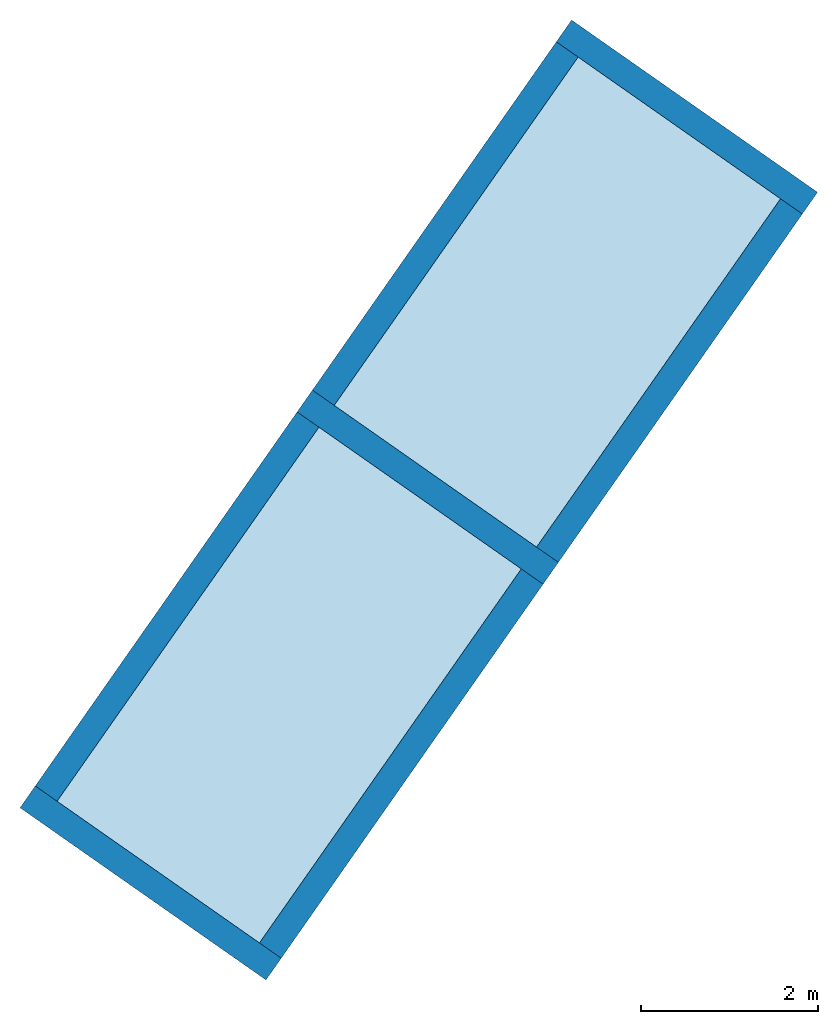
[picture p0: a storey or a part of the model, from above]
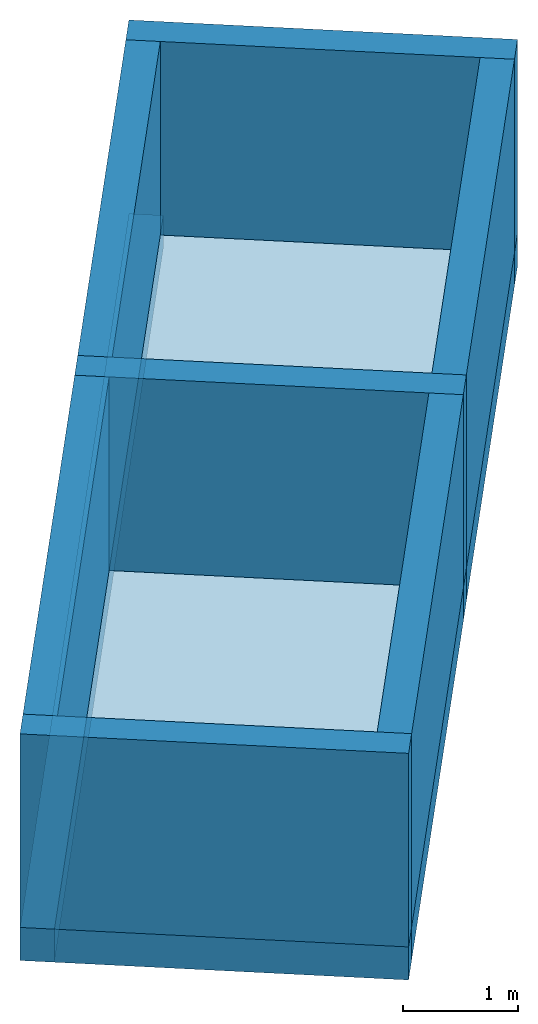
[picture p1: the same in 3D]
Properties of the parts of a building model (IFC2X3), part 1 of 5

# File
Description: ViewDefinition [CoordinationView_V2.0], RevitIdentifiers [VersionGUID: f28ca6dd-f931-496b-9c99-c5065d6128d1, NumberOfSaves: 65], CoordinateReference [CoordinateBase: Coordenadas compartidas, ProjectSite: Emplazamiento por defecto]
File name: IA-001
Time: 2025-02-13T22:48:25+01:00
Written by: ODA SDAI 24.3
Made in: Autodesk Revit 24.1.11.26 (ESP) - IFC 24.1.11.26

# IfcProject, IA-001
LongName: Unifamiliar Sant Josep de Sa Talaia; Phase: Estado de proyecto

# IfcSite, Default
RefLatitude: 40, 24, 0, 5493; RefLongitude: -3, -40, -59, -880065; RefElevation: 0 m

# IfcBuilding
Pset_BuildingCommon - NumberOfStoreys: 5

# IfcBuildingStorey: Nivel:Extremo inicial 8 mm (6)
Name | LongName | Elevation (m)
Depósito | Depósito | 93.64
Depósito_ | Depósito_ | 93.64
PB_ | PB_ | 95.94
PB | PB | 95.94
F1_ | F1_ | 99.52
F1 | F1 | 99.52

# IfcBeam (44)
Material: Hormigón armado
Pset_BeamCommon - Slope: 0 deg; IsExternal: no; LoadBearing: yes
Name | In
237957 | PB
237960 | PB
237963 | PB
237966 | PB
237969 | PB
237972 | PB
237975 | PB
237978 | PB
237981 | PB
237984 | PB
237987 | PB
237990 | PB
237993 | PB
237996 | PB
238196 | F1
238199 | F1
238202 | F1
238205 | F1
238208 | F1
238277 | F1
238280 | F1
238283 | F1
238286 | F1
238289 | F1
238292 | F1
238295 | F1
238298 | F1
238301 | F1
238434 | PB
238437 | PB
238440 | PB
238443 | PB
238547 | PB
238550 | PB
238564 | PB
238567 | PB
238582 | PB
238585 | PB
238588 | PB
238599 | PB
238602 | PB
238605 | PB
238641 | PB
238644 | PB

# IfcBeam: 1xT-18|T-0 (14)
In: Depósito_
Description: Pretensada. T18(20+5). Hormigón armado; Material: Hormigón armado
Pset_BeamCommon - IsExternal: no; LoadBearing: yes; Slope: 88.8324 deg
Pset_QuantityTakeOff - sets with these values: 2
Name | Pset_BeamCommon, Reference = Pset_QuantityTakeOff, Reference
Vigueta 1 (Paño 1) (1xT-18/T-0) | Vigueta 1 (Paño 1) (1xT-18/T-0)
Vigueta 2 (Paño 1) (1xT-18/T-0) | Vigueta 2 (Paño 1) (1xT-18/T-0)
Vigueta 3 (Paño 1) (1xT-18/T-0) | Vigueta 3 (Paño 1) (1xT-18/T-0)
Vigueta 4 (Paño 1) (1xT-18/T-0) | Vigueta 4 (Paño 1) (1xT-18/T-0)
Vigueta 5 (Paño 1) (1xT-18/T-0) | Vigueta 5 (Paño 1) (1xT-18/T-0)
Vigueta 6 (Paño 1) (1xT-18/T-0) | Vigueta 6 (Paño 1) (1xT-18/T-0)
Vigueta 7 (Paño 1) (1xT-18/T-0) | Vigueta 7 (Paño 1) (1xT-18/T-0)
Vigueta 1 (Paño 2) (1xT-18/T-0) | Vigueta 1 (Paño 2) (1xT-18/T-0)
Vigueta 2 (Paño 2) (1xT-18/T-0) | Vigueta 2 (Paño 2) (1xT-18/T-0)
Vigueta 3 (Paño 2) (1xT-18/T-0) | Vigueta 3 (Paño 2) (1xT-18/T-0)
Vigueta 4 (Paño 2) (1xT-18/T-0) | Vigueta 4 (Paño 2) (1xT-18/T-0)
Vigueta 5 (Paño 2) (1xT-18/T-0) | Vigueta 5 (Paño 2) (1xT-18/T-0)
Vigueta 6 (Paño 2) (1xT-18/T-0) | Vigueta 6 (Paño 2) (1xT-18/T-0)
Vigueta 7 (Paño 2) (1xT-18/T-0) | Vigueta 7 (Paño 2) (1xT-18/T-0)

# IfcBeam: 25x30 (4)
In: F1
Description: Rectangular. Hormigón armado; Material: Hormigón armado
Pset_BeamCommon - IsExternal: no; LoadBearing: yes
Pset_QuantityTakeOff - sets with these values: 2
Name | Pset_BeamCommon, Reference = Pset_QuantityTakeOff, Reference
Viga 27 (25x30) | Viga 27 (25x30)
Viga 28 (25x30) | Viga 28 (25x30)
Viga 32 (25x30) | Viga 32 (25x30)
Viga 33 (25x30) | Viga 33 (25x30)

# IfcBeam: 30x25 (9)
In: PB
Description: Rectangular. Hormigón armado; Material: Hormigón armado
Pset_BeamCommon - IsExternal: no; LoadBearing: yes
Pset_QuantityTakeOff - sets with these values: 2
Name | Pset_BeamCommon, Reference = Pset_QuantityTakeOff, Reference
Viga 1 (30x25) | Viga 1 (30x25)
Viga 2 (30x25) | Viga 2 (30x25)
Viga 3 (30x25) | Viga 3 (30x25)
Viga 4 (30x25) | Viga 4 (30x25)
Viga 5 (30x25) | Viga 5 (30x25)
Viga 6 (30x25) | Viga 6 (30x25)
Viga 7 (30x25) | Viga 7 (30x25)
Viga 8 (30x25) | Viga 8 (30x25)
Viga 9 (30x25) | Viga 9 (30x25)

# IfcBeam: 30x30 (17)
In: F1
Description: Rectangular. Hormigón armado; Material: Hormigón armado
Pset_BeamCommon - IsExternal: no; LoadBearing: yes
Pset_QuantityTakeOff - sets with these values: 2
Name | Pset_BeamCommon, Reference = Pset_QuantityTakeOff, Reference
Viga 1 (30x30) | Viga 1 (30x30)
Viga 2 (30x30) | Viga 2 (30x30)
Viga 3 (30x30) | Viga 3 (30x30)
Viga 11 (30x30) | Viga 11 (30x30)
Viga 12 (30x30) | Viga 12 (30x30)
Viga 13 (30x30) | Viga 13 (30x30)
Viga 14 (30x30) | Viga 14 (30x30)
Viga 15 (30x30) | Viga 15 (30x30)
Viga 16 (30x30) | Viga 16 (30x30)
Viga 17 (30x30) | Viga 17 (30x30)
Viga 18 (30x30) | Viga 18 (30x30)
Viga 19 (30x30) | Viga 19 (30x30)
Viga 20 (30x30) | Viga 20 (30x30)
Viga 29 (30x30) | Viga 29 (30x30)
Viga 31 (30x30) | Viga 31 (30x30)
Viga 34 (30x30) | Viga 34 (30x30)
Viga 35 (30x30) | Viga 35 (30x30)

# IfcBeam: 30x38, Viga 5 (30x38)
In: F1
Description: Rectangular. Hormigón armado; Material: Hormigón armado
Pset_BeamCommon - IsExternal: no; LoadBearing: yes; Reference: Viga 5 (30x38)
Pset_QuantityTakeOff - Reference: Viga 5 (30x38); sets with these values: 2

# IfcBeam: 30x72 (2)
In: F1
Description: Rectangular. Hormigón armado; Material: Hormigón armado
Pset_BeamCommon - IsExternal: no; LoadBearing: yes
Pset_QuantityTakeOff - sets with these values: 2
Name | Pset_BeamCommon, Reference = Pset_QuantityTakeOff, Reference
Viga 21 (30x72) | Viga 21 (30x72)
Viga 22 (30x72) | Viga 22 (30x72)

# IfcBeam: 30x76 (3)
In: F1
Description: Rectangular. Hormigón armado; Material: Hormigón armado
Pset_BeamCommon - IsExternal: no; LoadBearing: yes
Pset_QuantityTakeOff - sets with these values: 2
Name | Pset_BeamCommon, Reference = Pset_QuantityTakeOff, Reference
Viga 8 (30x76) | Viga 8 (30x76)
Viga 9 (30x76) | Viga 9 (30x76)
Viga 10 (30x76) | Viga 10 (30x76)

# IfcBeam: 30x80 (3)
In: F1
Description: Rectangular. Hormigón armado; Material: Hormigón armado
Pset_BeamCommon - IsExternal: no; LoadBearing: yes
Pset_QuantityTakeOff - sets with these values: 2
Name | Pset_BeamCommon, Reference = Pset_QuantityTakeOff, Reference
Viga 4 (30x80) | Viga 4 (30x80)
Viga 6 (30x80) | Viga 6 (30x80)
Viga 7 (30x80) | Viga 7 (30x80)

# IfcBeam: FOOTING_BEAM (5)
In: Depósito
Description: Rectangular. Hormigón armado; Material: Hormigón armado
Pset_BeamCommon - IsExternal: no; LoadBearing: yes
Pset_QuantityTakeOff - sets with these values: 2
Name | Pset_BeamCommon, Reference = Pset_QuantityTakeOff, Reference
Viga 1 (30x35) | Viga 1 (30x35)
Viga 2 (30x35) | Viga 2 (30x35)
Viga 3 (30x35) | Viga 3 (30x35)
Viga 4 (30x35) | Viga 4 (30x35)
Viga 5 (30x35) | Viga 5 (30x35)

# IfcBeam: Hormigón-Viga rectangular:300 x 400mm (5)
In: PB_
Type - Pset_BeamCommon - IsExternal: no; LoadBearing: yes
Pset_BeamCommon - Reference: 300 x 400mm; Span: 2.777 m; Slope: 0 deg
Pset_QuantityTakeOff - Reference: 300 x 400mm; sets with these values: 2
Name (Hormigón-Viga rectangular:300 x 400mm:...)
236829
236830
236831
236832
236833

# IfcBeam: Hormigón-Viga rectangular:400 x 400mm (5)
In: PB_
Type - Pset_BeamCommon - IsExternal: no; LoadBearing: yes
Pset_BeamCommon - Slope: 0 deg; Reference: 400 x 400mm
Pset_QuantityTakeOff - Reference: 400 x 400mm; sets with these values: 2
Name (Hormigón-Viga rectangular:400 x 400mm:...) | Span (m)
236834 | 3.61
236835 | 4.9
236836 | 4.915
236837 | 4.534
236838 | 4.602

# IfcBeam: Vigueta 1 (Paño 10) (Mf = 2.77)
In: PB
Type - Description: Armada. Covicsa Armada(25+5). Hormigón armado; PredefinedType: JOIST
Pset_BeamCommon - IsExternal: no; LoadBearing: yes; Reference: Vigueta 1 (Paño 10) (Mf = 2.77); Slope: 7.71638 deg
Pset_QuantityTakeOff - Reference: Vigueta 1 (Paño 10) (Mf = 2.77); sets with these values: 2

# IfcBeam: Vigueta 1 (Paño 11) (Mf = 0.88)
In: PB
Type - Description: Armada. Covicsa Armada(25+5). Hormigón armado; PredefinedType: JOIST
Pset_BeamCommon - IsExternal: no; LoadBearing: yes; Reference: Vigueta 1 (Paño 11) (Mf = 0.88); Slope: 7.71638 deg
Pset_QuantityTakeOff - Reference: Vigueta 1 (Paño 11) (Mf = 0.88); sets with these values: 2

# IfcBeam: Vigueta 1 (Paño 13) (Mf = 11.99)
In: PB
Type - Description: Armada. Covicsa Armada(25+5). Hormigón armado; PredefinedType: JOIST
Pset_BeamCommon - IsExternal: no; LoadBearing: yes; Reference: Vigueta 1 (Paño 13) (Mf = 11.99); Slope: 7.71638 deg
Pset_QuantityTakeOff - Reference: Vigueta 1 (Paño 13) (Mf = 11.99); sets with these values: 2

# IfcBeam: Vigueta 1 (Paño 15) (Mf = 33.15)
In: PB
Type - Description: Armada. Covicsa Armada(25+5). Hormigón armado; PredefinedType: JOIST
Pset_BeamCommon - IsExternal: no; LoadBearing: yes; Reference: Vigueta 1 (Paño 15) (Mf = 33.15); Slope: 7.71638 deg
Pset_QuantityTakeOff - Reference: Vigueta 1 (Paño 15) (Mf = 33.15); sets with these values: 2

# IfcBeam: Vigueta 1 (Paño 2) (Mf = 10.75)
In: PB
Type - Description: Armada. Covicsa Armada(25+5). Hormigón armado; PredefinedType: JOIST
Pset_BeamCommon - IsExternal: no; LoadBearing: yes; Reference: Vigueta 1 (Paño 2) (Mf = 10.75); Slope: 7.71638 deg
Pset_QuantityTakeOff - Reference: Vigueta 1 (Paño 2) (Mf = 10.75); sets with these values: 2

# IfcBeam: Vigueta 1 (Paño 3) (Mf = 14.41)
In: F1
Type - Description: Armada. Covicsa Armada(25+5). Hormigón armado; PredefinedType: JOIST
Pset_BeamCommon - IsExternal: no; LoadBearing: yes; Reference: Vigueta 1 (Paño 3) (Mf = 14.41); Slope: 7.71638 deg
Pset_QuantityTakeOff - Reference: Vigueta 1 (Paño 3) (Mf = 14.41); sets with these values: 2

# IfcBeam: Vigueta 1 (Paño 4) (Mf = 14.15)
In: F1
Type - Description: Armada. Covicsa Armada(25+5). Hormigón armado; PredefinedType: JOIST
Pset_BeamCommon - IsExternal: no; LoadBearing: yes; Reference: Vigueta 1 (Paño 4) (Mf = 14.15); Slope: 7.71638 deg
Pset_QuantityTakeOff - Reference: Vigueta 1 (Paño 4) (Mf = 14.15); sets with these values: 2

# IfcBeam: Vigueta 1 (Paño 6) (Mf = 33.36)
In: PB
Type - Description: Armada. Covicsa Armada(25+5). Hormigón armado; PredefinedType: JOIST
Pset_BeamCommon - IsExternal: no; LoadBearing: yes; Reference: Vigueta 1 (Paño 6) (Mf = 33.36); Slope: 7.71638 deg
Pset_QuantityTakeOff - Reference: Vigueta 1 (Paño 6) (Mf = 33.36); sets with these values: 2

# IfcBeam: Vigueta 1 (Paño 8) (Mf = 1.45)
In: PB
Type - Description: Armada. Covicsa Armada(25+5). Hormigón armado; PredefinedType: JOIST
Pset_BeamCommon - IsExternal: no; LoadBearing: yes; Reference: Vigueta 1 (Paño 8) (Mf = 1.45); Slope: 7.71638 deg
Pset_QuantityTakeOff - Reference: Vigueta 1 (Paño 8) (Mf = 1.45); sets with these values: 2

# IfcBeam: Vigueta 10 (Paño 2) (Mf = 10.63)
In: PB
Type - Description: Armada. Covicsa Armada(25+5). Hormigón armado; PredefinedType: JOIST
Pset_BeamCommon - IsExternal: no; LoadBearing: yes; Reference: Vigueta 10 (Paño 2) (Mf = 10.63); Slope: 7.71638 deg
Pset_QuantityTakeOff - Reference: Vigueta 10 (Paño 2) (Mf = 10.63); sets with these values: 2

# IfcBeam: Vigueta 11 (Paño 2) (Mf = 10.8)
In: PB
Type - Description: Armada. Covicsa Armada(25+5). Hormigón armado; PredefinedType: JOIST
Pset_BeamCommon - IsExternal: no; LoadBearing: yes; Reference: Vigueta 11 (Paño 2) (Mf = 10.8); Slope: 7.71638 deg
Pset_QuantityTakeOff - Reference: Vigueta 11 (Paño 2) (Mf = 10.8); sets with these values: 2

# IfcBeam: Vigueta 12 (Paño 2) (Mf = 10.92)
In: PB
Type - Description: Armada. Covicsa Armada(25+5). Hormigón armado; PredefinedType: JOIST
Pset_BeamCommon - IsExternal: no; LoadBearing: yes; Reference: Vigueta 12 (Paño 2) (Mf = 10.92); Slope: 7.71638 deg
Pset_QuantityTakeOff - Reference: Vigueta 12 (Paño 2) (Mf = 10.92); sets with these values: 2

# IfcBeam: Vigueta 13 (Paño 2) (Mf = 11.09)
In: PB
Type - Description: Armada. Covicsa Armada(25+5). Hormigón armado; PredefinedType: JOIST
Pset_BeamCommon - IsExternal: no; LoadBearing: yes; Reference: Vigueta 13 (Paño 2) (Mf = 11.09); Slope: 7.71638 deg
Pset_QuantityTakeOff - Reference: Vigueta 13 (Paño 2) (Mf = 11.09); sets with these values: 2

# IfcBeam: Vigueta 14 (Paño 2) (Mf = 11.17)
In: PB
Type - Description: Armada. Covicsa Armada(25+5). Hormigón armado; PredefinedType: JOIST
Pset_BeamCommon - IsExternal: no; LoadBearing: yes; Reference: Vigueta 14 (Paño 2) (Mf = 11.17); Slope: 7.71638 deg
Pset_QuantityTakeOff - Reference: Vigueta 14 (Paño 2) (Mf = 11.17); sets with these values: 2

# IfcBeam: Vigueta 2 (Paño 10) (Mf = 3.51)
In: PB
Type - Description: Armada. Covicsa Armada(25+5). Hormigón armado; PredefinedType: JOIST
Pset_BeamCommon - IsExternal: no; LoadBearing: yes; Reference: Vigueta 2 (Paño 10) (Mf = 3.51); Slope: 7.71638 deg
Pset_QuantityTakeOff - Reference: Vigueta 2 (Paño 10) (Mf = 3.51); sets with these values: 2

# IfcBeam: Vigueta 2 (Paño 11) (Mf = 0.17)
In: PB
Type - Description: Armada. Covicsa Armada(25+5). Hormigón armado; PredefinedType: JOIST
Pset_BeamCommon - IsExternal: no; LoadBearing: yes; Reference: Vigueta 2 (Paño 11) (Mf = 0.17); Slope: 7.71638 deg
Pset_QuantityTakeOff - Reference: Vigueta 2 (Paño 11) (Mf = 0.17); sets with these values: 2

# IfcBeam: Vigueta 2 (Paño 13) (Mf = 10.31)
In: PB
Type - Description: Armada. Covicsa Armada(25+5). Hormigón armado; PredefinedType: JOIST
Pset_BeamCommon - IsExternal: no; LoadBearing: yes; Reference: Vigueta 2 (Paño 13) (Mf = 10.31); Slope: 7.71638 deg
Pset_QuantityTakeOff - Reference: Vigueta 2 (Paño 13) (Mf = 10.31); sets with these values: 2

# IfcBeam: Vigueta 2 (Paño 15) (Mf = 35.75)
In: PB
Type - Description: Armada. Covicsa Armada(25+5). Hormigón armado; PredefinedType: JOIST
Pset_BeamCommon - IsExternal: no; LoadBearing: yes; Reference: Vigueta 2 (Paño 15) (Mf = 35.75); Slope: 7.71638 deg
Pset_QuantityTakeOff - Reference: Vigueta 2 (Paño 15) (Mf = 35.75); sets with these values: 2

# IfcBeam: Vigueta 2 (Paño 2) (Mf = 10.94)
In: PB
Type - Description: Armada. Covicsa Armada(25+5). Hormigón armado; PredefinedType: JOIST
Pset_BeamCommon - IsExternal: no; LoadBearing: yes; Reference: Vigueta 2 (Paño 2) (Mf = 10.94); Slope: 7.71638 deg
Pset_QuantityTakeOff - Reference: Vigueta 2 (Paño 2) (Mf = 10.94); sets with these values: 2

# IfcBeam: Vigueta 2 (Paño 3) (Mf = 14.34)
In: F1
Type - Description: Armada. Covicsa Armada(25+5). Hormigón armado; PredefinedType: JOIST
Pset_BeamCommon - IsExternal: no; LoadBearing: yes; Reference: Vigueta 2 (Paño 3) (Mf = 14.34); Slope: 7.71638 deg
Pset_QuantityTakeOff - Reference: Vigueta 2 (Paño 3) (Mf = 14.34); sets with these values: 2

# IfcBeam: Vigueta 2 (Paño 4) (Mf = 14.17)
In: F1
Type - Description: Armada. Covicsa Armada(25+5). Hormigón armado; PredefinedType: JOIST
Pset_BeamCommon - IsExternal: no; LoadBearing: yes; Reference: Vigueta 2 (Paño 4) (Mf = 14.17); Slope: 7.71638 deg
Pset_QuantityTakeOff - Reference: Vigueta 2 (Paño 4) (Mf = 14.17); sets with these values: 2

# IfcBeam: Vigueta 2 (Paño 6) (Mf = 33.44)
In: PB
Type - Description: Armada. Covicsa Armada(25+5). Hormigón armado; PredefinedType: JOIST
Pset_BeamCommon - IsExternal: no; LoadBearing: yes; Reference: Vigueta 2 (Paño 6) (Mf = 33.44); Slope: 7.71638 deg
Pset_QuantityTakeOff - Reference: Vigueta 2 (Paño 6) (Mf = 33.44); sets with these values: 2

# IfcBeam: Vigueta 2 (Paño 8) (Mf = 1.52)
In: PB
Type - Description: Armada. Covicsa Armada(25+5). Hormigón armado; PredefinedType: JOIST
Pset_BeamCommon - IsExternal: no; LoadBearing: yes; Reference: Vigueta 2 (Paño 8) (Mf = 1.52); Slope: 7.71638 deg
Pset_QuantityTakeOff - Reference: Vigueta 2 (Paño 8) (Mf = 1.52); sets with these values: 2

# IfcBeam: Vigueta 3 (Paño 11) (Mf = 0.89)
In: PB
Type - Description: Armada. Covicsa Armada(25+5). Hormigón armado; PredefinedType: JOIST
Pset_BeamCommon - IsExternal: no; LoadBearing: yes; Reference: Vigueta 3 (Paño 11) (Mf = 0.89); Slope: 7.71638 deg
Pset_QuantityTakeOff - Reference: Vigueta 3 (Paño 11) (Mf = 0.89); sets with these values: 2

# IfcBeam: Vigueta 3 (Paño 13) (Mf = 11.97)
In: PB
Type - Description: Armada. Covicsa Armada(25+5). Hormigón armado; PredefinedType: JOIST
Pset_BeamCommon - IsExternal: no; LoadBearing: yes; Reference: Vigueta 3 (Paño 13) (Mf = 11.97); Slope: 7.71638 deg
Pset_QuantityTakeOff - Reference: Vigueta 3 (Paño 13) (Mf = 11.97); sets with these values: 2

# IfcBeam: Vigueta 3 (Paño 2) (Mf = 10.32)
In: PB
Type - Description: Armada. Covicsa Armada(25+5). Hormigón armado; PredefinedType: JOIST
Pset_BeamCommon - IsExternal: no; LoadBearing: yes; Reference: Vigueta 3 (Paño 2) (Mf = 10.32); Slope: 7.71638 deg
Pset_QuantityTakeOff - Reference: Vigueta 3 (Paño 2) (Mf = 10.32); sets with these values: 2

# IfcBeam: Vigueta 3 (Paño 3) (Mf = 14.33)
In: F1
Type - Description: Armada. Covicsa Armada(25+5). Hormigón armado; PredefinedType: JOIST
Pset_BeamCommon - IsExternal: no; LoadBearing: yes; Reference: Vigueta 3 (Paño 3) (Mf = 14.33); Slope: 7.71638 deg
Pset_QuantityTakeOff - Reference: Vigueta 3 (Paño 3) (Mf = 14.33); sets with these values: 2

# IfcBeam: Vigueta 3 (Paño 4) (Mf = 14.35)
In: F1
Type - Description: Armada. Covicsa Armada(25+5). Hormigón armado; PredefinedType: JOIST
Pset_BeamCommon - IsExternal: no; LoadBearing: yes; Reference: Vigueta 3 (Paño 4) (Mf = 14.35); Slope: 7.71638 deg
Pset_QuantityTakeOff - Reference: Vigueta 3 (Paño 4) (Mf = 14.35); sets with these values: 2

# IfcBeam: Vigueta 3 (Paño 6) (Mf = 33.48)
In: PB
Type - Description: Armada. Covicsa Armada(25+5). Hormigón armado; PredefinedType: JOIST
Pset_BeamCommon - IsExternal: no; LoadBearing: yes; Reference: Vigueta 3 (Paño 6) (Mf = 33.48); Slope: 7.71638 deg
Pset_QuantityTakeOff - Reference: Vigueta 3 (Paño 6) (Mf = 33.48); sets with these values: 2

# IfcBeam: Vigueta 4 (Paño 2) (Mf = 10.95)
In: PB
Type - Description: Armada. Covicsa Armada(25+5). Hormigón armado; PredefinedType: JOIST
Pset_BeamCommon - IsExternal: no; LoadBearing: yes; Reference: Vigueta 4 (Paño 2) (Mf = 10.95); Slope: 7.71638 deg
Pset_QuantityTakeOff - Reference: Vigueta 4 (Paño 2) (Mf = 10.95); sets with these values: 2

# IfcBeam: Vigueta 4 (Paño 3) (Mf = 14.22)
In: F1
Type - Description: Armada. Covicsa Armada(25+5). Hormigón armado; PredefinedType: JOIST
Pset_BeamCommon - IsExternal: no; LoadBearing: yes; Reference: Vigueta 4 (Paño 3) (Mf = 14.22); Slope: 7.71638 deg
Pset_QuantityTakeOff - Reference: Vigueta 4 (Paño 3) (Mf = 14.22); sets with these values: 2

# IfcBeam: Vigueta 4 (Paño 4) (Mf = 14.11)
In: F1
Type - Description: Armada. Covicsa Armada(25+5). Hormigón armado; PredefinedType: JOIST
Pset_BeamCommon - IsExternal: no; LoadBearing: yes; Reference: Vigueta 4 (Paño 4) (Mf = 14.11); Slope: 7.71638 deg
Pset_QuantityTakeOff - Reference: Vigueta 4 (Paño 4) (Mf = 14.11); sets with these values: 2

# IfcBeam: Vigueta 4 (Paño 6) (Mf = 33.44)
In: PB
Type - Description: Armada. Covicsa Armada(25+5). Hormigón armado; PredefinedType: JOIST
Pset_BeamCommon - IsExternal: no; LoadBearing: yes; Reference: Vigueta 4 (Paño 6) (Mf = 33.44); Slope: 7.71638 deg
Pset_QuantityTakeOff - Reference: Vigueta 4 (Paño 6) (Mf = 33.44); sets with these values: 2

# IfcBeam: Vigueta 5 (Paño 2) (Mf = 10.69)
In: PB
Type - Description: Armada. Covicsa Armada(25+5). Hormigón armado; PredefinedType: JOIST
Pset_BeamCommon - IsExternal: no; LoadBearing: yes; Reference: Vigueta 5 (Paño 2) (Mf = 10.69); Slope: 7.71638 deg
Pset_QuantityTakeOff - Reference: Vigueta 5 (Paño 2) (Mf = 10.69); sets with these values: 2

# IfcBeam: Vigueta 5 (Paño 3) (Mf = 14.15)
In: F1
Type - Description: Armada. Covicsa Armada(25+5). Hormigón armado; PredefinedType: JOIST
Pset_BeamCommon - IsExternal: no; LoadBearing: yes; Reference: Vigueta 5 (Paño 3) (Mf = 14.15); Slope: 7.71638 deg
Pset_QuantityTakeOff - Reference: Vigueta 5 (Paño 3) (Mf = 14.15); sets with these values: 2

# IfcBeam: Vigueta 5 (Paño 4) (Mf = 14.09)
In: F1
Type - Description: Armada. Covicsa Armada(25+5). Hormigón armado; PredefinedType: JOIST
Pset_BeamCommon - IsExternal: no; LoadBearing: yes; Reference: Vigueta 5 (Paño 4) (Mf = 14.09); Slope: 7.71638 deg
Pset_QuantityTakeOff - Reference: Vigueta 5 (Paño 4) (Mf = 14.09); sets with these values: 2

# IfcBeam: Vigueta 6 (Paño 2) (Mf = 11.1)
In: PB
Type - Description: Armada. Covicsa Armada(25+5). Hormigón armado; PredefinedType: JOIST
Pset_BeamCommon - IsExternal: no; LoadBearing: yes; Reference: Vigueta 6 (Paño 2) (Mf = 11.1); Slope: 7.71638 deg
Pset_QuantityTakeOff - Reference: Vigueta 6 (Paño 2) (Mf = 11.1); sets with these values: 2

# IfcBeam: Vigueta 6 (Paño 4) (Mf = 11.71)
In: F1
Type - Description: Armada. Covicsa Armada(25+5). Hormigón armado; PredefinedType: JOIST
Pset_BeamCommon - IsExternal: no; LoadBearing: yes; Reference: Vigueta 6 (Paño 4) (Mf = 11.71); Slope: 7.71638 deg
Pset_QuantityTakeOff - Reference: Vigueta 6 (Paño 4) (Mf = 11.71); sets with these values: 2

# IfcBeam: Vigueta 7 (Paño 2) (Mf = 11.18)
In: PB
Type - Description: Armada. Covicsa Armada(25+5). Hormigón armado; PredefinedType: JOIST
Pset_BeamCommon - IsExternal: no; LoadBearing: yes; Reference: Vigueta 7 (Paño 2) (Mf = 11.18); Slope: 7.71638 deg
Pset_QuantityTakeOff - Reference: Vigueta 7 (Paño 2) (Mf = 11.18); sets with these values: 2

# IfcBeam: Vigueta 7 (Paño 4) (Mf = 14.16)
In: F1
Type - Description: Armada. Covicsa Armada(25+5). Hormigón armado; PredefinedType: JOIST
Pset_BeamCommon - IsExternal: no; LoadBearing: yes; Reference: Vigueta 7 (Paño 4) (Mf = 14.16); Slope: 7.71638 deg
Pset_QuantityTakeOff - Reference: Vigueta 7 (Paño 4) (Mf = 14.16); sets with these values: 2

# IfcBeam: Vigueta 8 (Paño 2) (Mf = 11.16)
In: PB
Type - Description: Armada. Covicsa Armada(25+5). Hormigón armado; PredefinedType: JOIST
Pset_BeamCommon - IsExternal: no; LoadBearing: yes; Reference: Vigueta 8 (Paño 2) (Mf = 11.16); Slope: 7.71638 deg
Pset_QuantityTakeOff - Reference: Vigueta 8 (Paño 2) (Mf = 11.16); sets with these values: 2

# IfcBeam: Vigueta 8 (Paño 4) (Mf = 14.18)
In: F1
Type - Description: Armada. Covicsa Armada(25+5). Hormigón armado; PredefinedType: JOIST
Pset_BeamCommon - IsExternal: no; LoadBearing: yes; Reference: Vigueta 8 (Paño 4) (Mf = 14.18); Slope: 7.71638 deg
Pset_QuantityTakeOff - Reference: Vigueta 8 (Paño 4) (Mf = 14.18); sets with these values: 2

# IfcBeam: Vigueta 9 (Paño 2) (Mf = 11)
In: PB
Type - Description: Armada. Covicsa Armada(25+5). Hormigón armado; PredefinedType: JOIST
Pset_BeamCommon - IsExternal: no; LoadBearing: yes; Reference: Vigueta 9 (Paño 2) (Mf = 11); Slope: 7.71638 deg
Pset_QuantityTakeOff - Reference: Vigueta 9 (Paño 2) (Mf = 11); sets with these values: 2

# IfcBeam: Vigueta 9 (Paño 4) (Mf = 14.29)
In: F1
Type - Description: Armada. Covicsa Armada(25+5). Hormigón armado; PredefinedType: JOIST
Pset_BeamCommon - IsExternal: no; LoadBearing: yes; Reference: Vigueta 9 (Paño 4) (Mf = 14.29); Slope: 7.71638 deg
Pset_QuantityTakeOff - Reference: Vigueta 9 (Paño 4) (Mf = 14.29); sets with these values: 2

# IfcBuildingElementProxy: Bovedilla 0-1 (Paño 10)
In: PB
Type - Description: Bovedilla de hormigón; PredefinedType: USERDEFINED
Pset_BuildingElementProxyCommon - Reference: Bovedilla 0-1 (Paño 10); sets with these values: 2
Pset_ProvisionForVoid - Shape: Undefined; Width: 0.58 m; Height: 0.25 m; Depth: 0.25 m

# IfcBuildingElementProxy: Bovedilla 0-1 (Paño 6)
In: PB
Type - Description: Bovedilla de hormigón; PredefinedType: USERDEFINED
Pset_BuildingElementProxyCommon - Reference: Bovedilla 0-1 (Paño 6); sets with these values: 2
Pset_ProvisionForVoid - Shape: Undefined; Width: 0.58 m; Height: 0.25 m; Depth: 0.25 m

# IfcBuildingElementProxy: Bovedilla 0-1 (Paño 8)
In: PB
Type - Description: Bovedilla de hormigón; PredefinedType: USERDEFINED
Pset_BuildingElementProxyCommon - Reference: Bovedilla 0-1 (Paño 8); sets with these values: 2
Pset_ProvisionForVoid - Shape: Undefined; Width: 0.58 m; Height: 0.25 m; Depth: 0.25 m

# IfcBuildingElementProxy: Bovedilla 0-10 (Paño 6)
In: PB
Type - Description: Bovedilla de hormigón; PredefinedType: USERDEFINED
Pset_BuildingElementProxyCommon - Reference: Bovedilla 0-10 (Paño 6); sets with these values: 2
Pset_ProvisionForVoid - Shape: Undefined; Width: 0.58 m; Height: 0.25 m; Depth: 0.25 m

# IfcBuildingElementProxy: Bovedilla 0-11 (Paño 6)
In: PB
Type - Description: Bovedilla de hormigón; PredefinedType: USERDEFINED
Pset_BuildingElementProxyCommon - Reference: Bovedilla 0-11 (Paño 6); sets with these values: 2
Pset_ProvisionForVoid - Shape: Undefined; Width: 0.58 m; Height: 0.25 m; Depth: 0.25 m

# IfcBuildingElementProxy: Bovedilla 0-12 (Paño 6)
In: PB
Type - Description: Bovedilla de hormigón; PredefinedType: USERDEFINED
Pset_BuildingElementProxyCommon - Reference: Bovedilla 0-12 (Paño 6); sets with these values: 2
Pset_ProvisionForVoid - Shape: Undefined; Width: 0.58 m; Height: 0.25 m; Depth: 0.25 m

# IfcBuildingElementProxy: Bovedilla 0-13 (Paño 6)
In: PB
Type - Description: Bovedilla de hormigón; PredefinedType: USERDEFINED
Pset_BuildingElementProxyCommon - Reference: Bovedilla 0-13 (Paño 6); sets with these values: 2
Pset_ProvisionForVoid - Shape: Undefined; Width: 0.58 m; Height: 0.25 m; Depth: 0.25 m

# IfcBuildingElementProxy: Bovedilla 0-14 (Paño 6)
In: PB
Type - Description: Bovedilla de hormigón; PredefinedType: USERDEFINED
Pset_BuildingElementProxyCommon - Reference: Bovedilla 0-14 (Paño 6); sets with these values: 2
Pset_ProvisionForVoid - Shape: Undefined; Width: 0.58 m; Height: 0.25 m; Depth: 0.25 m

# IfcBuildingElementProxy: Bovedilla 0-15 (Paño 6)
In: PB
Type - Description: Bovedilla de hormigón; PredefinedType: USERDEFINED
Pset_BuildingElementProxyCommon - Reference: Bovedilla 0-15 (Paño 6); sets with these values: 2
Pset_ProvisionForVoid - Shape: Undefined; Width: 0.58 m; Height: 0.25 m; Depth: 0.25 m

# IfcBuildingElementProxy: Bovedilla 0-16 (Paño 6)
In: PB
Type - Description: Bovedilla de hormigón; PredefinedType: USERDEFINED
Pset_BuildingElementProxyCommon - Reference: Bovedilla 0-16 (Paño 6); sets with these values: 2
Pset_ProvisionForVoid - Shape: Undefined; Width: 0.58 m; Height: 0.25 m; Depth: 0.25 m

# IfcBuildingElementProxy: Bovedilla 0-17 (Paño 6)
In: PB
Type - Description: Bovedilla de hormigón; PredefinedType: USERDEFINED
Pset_BuildingElementProxyCommon - Reference: Bovedilla 0-17 (Paño 6); sets with these values: 2
Pset_ProvisionForVoid - Shape: Undefined; Width: 0.58 m; Height: 0.25 m; Depth: 0.25 m

# IfcBuildingElementProxy: Bovedilla 0-18 (Paño 6)
In: PB
Type - Description: Bovedilla de hormigón; PredefinedType: USERDEFINED
Pset_BuildingElementProxyCommon - Reference: Bovedilla 0-18 (Paño 6); sets with these values: 2
Pset_ProvisionForVoid - Shape: Undefined; Width: 0.58 m; Height: 0.25 m; Depth: 0.25 m

# IfcBuildingElementProxy: Bovedilla 0-19 (Paño 6)
In: PB
Type - Description: Bovedilla de hormigón; PredefinedType: USERDEFINED
Pset_BuildingElementProxyCommon - Reference: Bovedilla 0-19 (Paño 6); sets with these values: 2
Pset_ProvisionForVoid - Shape: Undefined; Width: 0.58 m; Height: 0.25 m; Depth: 0.25 m

# IfcBuildingElementProxy: Bovedilla 0-2 (Paño 10)
In: PB
Type - Description: Bovedilla de hormigón; PredefinedType: USERDEFINED
Pset_BuildingElementProxyCommon - Reference: Bovedilla 0-2 (Paño 10); sets with these values: 2
Pset_ProvisionForVoid - Shape: Undefined; Width: 0.58 m; Height: 0.25 m; Depth: 0.25 m

# IfcBuildingElementProxy: Bovedilla 0-2 (Paño 6)
In: PB
Type - Description: Bovedilla de hormigón; PredefinedType: USERDEFINED
Pset_BuildingElementProxyCommon - Reference: Bovedilla 0-2 (Paño 6); sets with these values: 2
Pset_ProvisionForVoid - Shape: Undefined; Width: 0.58 m; Height: 0.25 m; Depth: 0.25 m

# IfcBuildingElementProxy: Bovedilla 0-2 (Paño 8)
In: PB
Type - Description: Bovedilla de hormigón; PredefinedType: USERDEFINED
Pset_BuildingElementProxyCommon - Reference: Bovedilla 0-2 (Paño 8); sets with these values: 2
Pset_ProvisionForVoid - Shape: Undefined; Width: 0.58 m; Height: 0.25 m; Depth: 0.25 m

# IfcBuildingElementProxy: Bovedilla 0-20 (Paño 6)
In: PB
Type - Description: Bovedilla de hormigón; PredefinedType: USERDEFINED
Pset_BuildingElementProxyCommon - Reference: Bovedilla 0-20 (Paño 6); sets with these values: 2
Pset_ProvisionForVoid - Shape: Undefined; Width: 0.58 m; Height: 0.25 m; Depth: 0.25 m

# IfcBuildingElementProxy: Bovedilla 0-21 (Paño 6)
In: PB
Type - Description: Bovedilla de hormigón; PredefinedType: USERDEFINED
Pset_BuildingElementProxyCommon - Reference: Bovedilla 0-21 (Paño 6); sets with these values: 2
Pset_ProvisionForVoid - Shape: Undefined; Width: 0.58 m; Height: 0.25 m; Depth: 0.25 m

# IfcBuildingElementProxy: Bovedilla 0-22 (Paño 6)
In: PB
Type - Description: Bovedilla de hormigón; PredefinedType: USERDEFINED
Pset_BuildingElementProxyCommon - Reference: Bovedilla 0-22 (Paño 6); sets with these values: 2
Pset_ProvisionForVoid - Shape: Undefined; Width: 0.58 m; Height: 0.25 m; Depth: 0.25 m

# IfcBuildingElementProxy: Bovedilla 0-23 (Paño 6)
In: PB
Type - Description: Bovedilla de hormigón; PredefinedType: USERDEFINED
Pset_BuildingElementProxyCommon - Reference: Bovedilla 0-23 (Paño 6); sets with these values: 2
Pset_ProvisionForVoid - Shape: Undefined; Width: 0.58 m; Height: 0.25 m; Depth: 0.25 m

# IfcBuildingElementProxy: Bovedilla 0-24 (Paño 6)
In: PB
Type - Description: Bovedilla de hormigón; PredefinedType: USERDEFINED
Pset_BuildingElementProxyCommon - Reference: Bovedilla 0-24 (Paño 6); sets with these values: 2
Pset_ProvisionForVoid - Shape: Undefined; Width: 0.58 m; Height: 0.25 m; Depth: 0.25 m

# IfcBuildingElementProxy: Bovedilla 0-3 (Paño 10)
In: PB
Type - Description: Bovedilla de hormigón; PredefinedType: USERDEFINED
Pset_BuildingElementProxyCommon - Reference: Bovedilla 0-3 (Paño 10); sets with these values: 2
Pset_ProvisionForVoid - Shape: Undefined; Width: 0.58 m; Height: 0.25 m; Depth: 0.25 m

# IfcBuildingElementProxy: Bovedilla 0-3 (Paño 6)
In: PB
Type - Description: Bovedilla de hormigón; PredefinedType: USERDEFINED
Pset_BuildingElementProxyCommon - Reference: Bovedilla 0-3 (Paño 6); sets with these values: 2
Pset_ProvisionForVoid - Shape: Undefined; Width: 0.58 m; Height: 0.25 m; Depth: 0.25 m

# IfcBuildingElementProxy: Bovedilla 0-3 (Paño 8)
In: PB
Type - Description: Bovedilla de hormigón; PredefinedType: USERDEFINED
Pset_BuildingElementProxyCommon - Reference: Bovedilla 0-3 (Paño 8); sets with these values: 2
Pset_ProvisionForVoid - Shape: Undefined; Width: 0.58 m; Height: 0.25 m; Depth: 0.25 m

# IfcBuildingElementProxy: Bovedilla 0-4 (Paño 10)
In: PB
Type - Description: Bovedilla de hormigón; PredefinedType: USERDEFINED
Pset_BuildingElementProxyCommon - Reference: Bovedilla 0-4 (Paño 10); sets with these values: 2
Pset_ProvisionForVoid - Shape: Undefined; Width: 0.58 m; Height: 0.25 m; Depth: 0.25 m

# IfcBuildingElementProxy: Bovedilla 0-4 (Paño 6)
In: PB
Type - Description: Bovedilla de hormigón; PredefinedType: USERDEFINED
Pset_BuildingElementProxyCommon - Reference: Bovedilla 0-4 (Paño 6); sets with these values: 2
Pset_ProvisionForVoid - Shape: Undefined; Width: 0.58 m; Height: 0.25 m; Depth: 0.25 m

# IfcBuildingElementProxy: Bovedilla 0-4 (Paño 8)
In: PB
Type - Description: Bovedilla de hormigón; PredefinedType: USERDEFINED
Pset_BuildingElementProxyCommon - Reference: Bovedilla 0-4 (Paño 8); sets with these values: 2
Pset_ProvisionForVoid - Shape: Undefined; Width: 0.58 m; Height: 0.25 m; Depth: 0.25 m

# IfcBuildingElementProxy: Bovedilla 0-5 (Paño 10)
In: PB
Type - Description: Bovedilla de hormigón; PredefinedType: USERDEFINED
Pset_BuildingElementProxyCommon - Reference: Bovedilla 0-5 (Paño 10); sets with these values: 2
Pset_ProvisionForVoid - Shape: Undefined; Width: 0.58 m; Height: 0.25 m; Depth: 0.25 m

# IfcBuildingElementProxy: Bovedilla 0-5 (Paño 6)
In: PB
Type - Description: Bovedilla de hormigón; PredefinedType: USERDEFINED
Pset_BuildingElementProxyCommon - Reference: Bovedilla 0-5 (Paño 6); sets with these values: 2
Pset_ProvisionForVoid - Shape: Undefined; Width: 0.58 m; Height: 0.25 m; Depth: 0.25 m

# IfcBuildingElementProxy: Bovedilla 0-6 (Paño 6)
In: PB
Type - Description: Bovedilla de hormigón; PredefinedType: USERDEFINED
Pset_BuildingElementProxyCommon - Reference: Bovedilla 0-6 (Paño 6); sets with these values: 2
Pset_ProvisionForVoid - Shape: Undefined; Width: 0.58 m; Height: 0.25 m; Depth: 0.25 m

# IfcBuildingElementProxy: Bovedilla 0-7 (Paño 6)
In: PB
Type - Description: Bovedilla de hormigón; PredefinedType: USERDEFINED
Pset_BuildingElementProxyCommon - Reference: Bovedilla 0-7 (Paño 6); sets with these values: 2
Pset_ProvisionForVoid - Shape: Undefined; Width: 0.58 m; Height: 0.25 m; Depth: 0.25 m

# IfcBuildingElementProxy: Bovedilla 0-8 (Paño 6)
In: PB
Type - Description: Bovedilla de hormigón; PredefinedType: USERDEFINED
Pset_BuildingElementProxyCommon - Reference: Bovedilla 0-8 (Paño 6); sets with these values: 2
Pset_ProvisionForVoid - Shape: Undefined; Width: 0.58 m; Height: 0.25 m; Depth: 0.25 m

# IfcBuildingElementProxy: Bovedilla 0-9 (Paño 6)
In: PB
Type - Description: Bovedilla de hormigón; PredefinedType: USERDEFINED
Pset_BuildingElementProxyCommon - Reference: Bovedilla 0-9 (Paño 6); sets with these values: 2
Pset_ProvisionForVoid - Shape: Undefined; Width: 0.58 m; Height: 0.25 m; Depth: 0.25 m

# IfcBuildingElementProxy: Bovedilla 1-1 (Paño 1)
In: Depósito_
Type - Description: Bovedilla de hormigón; PredefinedType: USERDEFINED
Pset_BuildingElementProxyCommon - Reference: Bovedilla 1-1 (Paño 1); sets with these values: 2
Pset_ProvisionForVoid - Shape: Undefined

# IfcBuildingElementProxy: Bovedilla 1-1 (Paño 10)
In: PB
Type - Description: Bovedilla de hormigón; PredefinedType: USERDEFINED
Pset_BuildingElementProxyCommon - Reference: Bovedilla 1-1 (Paño 10); sets with these values: 2
Pset_ProvisionForVoid - Shape: Undefined; Width: 0.58 m; Height: 0.25 m; Depth: 0.25 m

# IfcBuildingElementProxy: Bovedilla 1-1 (Paño 11)
In: PB
Type - Description: Bovedilla de hormigón; PredefinedType: USERDEFINED
Pset_BuildingElementProxyCommon - Reference: Bovedilla 1-1 (Paño 11); sets with these values: 2
Pset_ProvisionForVoid - Shape: Undefined; Width: 0.58 m; Height: 0.25 m; Depth: 0.25 m

# IfcBuildingElementProxy: Bovedilla 1-1 (Paño 13)
In: PB
Type - Description: Bovedilla de hormigón; PredefinedType: USERDEFINED
Pset_BuildingElementProxyCommon - Reference: Bovedilla 1-1 (Paño 13); sets with these values: 2
Pset_ProvisionForVoid - Shape: Undefined; Width: 0.58 m; Height: 0.25 m; Depth: 0.25 m

# IfcBuildingElementProxy: Bovedilla 1-1 (Paño 15)
In: PB
Type - Description: Bovedilla de hormigón; PredefinedType: USERDEFINED
Pset_BuildingElementProxyCommon - Reference: Bovedilla 1-1 (Paño 15); sets with these values: 2
Pset_ProvisionForVoid - Shape: Undefined; Width: 0.58 m; Height: 0.25 m; Depth: 0.25 m

# IfcBuildingElementProxy: Bovedilla 1-1 (Paño 2) (2)
Type - Description: Bovedilla de hormigón; PredefinedType: USERDEFINED
Pset_BuildingElementProxyCommon - Reference: Bovedilla 1-1 (Paño 2); sets with these values: 2
Pset_ProvisionForVoid - Shape: Undefined
Name | In
Bovedilla 1-1 (Paño 2) | Depósito_
Bovedilla 1-1 (Paño 2) | PB | Pset_ProvisionForVoid - Width: 0.58 m; Height: 0.25 m; Depth: 0.25 m

# IfcBuildingElementProxy: Bovedilla 1-1 (Paño 3)
In: F1
Type - Description: Bovedilla de hormigón; PredefinedType: USERDEFINED
Pset_BuildingElementProxyCommon - Reference: Bovedilla 1-1 (Paño 3); sets with these values: 2
Pset_ProvisionForVoid - Shape: Undefined; Width: 0.58 m; Height: 0.25 m; Depth: 0.25 m

# IfcBuildingElementProxy: Bovedilla 1-1 (Paño 4)
In: F1
Type - Description: Bovedilla de hormigón; PredefinedType: USERDEFINED
Pset_BuildingElementProxyCommon - Reference: Bovedilla 1-1 (Paño 4); sets with these values: 2
Pset_ProvisionForVoid - Shape: Undefined; Width: 0.58 m; Height: 0.25 m; Depth: 0.25 m

# IfcBuildingElementProxy: Bovedilla 1-1 (Paño 6)
In: PB
Type - Description: Bovedilla de hormigón; PredefinedType: USERDEFINED
Pset_BuildingElementProxyCommon - Reference: Bovedilla 1-1 (Paño 6); sets with these values: 2
Pset_ProvisionForVoid - Shape: Undefined; Width: 0.58 m; Height: 0.25 m; Depth: 0.25 m

# IfcBuildingElementProxy: Bovedilla 1-1 (Paño 8)
In: PB
Type - Description: Bovedilla de hormigón; PredefinedType: USERDEFINED
Pset_BuildingElementProxyCommon - Reference: Bovedilla 1-1 (Paño 8); sets with these values: 2
Pset_ProvisionForVoid - Shape: Undefined; Width: 0.58 m; Height: 0.25 m; Depth: 0.25 m

# IfcBuildingElementProxy: Bovedilla 1-10 (Paño 1)
In: Depósito_
Type - Description: Bovedilla de hormigón; PredefinedType: USERDEFINED
Pset_BuildingElementProxyCommon - Reference: Bovedilla 1-10 (Paño 1); sets with these values: 2
Pset_ProvisionForVoid - Shape: Undefined

# IfcBuildingElementProxy: Bovedilla 1-10 (Paño 13)
In: PB
Type - Description: Bovedilla de hormigón; PredefinedType: USERDEFINED
Pset_BuildingElementProxyCommon - Reference: Bovedilla 1-10 (Paño 13); sets with these values: 2
Pset_ProvisionForVoid - Shape: Undefined; Width: 0.58 m; Height: 0.25 m; Depth: 0.25 m

# IfcBuildingElementProxy: Bovedilla 1-10 (Paño 15)
In: PB
Type - Description: Bovedilla de hormigón; PredefinedType: USERDEFINED
Pset_BuildingElementProxyCommon - Reference: Bovedilla 1-10 (Paño 15); sets with these values: 2
Pset_ProvisionForVoid - Shape: Undefined; Width: 0.58 m; Height: 0.25 m; Depth: 0.25 m

# IfcBuildingElementProxy: Bovedilla 1-10 (Paño 2) (2)
Type - Description: Bovedilla de hormigón; PredefinedType: USERDEFINED
Pset_BuildingElementProxyCommon - Reference: Bovedilla 1-10 (Paño 2); sets with these values: 2
Pset_ProvisionForVoid - Shape: Undefined
Name | In
Bovedilla 1-10 (Paño 2) | Depósito_
Bovedilla 1-10 (Paño 2) | PB | Pset_ProvisionForVoid - Width: 0.58 m; Height: 0.25 m; Depth: 0.25 m

# IfcBuildingElementProxy: Bovedilla 1-10 (Paño 3)
In: F1
Type - Description: Bovedilla de hormigón; PredefinedType: USERDEFINED
Pset_BuildingElementProxyCommon - Reference: Bovedilla 1-10 (Paño 3); sets with these values: 2
Pset_ProvisionForVoid - Shape: Undefined; Width: 0.58 m; Height: 0.25 m; Depth: 0.25 m

# IfcBuildingElementProxy: Bovedilla 1-10 (Paño 4)
In: F1
Type - Description: Bovedilla de hormigón; PredefinedType: USERDEFINED
Pset_BuildingElementProxyCommon - Reference: Bovedilla 1-10 (Paño 4); sets with these values: 2
Pset_ProvisionForVoid - Shape: Undefined; Width: 0.58 m; Height: 0.25 m; Depth: 0.25 m

# IfcBuildingElementProxy: Bovedilla 1-10 (Paño 6)
In: PB
Type - Description: Bovedilla de hormigón; PredefinedType: USERDEFINED
Pset_BuildingElementProxyCommon - Reference: Bovedilla 1-10 (Paño 6); sets with these values: 2
Pset_ProvisionForVoid - Shape: Undefined; Width: 0.58 m; Height: 0.25 m; Depth: 0.25 m

# IfcBuildingElementProxy: Bovedilla 1-11 (Paño 1)
In: Depósito_
Type - Description: Bovedilla de hormigón; PredefinedType: USERDEFINED
Pset_BuildingElementProxyCommon - Reference: Bovedilla 1-11 (Paño 1); sets with these values: 2
Pset_ProvisionForVoid - Shape: Undefined

# IfcBuildingElementProxy: Bovedilla 1-11 (Paño 13)
In: PB
Type - Description: Bovedilla de hormigón; PredefinedType: USERDEFINED
Pset_BuildingElementProxyCommon - Reference: Bovedilla 1-11 (Paño 13); sets with these values: 2
Pset_ProvisionForVoid - Shape: Undefined; Width: 0.58 m; Height: 0.25 m; Depth: 0.25 m

# IfcBuildingElementProxy: Bovedilla 1-11 (Paño 15)
In: PB
Type - Description: Bovedilla de hormigón; PredefinedType: USERDEFINED
Pset_BuildingElementProxyCommon - Reference: Bovedilla 1-11 (Paño 15); sets with these values: 2
Pset_ProvisionForVoid - Shape: Undefined; Width: 0.58 m; Height: 0.25 m; Depth: 0.25 m

# IfcBuildingElementProxy: Bovedilla 1-11 (Paño 2) (2)
Type - Description: Bovedilla de hormigón; PredefinedType: USERDEFINED
Pset_BuildingElementProxyCommon - Reference: Bovedilla 1-11 (Paño 2); sets with these values: 2
Pset_ProvisionForVoid - Shape: Undefined
Name | In
Bovedilla 1-11 (Paño 2) | Depósito_
Bovedilla 1-11 (Paño 2) | PB | Pset_ProvisionForVoid - Width: 0.58 m; Height: 0.25 m; Depth: 0.25 m

# IfcBuildingElementProxy: Bovedilla 1-11 (Paño 3)
In: F1
Type - Description: Bovedilla de hormigón; PredefinedType: USERDEFINED
Pset_BuildingElementProxyCommon - Reference: Bovedilla 1-11 (Paño 3); sets with these values: 2
Pset_ProvisionForVoid - Shape: Undefined; Width: 0.58 m; Height: 0.25 m; Depth: 0.25 m

# IfcBuildingElementProxy: Bovedilla 1-11 (Paño 4)
In: F1
Type - Description: Bovedilla de hormigón; PredefinedType: USERDEFINED
Pset_BuildingElementProxyCommon - Reference: Bovedilla 1-11 (Paño 4); sets with these values: 2
Pset_ProvisionForVoid - Shape: Undefined; Width: 0.58 m; Height: 0.25 m; Depth: 0.25 m

# IfcBuildingElementProxy: Bovedilla 1-11 (Paño 6)
In: PB
Type - Description: Bovedilla de hormigón; PredefinedType: USERDEFINED
Pset_BuildingElementProxyCommon - Reference: Bovedilla 1-11 (Paño 6); sets with these values: 2
Pset_ProvisionForVoid - Shape: Undefined; Width: 0.58 m; Height: 0.25 m; Depth: 0.25 m

# IfcBuildingElementProxy: Bovedilla 1-12 (Paño 1)
In: Depósito_
Type - Description: Bovedilla de hormigón; PredefinedType: USERDEFINED
Pset_BuildingElementProxyCommon - Reference: Bovedilla 1-12 (Paño 1); sets with these values: 2
Pset_ProvisionForVoid - Shape: Undefined

# IfcBuildingElementProxy: Bovedilla 1-12 (Paño 13)
In: PB
Type - Description: Bovedilla de hormigón; PredefinedType: USERDEFINED
Pset_BuildingElementProxyCommon - Reference: Bovedilla 1-12 (Paño 13); sets with these values: 2
Pset_ProvisionForVoid - Shape: Undefined; Width: 0.58 m; Height: 0.25 m; Depth: 0.25 m

# IfcBuildingElementProxy: Bovedilla 1-12 (Paño 15)
In: PB
Type - Description: Bovedilla de hormigón; PredefinedType: USERDEFINED
Pset_BuildingElementProxyCommon - Reference: Bovedilla 1-12 (Paño 15); sets with these values: 2
Pset_ProvisionForVoid - Shape: Undefined; Width: 0.58 m; Height: 0.25 m; Depth: 0.25 m

# IfcBuildingElementProxy: Bovedilla 1-12 (Paño 2) (2)
Type - Description: Bovedilla de hormigón; PredefinedType: USERDEFINED
Pset_BuildingElementProxyCommon - Reference: Bovedilla 1-12 (Paño 2); sets with these values: 2
Pset_ProvisionForVoid - Shape: Undefined
Name | In
Bovedilla 1-12 (Paño 2) | Depósito_
Bovedilla 1-12 (Paño 2) | PB | Pset_ProvisionForVoid - Width: 0.58 m; Height: 0.25 m; Depth: 0.25 m

# IfcBuildingElementProxy: Bovedilla 1-12 (Paño 3)
In: F1
Type - Description: Bovedilla de hormigón; PredefinedType: USERDEFINED
Pset_BuildingElementProxyCommon - Reference: Bovedilla 1-12 (Paño 3); sets with these values: 2
Pset_ProvisionForVoid - Shape: Undefined; Width: 0.58 m; Height: 0.25 m; Depth: 0.25 m

# IfcBuildingElementProxy: Bovedilla 1-12 (Paño 4)
In: F1
Type - Description: Bovedilla de hormigón; PredefinedType: USERDEFINED
Pset_BuildingElementProxyCommon - Reference: Bovedilla 1-12 (Paño 4); sets with these values: 2
Pset_ProvisionForVoid - Shape: Undefined; Width: 0.58 m; Height: 0.25 m; Depth: 0.25 m

# IfcBuildingElementProxy: Bovedilla 1-12 (Paño 6)
In: PB
Type - Description: Bovedilla de hormigón; PredefinedType: USERDEFINED
Pset_BuildingElementProxyCommon - Reference: Bovedilla 1-12 (Paño 6); sets with these values: 2
Pset_ProvisionForVoid - Shape: Undefined; Width: 0.58 m; Height: 0.25 m; Depth: 0.25 m

# IfcBuildingElementProxy: Bovedilla 1-13 (Paño 1)
In: Depósito_
Type - Description: Bovedilla de hormigón; PredefinedType: USERDEFINED
Pset_BuildingElementProxyCommon - Reference: Bovedilla 1-13 (Paño 1); sets with these values: 2
Pset_ProvisionForVoid - Shape: Undefined

# IfcBuildingElementProxy: Bovedilla 1-13 (Paño 13)
In: PB
Type - Description: Bovedilla de hormigón; PredefinedType: USERDEFINED
Pset_BuildingElementProxyCommon - Reference: Bovedilla 1-13 (Paño 13); sets with these values: 2
Pset_ProvisionForVoid - Shape: Undefined; Width: 0.58 m; Height: 0.25 m; Depth: 0.25 m

# IfcBuildingElementProxy: Bovedilla 1-13 (Paño 15)
In: PB
Type - Description: Bovedilla de hormigón; PredefinedType: USERDEFINED
Pset_BuildingElementProxyCommon - Reference: Bovedilla 1-13 (Paño 15); sets with these values: 2
Pset_ProvisionForVoid - Shape: Undefined; Width: 0.58 m; Height: 0.25 m; Depth: 0.25 m

# IfcBuildingElementProxy: Bovedilla 1-13 (Paño 2) (2)
Type - Description: Bovedilla de hormigón; PredefinedType: USERDEFINED
Pset_BuildingElementProxyCommon - Reference: Bovedilla 1-13 (Paño 2); sets with these values: 2
Pset_ProvisionForVoid - Shape: Undefined
Name | In
Bovedilla 1-13 (Paño 2) | Depósito_
Bovedilla 1-13 (Paño 2) | PB | Pset_ProvisionForVoid - Width: 0.58 m; Height: 0.25 m; Depth: 0.25 m

# IfcBuildingElementProxy: Bovedilla 1-13 (Paño 3)
In: F1
Type - Description: Bovedilla de hormigón; PredefinedType: USERDEFINED
Pset_BuildingElementProxyCommon - Reference: Bovedilla 1-13 (Paño 3); sets with these values: 2
Pset_ProvisionForVoid - Shape: Undefined; Width: 0.58 m; Height: 0.25 m; Depth: 0.25 m

# IfcBuildingElementProxy: Bovedilla 1-13 (Paño 4)
In: F1
Type - Description: Bovedilla de hormigón; PredefinedType: USERDEFINED
Pset_BuildingElementProxyCommon - Reference: Bovedilla 1-13 (Paño 4); sets with these values: 2
Pset_ProvisionForVoid - Shape: Undefined; Width: 0.58 m; Height: 0.25 m; Depth: 0.25 m

# IfcBuildingElementProxy: Bovedilla 1-13 (Paño 6)
In: PB
Type - Description: Bovedilla de hormigón; PredefinedType: USERDEFINED
Pset_BuildingElementProxyCommon - Reference: Bovedilla 1-13 (Paño 6); sets with these values: 2
Pset_ProvisionForVoid - Shape: Undefined; Width: 0.58 m; Height: 0.25 m; Depth: 0.25 m

# IfcBuildingElementProxy: Bovedilla 1-14 (Paño 13)
In: PB
Type - Description: Bovedilla de hormigón; PredefinedType: USERDEFINED
Pset_BuildingElementProxyCommon - Reference: Bovedilla 1-14 (Paño 13); sets with these values: 2
Pset_ProvisionForVoid - Shape: Undefined; Width: 0.58 m; Height: 0.25 m; Depth: 0.25 m

# IfcBuildingElementProxy: Bovedilla 1-14 (Paño 15)
In: PB
Type - Description: Bovedilla de hormigón; PredefinedType: USERDEFINED
Pset_BuildingElementProxyCommon - Reference: Bovedilla 1-14 (Paño 15); sets with these values: 2
Pset_ProvisionForVoid - Shape: Undefined; Width: 0.58 m; Height: 0.25 m; Depth: 0.25 m

# IfcBuildingElementProxy: Bovedilla 1-14 (Paño 2)
In: PB
Type - Description: Bovedilla de hormigón; PredefinedType: USERDEFINED
Pset_BuildingElementProxyCommon - Reference: Bovedilla 1-14 (Paño 2); sets with these values: 2
Pset_ProvisionForVoid - Shape: Undefined; Width: 0.58 m; Height: 0.25 m; Depth: 0.25 m

# IfcBuildingElementProxy: Bovedilla 1-14 (Paño 3)
In: F1
Type - Description: Bovedilla de hormigón; PredefinedType: USERDEFINED
Pset_BuildingElementProxyCommon - Reference: Bovedilla 1-14 (Paño 3); sets with these values: 2
Pset_ProvisionForVoid - Shape: Undefined; Width: 0.58 m; Height: 0.25 m; Depth: 0.25 m

# IfcBuildingElementProxy: Bovedilla 1-14 (Paño 4)
In: F1
Type - Description: Bovedilla de hormigón; PredefinedType: USERDEFINED
Pset_BuildingElementProxyCommon - Reference: Bovedilla 1-14 (Paño 4); sets with these values: 2
Pset_ProvisionForVoid - Shape: Undefined; Width: 0.58 m; Height: 0.25 m; Depth: 0.25 m

# IfcBuildingElementProxy: Bovedilla 1-14 (Paño 6)
In: PB
Type - Description: Bovedilla de hormigón; PredefinedType: USERDEFINED
Pset_BuildingElementProxyCommon - Reference: Bovedilla 1-14 (Paño 6); sets with these values: 2
Pset_ProvisionForVoid - Shape: Undefined; Width: 0.58 m; Height: 0.25 m; Depth: 0.25 m

# IfcBuildingElementProxy: Bovedilla 1-15 (Paño 13)
In: PB
Type - Description: Bovedilla de hormigón; PredefinedType: USERDEFINED
Pset_BuildingElementProxyCommon - Reference: Bovedilla 1-15 (Paño 13); sets with these values: 2
Pset_ProvisionForVoid - Shape: Undefined; Width: 0.58 m; Height: 0.25 m; Depth: 0.25 m

# IfcBuildingElementProxy: Bovedilla 1-15 (Paño 15)
In: PB
Type - Description: Bovedilla de hormigón; PredefinedType: USERDEFINED
Pset_BuildingElementProxyCommon - Reference: Bovedilla 1-15 (Paño 15); sets with these values: 2
Pset_ProvisionForVoid - Shape: Undefined; Width: 0.58 m; Height: 0.25 m; Depth: 0.25 m

# IfcBuildingElementProxy: Bovedilla 1-15 (Paño 3)
In: F1
Type - Description: Bovedilla de hormigón; PredefinedType: USERDEFINED
Pset_BuildingElementProxyCommon - Reference: Bovedilla 1-15 (Paño 3); sets with these values: 2
Pset_ProvisionForVoid - Shape: Undefined; Width: 0.58 m; Height: 0.25 m; Depth: 0.25 m

# IfcBuildingElementProxy: Bovedilla 1-15 (Paño 4)
In: F1
Type - Description: Bovedilla de hormigón; PredefinedType: USERDEFINED
Pset_BuildingElementProxyCommon - Reference: Bovedilla 1-15 (Paño 4); sets with these values: 2
Pset_ProvisionForVoid - Shape: Undefined; Width: 0.58 m; Height: 0.25 m; Depth: 0.25 m

# IfcBuildingElementProxy: Bovedilla 1-15 (Paño 6)
In: PB
Type - Description: Bovedilla de hormigón; PredefinedType: USERDEFINED
Pset_BuildingElementProxyCommon - Reference: Bovedilla 1-15 (Paño 6); sets with these values: 2
Pset_ProvisionForVoid - Shape: Undefined; Width: 0.58 m; Height: 0.25 m; Depth: 0.25 m

# IfcBuildingElementProxy: Bovedilla 1-16 (Paño 15)
In: PB
Type - Description: Bovedilla de hormigón; PredefinedType: USERDEFINED
Pset_BuildingElementProxyCommon - Reference: Bovedilla 1-16 (Paño 15); sets with these values: 2
Pset_ProvisionForVoid - Shape: Undefined; Width: 0.58 m; Height: 0.25 m; Depth: 0.25 m

# IfcBuildingElementProxy: Bovedilla 1-16 (Paño 3)
In: F1
Type - Description: Bovedilla de hormigón; PredefinedType: USERDEFINED
Pset_BuildingElementProxyCommon - Reference: Bovedilla 1-16 (Paño 3); sets with these values: 2
Pset_ProvisionForVoid - Shape: Undefined; Width: 0.58 m; Height: 0.25 m; Depth: 0.25 m

# IfcBuildingElementProxy: Bovedilla 1-16 (Paño 4)
In: F1
Type - Description: Bovedilla de hormigón; PredefinedType: USERDEFINED
Pset_BuildingElementProxyCommon - Reference: Bovedilla 1-16 (Paño 4); sets with these values: 2
Pset_ProvisionForVoid - Shape: Undefined; Width: 0.58 m; Height: 0.25 m; Depth: 0.25 m

# IfcBuildingElementProxy: Bovedilla 1-16 (Paño 6)
In: PB
Type - Description: Bovedilla de hormigón; PredefinedType: USERDEFINED
Pset_BuildingElementProxyCommon - Reference: Bovedilla 1-16 (Paño 6); sets with these values: 2
Pset_ProvisionForVoid - Shape: Undefined; Width: 0.58 m; Height: 0.25 m; Depth: 0.25 m

# IfcBuildingElementProxy: Bovedilla 1-17 (Paño 15)
In: PB
Type - Description: Bovedilla de hormigón; PredefinedType: USERDEFINED
Pset_BuildingElementProxyCommon - Reference: Bovedilla 1-17 (Paño 15); sets with these values: 2
Pset_ProvisionForVoid - Shape: Undefined; Width: 0.58 m; Height: 0.25 m; Depth: 0.25 m

# IfcBuildingElementProxy: Bovedilla 1-17 (Paño 6)
In: PB
Type - Description: Bovedilla de hormigón; PredefinedType: USERDEFINED
Pset_BuildingElementProxyCommon - Reference: Bovedilla 1-17 (Paño 6); sets with these values: 2
Pset_ProvisionForVoid - Shape: Undefined; Width: 0.58 m; Height: 0.25 m; Depth: 0.25 m

# IfcBuildingElementProxy: Bovedilla 1-18 (Paño 15)
In: PB
Type - Description: Bovedilla de hormigón; PredefinedType: USERDEFINED
Pset_BuildingElementProxyCommon - Reference: Bovedilla 1-18 (Paño 15); sets with these values: 2
Pset_ProvisionForVoid - Shape: Undefined; Width: 0.58 m; Height: 0.25 m; Depth: 0.25 m

# IfcBuildingElementProxy: Bovedilla 1-18 (Paño 6)
In: PB
Type - Description: Bovedilla de hormigón; PredefinedType: USERDEFINED
Pset_BuildingElementProxyCommon - Reference: Bovedilla 1-18 (Paño 6); sets with these values: 2
Pset_ProvisionForVoid - Shape: Undefined; Width: 0.58 m; Height: 0.25 m; Depth: 0.25 m

# IfcBuildingElementProxy: Bovedilla 1-19 (Paño 15)
In: PB
Type - Description: Bovedilla de hormigón; PredefinedType: USERDEFINED
Pset_BuildingElementProxyCommon - Reference: Bovedilla 1-19 (Paño 15); sets with these values: 2
Pset_ProvisionForVoid - Shape: Undefined; Width: 0.58 m; Height: 0.25 m; Depth: 0.25 m

# IfcBuildingElementProxy: Bovedilla 1-19 (Paño 6)
In: PB
Type - Description: Bovedilla de hormigón; PredefinedType: USERDEFINED
Pset_BuildingElementProxyCommon - Reference: Bovedilla 1-19 (Paño 6); sets with these values: 2
Pset_ProvisionForVoid - Shape: Undefined; Width: 0.58 m; Height: 0.25 m; Depth: 0.25 m

# IfcBuildingElementProxy: Bovedilla 1-2 (Paño 1)
In: Depósito_
Type - Description: Bovedilla de hormigón; PredefinedType: USERDEFINED
Pset_BuildingElementProxyCommon - Reference: Bovedilla 1-2 (Paño 1); sets with these values: 2
Pset_ProvisionForVoid - Shape: Undefined

# IfcBuildingElementProxy: Bovedilla 1-2 (Paño 10)
In: PB
Type - Description: Bovedilla de hormigón; PredefinedType: USERDEFINED
Pset_BuildingElementProxyCommon - Reference: Bovedilla 1-2 (Paño 10); sets with these values: 2
Pset_ProvisionForVoid - Shape: Undefined; Width: 0.58 m; Height: 0.25 m; Depth: 0.25 m

# IfcBuildingElementProxy: Bovedilla 1-2 (Paño 11)
In: PB
Type - Description: Bovedilla de hormigón; PredefinedType: USERDEFINED
Pset_BuildingElementProxyCommon - Reference: Bovedilla 1-2 (Paño 11); sets with these values: 2
Pset_ProvisionForVoid - Shape: Undefined; Width: 0.58 m; Height: 0.25 m; Depth: 0.25 m

# IfcBuildingElementProxy: Bovedilla 1-2 (Paño 13)
In: PB
Type - Description: Bovedilla de hormigón; PredefinedType: USERDEFINED
Pset_BuildingElementProxyCommon - Reference: Bovedilla 1-2 (Paño 13); sets with these values: 2
Pset_ProvisionForVoid - Shape: Undefined; Width: 0.58 m; Height: 0.25 m; Depth: 0.25 m

# IfcBuildingElementProxy: Bovedilla 1-2 (Paño 15)
In: PB
Type - Description: Bovedilla de hormigón; PredefinedType: USERDEFINED
Pset_BuildingElementProxyCommon - Reference: Bovedilla 1-2 (Paño 15); sets with these values: 2
Pset_ProvisionForVoid - Shape: Undefined; Width: 0.58 m; Height: 0.25 m; Depth: 0.25 m

# IfcBuildingElementProxy: Bovedilla 1-2 (Paño 2) (2)
Type - Description: Bovedilla de hormigón; PredefinedType: USERDEFINED
Pset_BuildingElementProxyCommon - Reference: Bovedilla 1-2 (Paño 2); sets with these values: 2
Pset_ProvisionForVoid - Shape: Undefined
Name | In
Bovedilla 1-2 (Paño 2) | Depósito_
Bovedilla 1-2 (Paño 2) | PB | Pset_ProvisionForVoid - Width: 0.58 m; Height: 0.25 m; Depth: 0.25 m

# IfcBuildingElementProxy: Bovedilla 1-2 (Paño 3)
In: F1
Type - Description: Bovedilla de hormigón; PredefinedType: USERDEFINED
Pset_BuildingElementProxyCommon - Reference: Bovedilla 1-2 (Paño 3); sets with these values: 2
Pset_ProvisionForVoid - Shape: Undefined; Width: 0.58 m; Height: 0.25 m; Depth: 0.25 m

# IfcBuildingElementProxy: Bovedilla 1-2 (Paño 4)
In: F1
Type - Description: Bovedilla de hormigón; PredefinedType: USERDEFINED
Pset_BuildingElementProxyCommon - Reference: Bovedilla 1-2 (Paño 4); sets with these values: 2
Pset_ProvisionForVoid - Shape: Undefined; Width: 0.58 m; Height: 0.25 m; Depth: 0.25 m

# IfcBuildingElementProxy: Bovedilla 1-2 (Paño 6)
In: PB
Type - Description: Bovedilla de hormigón; PredefinedType: USERDEFINED
Pset_BuildingElementProxyCommon - Reference: Bovedilla 1-2 (Paño 6); sets with these values: 2
Pset_ProvisionForVoid - Shape: Undefined; Width: 0.58 m; Height: 0.25 m; Depth: 0.25 m

# IfcBuildingElementProxy: Bovedilla 1-2 (Paño 8)
In: PB
Type - Description: Bovedilla de hormigón; PredefinedType: USERDEFINED
Pset_BuildingElementProxyCommon - Reference: Bovedilla 1-2 (Paño 8); sets with these values: 2
Pset_ProvisionForVoid - Shape: Undefined; Width: 0.58 m; Height: 0.25 m; Depth: 0.25 m

# IfcBuildingElementProxy: Bovedilla 1-20 (Paño 15)
In: PB
Type - Description: Bovedilla de hormigón; PredefinedType: USERDEFINED
Pset_BuildingElementProxyCommon - Reference: Bovedilla 1-20 (Paño 15); sets with these values: 2
Pset_ProvisionForVoid - Shape: Undefined; Width: 0.58 m; Height: 0.25 m; Depth: 0.25 m

# IfcBuildingElementProxy: Bovedilla 1-20 (Paño 6)
In: PB
Type - Description: Bovedilla de hormigón; PredefinedType: USERDEFINED
Pset_BuildingElementProxyCommon - Reference: Bovedilla 1-20 (Paño 6); sets with these values: 2
Pset_ProvisionForVoid - Shape: Undefined; Width: 0.58 m; Height: 0.25 m; Depth: 0.25 m

# IfcBuildingElementProxy: Bovedilla 1-21 (Paño 15)
In: PB
Type - Description: Bovedilla de hormigón; PredefinedType: USERDEFINED
Pset_BuildingElementProxyCommon - Reference: Bovedilla 1-21 (Paño 15); sets with these values: 2
Pset_ProvisionForVoid - Shape: Undefined; Width: 0.58 m; Height: 0.25 m; Depth: 0.25 m

# IfcBuildingElementProxy: Bovedilla 1-21 (Paño 6)
In: PB
Type - Description: Bovedilla de hormigón; PredefinedType: USERDEFINED
Pset_BuildingElementProxyCommon - Reference: Bovedilla 1-21 (Paño 6); sets with these values: 2
Pset_ProvisionForVoid - Shape: Undefined; Width: 0.58 m; Height: 0.25 m; Depth: 0.25 m

# IfcBuildingElementProxy: Bovedilla 1-22 (Paño 15)
In: PB
Type - Description: Bovedilla de hormigón; PredefinedType: USERDEFINED
Pset_BuildingElementProxyCommon - Reference: Bovedilla 1-22 (Paño 15); sets with these values: 2
Pset_ProvisionForVoid - Shape: Undefined; Width: 0.58 m; Height: 0.25 m; Depth: 0.25 m

# IfcBuildingElementProxy: Bovedilla 1-22 (Paño 6)
In: PB
Type - Description: Bovedilla de hormigón; PredefinedType: USERDEFINED
Pset_BuildingElementProxyCommon - Reference: Bovedilla 1-22 (Paño 6); sets with these values: 2
Pset_ProvisionForVoid - Shape: Undefined; Width: 0.58 m; Height: 0.25 m; Depth: 0.25 m

# IfcBuildingElementProxy: Bovedilla 1-23 (Paño 15)
In: PB
Type - Description: Bovedilla de hormigón; PredefinedType: USERDEFINED
Pset_BuildingElementProxyCommon - Reference: Bovedilla 1-23 (Paño 15); sets with these values: 2
Pset_ProvisionForVoid - Shape: Undefined; Width: 0.58 m; Height: 0.25 m; Depth: 0.25 m

# IfcBuildingElementProxy: Bovedilla 1-23 (Paño 6)
In: PB
Type - Description: Bovedilla de hormigón; PredefinedType: USERDEFINED
Pset_BuildingElementProxyCommon - Reference: Bovedilla 1-23 (Paño 6); sets with these values: 2
Pset_ProvisionForVoid - Shape: Undefined; Width: 0.58 m; Height: 0.25 m; Depth: 0.25 m

# IfcBuildingElementProxy: Bovedilla 1-24 (Paño 15)
In: PB
Type - Description: Bovedilla de hormigón; PredefinedType: USERDEFINED
Pset_BuildingElementProxyCommon - Reference: Bovedilla 1-24 (Paño 15); sets with these values: 2
Pset_ProvisionForVoid - Shape: Undefined; Width: 0.58 m; Height: 0.25 m; Depth: 0.25 m

# IfcBuildingElementProxy: Bovedilla 1-24 (Paño 6)
In: PB
Type - Description: Bovedilla de hormigón; PredefinedType: USERDEFINED
Pset_BuildingElementProxyCommon - Reference: Bovedilla 1-24 (Paño 6); sets with these values: 2
Pset_ProvisionForVoid - Shape: Undefined; Width: 0.58 m; Height: 0.25 m; Depth: 0.25 m

# IfcBuildingElementProxy: Bovedilla 1-25 (Paño 15)
In: PB
Type - Description: Bovedilla de hormigón; PredefinedType: USERDEFINED
Pset_BuildingElementProxyCommon - Reference: Bovedilla 1-25 (Paño 15); sets with these values: 2
Pset_ProvisionForVoid - Shape: Undefined; Width: 0.58 m; Height: 0.25 m; Depth: 0.25 m

# IfcBuildingElementProxy: Bovedilla 1-25 (Paño 6)
In: PB
Type - Description: Bovedilla de hormigón; PredefinedType: USERDEFINED
Pset_BuildingElementProxyCommon - Reference: Bovedilla 1-25 (Paño 6); sets with these values: 2
Pset_ProvisionForVoid - Shape: Undefined; Width: 0.58 m; Height: 0.25 m; Depth: 0.25 m

# IfcBuildingElementProxy: Bovedilla 1-3 (Paño 1)
In: Depósito_
Type - Description: Bovedilla de hormigón; PredefinedType: USERDEFINED
Pset_BuildingElementProxyCommon - Reference: Bovedilla 1-3 (Paño 1); sets with these values: 2
Pset_ProvisionForVoid - Shape: Undefined

# IfcBuildingElementProxy: Bovedilla 1-3 (Paño 10)
In: PB
Type - Description: Bovedilla de hormigón; PredefinedType: USERDEFINED
Pset_BuildingElementProxyCommon - Reference: Bovedilla 1-3 (Paño 10); sets with these values: 2
Pset_ProvisionForVoid - Shape: Undefined; Width: 0.58 m; Height: 0.25 m; Depth: 0.25 m

# IfcBuildingElementProxy: Bovedilla 1-3 (Paño 11)
In: PB
Type - Description: Bovedilla de hormigón; PredefinedType: USERDEFINED
Pset_BuildingElementProxyCommon - Reference: Bovedilla 1-3 (Paño 11); sets with these values: 2
Pset_ProvisionForVoid - Shape: Undefined; Width: 0.58 m; Height: 0.25 m; Depth: 0.25 m

# IfcBuildingElementProxy: Bovedilla 1-3 (Paño 13)
In: PB
Type - Description: Bovedilla de hormigón; PredefinedType: USERDEFINED
Pset_BuildingElementProxyCommon - Reference: Bovedilla 1-3 (Paño 13); sets with these values: 2
Pset_ProvisionForVoid - Shape: Undefined; Width: 0.58 m; Height: 0.25 m; Depth: 0.25 m

# IfcBuildingElementProxy: Bovedilla 1-3 (Paño 15)
In: PB
Type - Description: Bovedilla de hormigón; PredefinedType: USERDEFINED
Pset_BuildingElementProxyCommon - Reference: Bovedilla 1-3 (Paño 15); sets with these values: 2
Pset_ProvisionForVoid - Shape: Undefined; Width: 0.58 m; Height: 0.25 m; Depth: 0.25 m

# IfcBuildingElementProxy: Bovedilla 1-3 (Paño 2) (2)
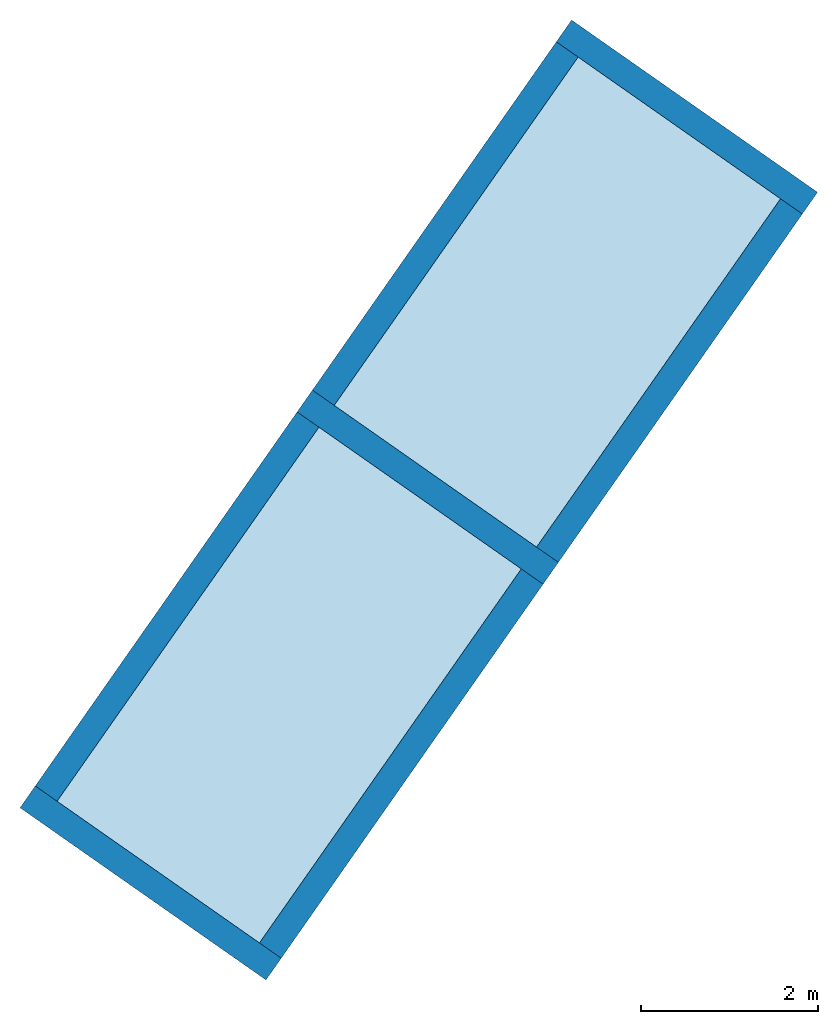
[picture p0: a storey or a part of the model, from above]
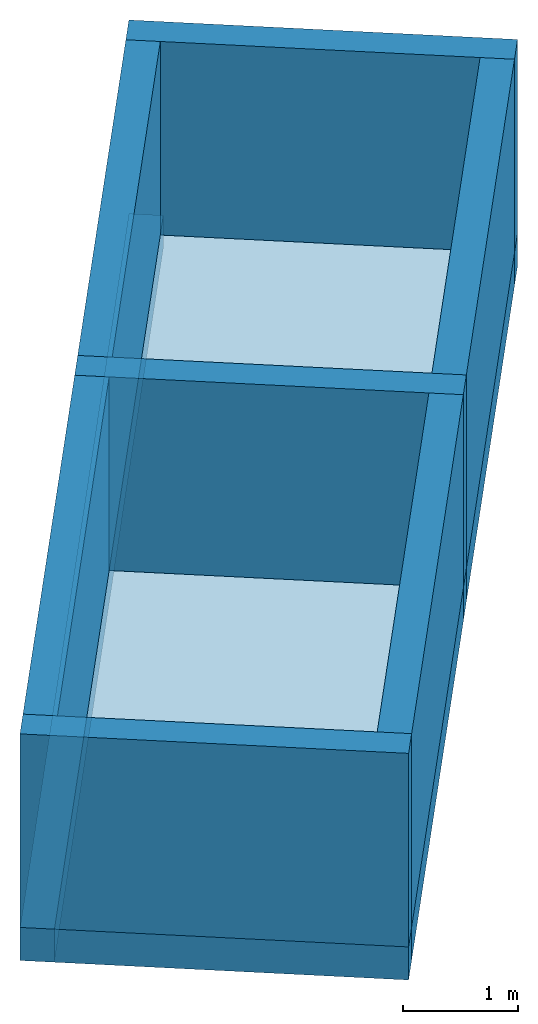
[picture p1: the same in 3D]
Properties of the parts of a building model (IFC2X3), part 2 of 5

# IfcBuildingElementProxy: Bovedilla 1-3 (Paño 2) (2)
Type - Description: Bovedilla de hormigón; PredefinedType: USERDEFINED
Pset_BuildingElementProxyCommon - Reference: Bovedilla 1-3 (Paño 2); sets with these values: 2
Pset_ProvisionForVoid - Shape: Undefined
Name | In
Bovedilla 1-3 (Paño 2) | Depósito_
Bovedilla 1-3 (Paño 2) | PB | Pset_ProvisionForVoid - Width: 0.58 m; Height: 0.25 m; Depth: 0.25 m

# IfcBuildingElementProxy: Bovedilla 1-3 (Paño 3)
In: F1
Type - Description: Bovedilla de hormigón; PredefinedType: USERDEFINED
Pset_BuildingElementProxyCommon - Reference: Bovedilla 1-3 (Paño 3); sets with these values: 2
Pset_ProvisionForVoid - Shape: Undefined; Width: 0.58 m; Height: 0.25 m; Depth: 0.25 m

# IfcBuildingElementProxy: Bovedilla 1-3 (Paño 4)
In: F1
Type - Description: Bovedilla de hormigón; PredefinedType: USERDEFINED
Pset_BuildingElementProxyCommon - Reference: Bovedilla 1-3 (Paño 4); sets with these values: 2
Pset_ProvisionForVoid - Shape: Undefined; Width: 0.58 m; Height: 0.25 m; Depth: 0.25 m

# IfcBuildingElementProxy: Bovedilla 1-3 (Paño 6)
In: PB
Type - Description: Bovedilla de hormigón; PredefinedType: USERDEFINED
Pset_BuildingElementProxyCommon - Reference: Bovedilla 1-3 (Paño 6); sets with these values: 2
Pset_ProvisionForVoid - Shape: Undefined; Width: 0.58 m; Height: 0.25 m; Depth: 0.25 m

# IfcBuildingElementProxy: Bovedilla 1-3 (Paño 8)
In: PB
Type - Description: Bovedilla de hormigón; PredefinedType: USERDEFINED
Pset_BuildingElementProxyCommon - Reference: Bovedilla 1-3 (Paño 8); sets with these values: 2
Pset_ProvisionForVoid - Shape: Undefined; Width: 0.58 m; Height: 0.25 m; Depth: 0.25 m

# IfcBuildingElementProxy: Bovedilla 1-4 (Paño 1)
In: Depósito_
Type - Description: Bovedilla de hormigón; PredefinedType: USERDEFINED
Pset_BuildingElementProxyCommon - Reference: Bovedilla 1-4 (Paño 1); sets with these values: 2
Pset_ProvisionForVoid - Shape: Undefined

# IfcBuildingElementProxy: Bovedilla 1-4 (Paño 10)
In: PB
Type - Description: Bovedilla de hormigón; PredefinedType: USERDEFINED
Pset_BuildingElementProxyCommon - Reference: Bovedilla 1-4 (Paño 10); sets with these values: 2
Pset_ProvisionForVoid - Shape: Undefined; Width: 0.58 m; Height: 0.25 m; Depth: 0.25 m

# IfcBuildingElementProxy: Bovedilla 1-4 (Paño 13)
In: PB
Type - Description: Bovedilla de hormigón; PredefinedType: USERDEFINED
Pset_BuildingElementProxyCommon - Reference: Bovedilla 1-4 (Paño 13); sets with these values: 2
Pset_ProvisionForVoid - Shape: Undefined; Width: 0.58 m; Height: 0.25 m; Depth: 0.25 m

# IfcBuildingElementProxy: Bovedilla 1-4 (Paño 15)
In: PB
Type - Description: Bovedilla de hormigón; PredefinedType: USERDEFINED
Pset_BuildingElementProxyCommon - Reference: Bovedilla 1-4 (Paño 15); sets with these values: 2
Pset_ProvisionForVoid - Shape: Undefined; Width: 0.58 m; Height: 0.25 m; Depth: 0.25 m

# IfcBuildingElementProxy: Bovedilla 1-4 (Paño 2) (2)
Type - Description: Bovedilla de hormigón; PredefinedType: USERDEFINED
Pset_BuildingElementProxyCommon - Reference: Bovedilla 1-4 (Paño 2); sets with these values: 2
Pset_ProvisionForVoid - Shape: Undefined
Name | In
Bovedilla 1-4 (Paño 2) | Depósito_
Bovedilla 1-4 (Paño 2) | PB | Pset_ProvisionForVoid - Width: 0.58 m; Height: 0.25 m; Depth: 0.25 m

# IfcBuildingElementProxy: Bovedilla 1-4 (Paño 3)
In: F1
Type - Description: Bovedilla de hormigón; PredefinedType: USERDEFINED
Pset_BuildingElementProxyCommon - Reference: Bovedilla 1-4 (Paño 3); sets with these values: 2
Pset_ProvisionForVoid - Shape: Undefined; Width: 0.58 m; Height: 0.25 m; Depth: 0.25 m

# IfcBuildingElementProxy: Bovedilla 1-4 (Paño 4)
In: F1
Type - Description: Bovedilla de hormigón; PredefinedType: USERDEFINED
Pset_BuildingElementProxyCommon - Reference: Bovedilla 1-4 (Paño 4); sets with these values: 2
Pset_ProvisionForVoid - Shape: Undefined; Width: 0.58 m; Height: 0.25 m; Depth: 0.25 m

# IfcBuildingElementProxy: Bovedilla 1-4 (Paño 6)
In: PB
Type - Description: Bovedilla de hormigón; PredefinedType: USERDEFINED
Pset_BuildingElementProxyCommon - Reference: Bovedilla 1-4 (Paño 6); sets with these values: 2
Pset_ProvisionForVoid - Shape: Undefined; Width: 0.58 m; Height: 0.25 m; Depth: 0.25 m

# IfcBuildingElementProxy: Bovedilla 1-4 (Paño 8)
In: PB
Type - Description: Bovedilla de hormigón; PredefinedType: USERDEFINED
Pset_BuildingElementProxyCommon - Reference: Bovedilla 1-4 (Paño 8); sets with these values: 2
Pset_ProvisionForVoid - Shape: Undefined; Width: 0.58 m; Height: 0.25 m; Depth: 0.25 m

# IfcBuildingElementProxy: Bovedilla 1-5 (Paño 1)
In: Depósito_
Type - Description: Bovedilla de hormigón; PredefinedType: USERDEFINED
Pset_BuildingElementProxyCommon - Reference: Bovedilla 1-5 (Paño 1); sets with these values: 2
Pset_ProvisionForVoid - Shape: Undefined

# IfcBuildingElementProxy: Bovedilla 1-5 (Paño 10)
In: PB
Type - Description: Bovedilla de hormigón; PredefinedType: USERDEFINED
Pset_BuildingElementProxyCommon - Reference: Bovedilla 1-5 (Paño 10); sets with these values: 2
Pset_ProvisionForVoid - Shape: Undefined; Width: 0.58 m; Height: 0.25 m; Depth: 0.25 m

# IfcBuildingElementProxy: Bovedilla 1-5 (Paño 13)
In: PB
Type - Description: Bovedilla de hormigón; PredefinedType: USERDEFINED
Pset_BuildingElementProxyCommon - Reference: Bovedilla 1-5 (Paño 13); sets with these values: 2
Pset_ProvisionForVoid - Shape: Undefined; Width: 0.58 m; Height: 0.25 m; Depth: 0.25 m

# IfcBuildingElementProxy: Bovedilla 1-5 (Paño 15)
In: PB
Type - Description: Bovedilla de hormigón; PredefinedType: USERDEFINED
Pset_BuildingElementProxyCommon - Reference: Bovedilla 1-5 (Paño 15); sets with these values: 2
Pset_ProvisionForVoid - Shape: Undefined; Width: 0.58 m; Height: 0.25 m; Depth: 0.25 m

# IfcBuildingElementProxy: Bovedilla 1-5 (Paño 2) (2)
Type - Description: Bovedilla de hormigón; PredefinedType: USERDEFINED
Pset_BuildingElementProxyCommon - Reference: Bovedilla 1-5 (Paño 2); sets with these values: 2
Pset_ProvisionForVoid - Shape: Undefined
Name | In
Bovedilla 1-5 (Paño 2) | Depósito_
Bovedilla 1-5 (Paño 2) | PB | Pset_ProvisionForVoid - Width: 0.58 m; Height: 0.25 m; Depth: 0.25 m

# IfcBuildingElementProxy: Bovedilla 1-5 (Paño 3)
In: F1
Type - Description: Bovedilla de hormigón; PredefinedType: USERDEFINED
Pset_BuildingElementProxyCommon - Reference: Bovedilla 1-5 (Paño 3); sets with these values: 2
Pset_ProvisionForVoid - Shape: Undefined; Width: 0.58 m; Height: 0.25 m; Depth: 0.25 m

# IfcBuildingElementProxy: Bovedilla 1-5 (Paño 4)
In: F1
Type - Description: Bovedilla de hormigón; PredefinedType: USERDEFINED
Pset_BuildingElementProxyCommon - Reference: Bovedilla 1-5 (Paño 4); sets with these values: 2
Pset_ProvisionForVoid - Shape: Undefined; Width: 0.58 m; Height: 0.25 m; Depth: 0.25 m

# IfcBuildingElementProxy: Bovedilla 1-5 (Paño 6)
In: PB
Type - Description: Bovedilla de hormigón; PredefinedType: USERDEFINED
Pset_BuildingElementProxyCommon - Reference: Bovedilla 1-5 (Paño 6); sets with these values: 2
Pset_ProvisionForVoid - Shape: Undefined; Width: 0.58 m; Height: 0.25 m; Depth: 0.25 m

# IfcBuildingElementProxy: Bovedilla 1-5 (Paño 8)
In: PB
Type - Description: Bovedilla de hormigón; PredefinedType: USERDEFINED
Pset_BuildingElementProxyCommon - Reference: Bovedilla 1-5 (Paño 8); sets with these values: 2
Pset_ProvisionForVoid - Shape: Undefined; Width: 0.58 m; Height: 0.25 m; Depth: 0.25 m

# IfcBuildingElementProxy: Bovedilla 1-6 (Paño 1)
In: Depósito_
Type - Description: Bovedilla de hormigón; PredefinedType: USERDEFINED
Pset_BuildingElementProxyCommon - Reference: Bovedilla 1-6 (Paño 1); sets with these values: 2
Pset_ProvisionForVoid - Shape: Undefined

# IfcBuildingElementProxy: Bovedilla 1-6 (Paño 13)
In: PB
Type - Description: Bovedilla de hormigón; PredefinedType: USERDEFINED
Pset_BuildingElementProxyCommon - Reference: Bovedilla 1-6 (Paño 13); sets with these values: 2
Pset_ProvisionForVoid - Shape: Undefined; Width: 0.58 m; Height: 0.25 m; Depth: 0.25 m

# IfcBuildingElementProxy: Bovedilla 1-6 (Paño 15)
In: PB
Type - Description: Bovedilla de hormigón; PredefinedType: USERDEFINED
Pset_BuildingElementProxyCommon - Reference: Bovedilla 1-6 (Paño 15); sets with these values: 2
Pset_ProvisionForVoid - Shape: Undefined; Width: 0.58 m; Height: 0.25 m; Depth: 0.25 m

# IfcBuildingElementProxy: Bovedilla 1-6 (Paño 2) (2)
Type - Description: Bovedilla de hormigón; PredefinedType: USERDEFINED
Pset_BuildingElementProxyCommon - Reference: Bovedilla 1-6 (Paño 2); sets with these values: 2
Pset_ProvisionForVoid - Shape: Undefined
Name | In
Bovedilla 1-6 (Paño 2) | Depósito_
Bovedilla 1-6 (Paño 2) | PB | Pset_ProvisionForVoid - Width: 0.58 m; Height: 0.25 m; Depth: 0.25 m

# IfcBuildingElementProxy: Bovedilla 1-6 (Paño 3)
In: F1
Type - Description: Bovedilla de hormigón; PredefinedType: USERDEFINED
Pset_BuildingElementProxyCommon - Reference: Bovedilla 1-6 (Paño 3); sets with these values: 2
Pset_ProvisionForVoid - Shape: Undefined; Width: 0.58 m; Height: 0.25 m; Depth: 0.25 m

# IfcBuildingElementProxy: Bovedilla 1-6 (Paño 4)
In: F1
Type - Description: Bovedilla de hormigón; PredefinedType: USERDEFINED
Pset_BuildingElementProxyCommon - Reference: Bovedilla 1-6 (Paño 4); sets with these values: 2
Pset_ProvisionForVoid - Shape: Undefined; Width: 0.58 m; Height: 0.25 m; Depth: 0.25 m

# IfcBuildingElementProxy: Bovedilla 1-6 (Paño 6)
In: PB
Type - Description: Bovedilla de hormigón; PredefinedType: USERDEFINED
Pset_BuildingElementProxyCommon - Reference: Bovedilla 1-6 (Paño 6); sets with these values: 2
Pset_ProvisionForVoid - Shape: Undefined; Width: 0.58 m; Height: 0.25 m; Depth: 0.25 m

# IfcBuildingElementProxy: Bovedilla 1-7 (Paño 1)
In: Depósito_
Type - Description: Bovedilla de hormigón; PredefinedType: USERDEFINED
Pset_BuildingElementProxyCommon - Reference: Bovedilla 1-7 (Paño 1); sets with these values: 2
Pset_ProvisionForVoid - Shape: Undefined

# IfcBuildingElementProxy: Bovedilla 1-7 (Paño 13)
In: PB
Type - Description: Bovedilla de hormigón; PredefinedType: USERDEFINED
Pset_BuildingElementProxyCommon - Reference: Bovedilla 1-7 (Paño 13); sets with these values: 2
Pset_ProvisionForVoid - Shape: Undefined; Width: 0.58 m; Height: 0.25 m; Depth: 0.25 m

# IfcBuildingElementProxy: Bovedilla 1-7 (Paño 15)
In: PB
Type - Description: Bovedilla de hormigón; PredefinedType: USERDEFINED
Pset_BuildingElementProxyCommon - Reference: Bovedilla 1-7 (Paño 15); sets with these values: 2
Pset_ProvisionForVoid - Shape: Undefined; Width: 0.58 m; Height: 0.25 m; Depth: 0.25 m

# IfcBuildingElementProxy: Bovedilla 1-7 (Paño 2) (2)
Type - Description: Bovedilla de hormigón; PredefinedType: USERDEFINED
Pset_BuildingElementProxyCommon - Reference: Bovedilla 1-7 (Paño 2); sets with these values: 2
Pset_ProvisionForVoid - Shape: Undefined
Name | In
Bovedilla 1-7 (Paño 2) | Depósito_
Bovedilla 1-7 (Paño 2) | PB | Pset_ProvisionForVoid - Width: 0.58 m; Height: 0.25 m; Depth: 0.25 m

# IfcBuildingElementProxy: Bovedilla 1-7 (Paño 3)
In: F1
Type - Description: Bovedilla de hormigón; PredefinedType: USERDEFINED
Pset_BuildingElementProxyCommon - Reference: Bovedilla 1-7 (Paño 3); sets with these values: 2
Pset_ProvisionForVoid - Shape: Undefined; Width: 0.58 m; Height: 0.25 m; Depth: 0.25 m

# IfcBuildingElementProxy: Bovedilla 1-7 (Paño 4)
In: F1
Type - Description: Bovedilla de hormigón; PredefinedType: USERDEFINED
Pset_BuildingElementProxyCommon - Reference: Bovedilla 1-7 (Paño 4); sets with these values: 2
Pset_ProvisionForVoid - Shape: Undefined; Width: 0.58 m; Height: 0.25 m; Depth: 0.25 m

# IfcBuildingElementProxy: Bovedilla 1-7 (Paño 6)
In: PB
Type - Description: Bovedilla de hormigón; PredefinedType: USERDEFINED
Pset_BuildingElementProxyCommon - Reference: Bovedilla 1-7 (Paño 6); sets with these values: 2
Pset_ProvisionForVoid - Shape: Undefined; Width: 0.58 m; Height: 0.25 m; Depth: 0.25 m

# IfcBuildingElementProxy: Bovedilla 1-8 (Paño 1)
In: Depósito_
Type - Description: Bovedilla de hormigón; PredefinedType: USERDEFINED
Pset_BuildingElementProxyCommon - Reference: Bovedilla 1-8 (Paño 1); sets with these values: 2
Pset_ProvisionForVoid - Shape: Undefined

# IfcBuildingElementProxy: Bovedilla 1-8 (Paño 13)
In: PB
Type - Description: Bovedilla de hormigón; PredefinedType: USERDEFINED
Pset_BuildingElementProxyCommon - Reference: Bovedilla 1-8 (Paño 13); sets with these values: 2
Pset_ProvisionForVoid - Shape: Undefined; Width: 0.58 m; Height: 0.25 m; Depth: 0.25 m

# IfcBuildingElementProxy: Bovedilla 1-8 (Paño 15)
In: PB
Type - Description: Bovedilla de hormigón; PredefinedType: USERDEFINED
Pset_BuildingElementProxyCommon - Reference: Bovedilla 1-8 (Paño 15); sets with these values: 2
Pset_ProvisionForVoid - Shape: Undefined; Width: 0.58 m; Height: 0.25 m; Depth: 0.25 m

# IfcBuildingElementProxy: Bovedilla 1-8 (Paño 2) (2)
Type - Description: Bovedilla de hormigón; PredefinedType: USERDEFINED
Pset_BuildingElementProxyCommon - Reference: Bovedilla 1-8 (Paño 2); sets with these values: 2
Pset_ProvisionForVoid - Shape: Undefined
Name | In
Bovedilla 1-8 (Paño 2) | Depósito_
Bovedilla 1-8 (Paño 2) | PB | Pset_ProvisionForVoid - Width: 0.58 m; Height: 0.25 m; Depth: 0.25 m

# IfcBuildingElementProxy: Bovedilla 1-8 (Paño 3)
In: F1
Type - Description: Bovedilla de hormigón; PredefinedType: USERDEFINED
Pset_BuildingElementProxyCommon - Reference: Bovedilla 1-8 (Paño 3); sets with these values: 2
Pset_ProvisionForVoid - Shape: Undefined; Width: 0.58 m; Height: 0.25 m; Depth: 0.25 m

# IfcBuildingElementProxy: Bovedilla 1-8 (Paño 4)
In: F1
Type - Description: Bovedilla de hormigón; PredefinedType: USERDEFINED
Pset_BuildingElementProxyCommon - Reference: Bovedilla 1-8 (Paño 4); sets with these values: 2
Pset_ProvisionForVoid - Shape: Undefined; Width: 0.58 m; Height: 0.25 m; Depth: 0.25 m

# IfcBuildingElementProxy: Bovedilla 1-8 (Paño 6)
In: PB
Type - Description: Bovedilla de hormigón; PredefinedType: USERDEFINED
Pset_BuildingElementProxyCommon - Reference: Bovedilla 1-8 (Paño 6); sets with these values: 2
Pset_ProvisionForVoid - Shape: Undefined; Width: 0.58 m; Height: 0.25 m; Depth: 0.25 m

# IfcBuildingElementProxy: Bovedilla 1-9 (Paño 1)
In: Depósito_
Type - Description: Bovedilla de hormigón; PredefinedType: USERDEFINED
Pset_BuildingElementProxyCommon - Reference: Bovedilla 1-9 (Paño 1); sets with these values: 2
Pset_ProvisionForVoid - Shape: Undefined

# IfcBuildingElementProxy: Bovedilla 1-9 (Paño 13)
In: PB
Type - Description: Bovedilla de hormigón; PredefinedType: USERDEFINED
Pset_BuildingElementProxyCommon - Reference: Bovedilla 1-9 (Paño 13); sets with these values: 2
Pset_ProvisionForVoid - Shape: Undefined; Width: 0.58 m; Height: 0.25 m; Depth: 0.25 m

# IfcBuildingElementProxy: Bovedilla 1-9 (Paño 15)
In: PB
Type - Description: Bovedilla de hormigón; PredefinedType: USERDEFINED
Pset_BuildingElementProxyCommon - Reference: Bovedilla 1-9 (Paño 15); sets with these values: 2
Pset_ProvisionForVoid - Shape: Undefined; Width: 0.58 m; Height: 0.25 m; Depth: 0.25 m

# IfcBuildingElementProxy: Bovedilla 1-9 (Paño 2) (2)
Type - Description: Bovedilla de hormigón; PredefinedType: USERDEFINED
Pset_BuildingElementProxyCommon - Reference: Bovedilla 1-9 (Paño 2); sets with these values: 2
Pset_ProvisionForVoid - Shape: Undefined
Name | In
Bovedilla 1-9 (Paño 2) | Depósito_
Bovedilla 1-9 (Paño 2) | PB | Pset_ProvisionForVoid - Width: 0.58 m; Height: 0.25 m; Depth: 0.25 m

# IfcBuildingElementProxy: Bovedilla 1-9 (Paño 3)
In: F1
Type - Description: Bovedilla de hormigón; PredefinedType: USERDEFINED
Pset_BuildingElementProxyCommon - Reference: Bovedilla 1-9 (Paño 3); sets with these values: 2
Pset_ProvisionForVoid - Shape: Undefined; Width: 0.58 m; Height: 0.25 m; Depth: 0.25 m

# IfcBuildingElementProxy: Bovedilla 1-9 (Paño 4)
In: F1
Type - Description: Bovedilla de hormigón; PredefinedType: USERDEFINED
Pset_BuildingElementProxyCommon - Reference: Bovedilla 1-9 (Paño 4); sets with these values: 2
Pset_ProvisionForVoid - Shape: Undefined; Width: 0.58 m; Height: 0.25 m; Depth: 0.25 m

# IfcBuildingElementProxy: Bovedilla 1-9 (Paño 6)
In: PB
Type - Description: Bovedilla de hormigón; PredefinedType: USERDEFINED
Pset_BuildingElementProxyCommon - Reference: Bovedilla 1-9 (Paño 6); sets with these values: 2
Pset_ProvisionForVoid - Shape: Undefined; Width: 0.58 m; Height: 0.25 m; Depth: 0.25 m

# IfcBuildingElementProxy: Bovedilla 10-1 (Paño 2)
In: PB
Type - Description: Bovedilla de hormigón; PredefinedType: USERDEFINED
Pset_BuildingElementProxyCommon - Reference: Bovedilla 10-1 (Paño 2); sets with these values: 2
Pset_ProvisionForVoid - Shape: Undefined; Width: 0.58 m; Height: 0.25 m; Depth: 0.25 m

# IfcBuildingElementProxy: Bovedilla 10-10 (Paño 2)
In: PB
Type - Description: Bovedilla de hormigón; PredefinedType: USERDEFINED
Pset_BuildingElementProxyCommon - Reference: Bovedilla 10-10 (Paño 2); sets with these values: 2
Pset_ProvisionForVoid - Shape: Undefined; Width: 0.58 m; Height: 0.25 m; Depth: 0.25 m

# IfcBuildingElementProxy: Bovedilla 10-11 (Paño 2)
In: PB
Type - Description: Bovedilla de hormigón; PredefinedType: USERDEFINED
Pset_BuildingElementProxyCommon - Reference: Bovedilla 10-11 (Paño 2); sets with these values: 2
Pset_ProvisionForVoid - Shape: Undefined; Width: 0.58 m; Height: 0.25 m; Depth: 0.25 m

# IfcBuildingElementProxy: Bovedilla 10-12 (Paño 2)
In: PB
Type - Description: Bovedilla de hormigón; PredefinedType: USERDEFINED
Pset_BuildingElementProxyCommon - Reference: Bovedilla 10-12 (Paño 2); sets with these values: 2
Pset_ProvisionForVoid - Shape: Undefined; Width: 0.58 m; Height: 0.25 m; Depth: 0.25 m

# IfcBuildingElementProxy: Bovedilla 10-13 (Paño 2)
In: PB
Type - Description: Bovedilla de hormigón; PredefinedType: USERDEFINED
Pset_BuildingElementProxyCommon - Reference: Bovedilla 10-13 (Paño 2); sets with these values: 2
Pset_ProvisionForVoid - Shape: Undefined; Width: 0.58 m; Height: 0.25 m; Depth: 0.25 m

# IfcBuildingElementProxy: Bovedilla 10-14 (Paño 2)
In: PB
Type - Description: Bovedilla de hormigón; PredefinedType: USERDEFINED
Pset_BuildingElementProxyCommon - Reference: Bovedilla 10-14 (Paño 2); sets with these values: 2
Pset_ProvisionForVoid - Shape: Undefined; Width: 0.58 m; Height: 0.25 m; Depth: 0.25 m

# IfcBuildingElementProxy: Bovedilla 10-2 (Paño 2)
In: PB
Type - Description: Bovedilla de hormigón; PredefinedType: USERDEFINED
Pset_BuildingElementProxyCommon - Reference: Bovedilla 10-2 (Paño 2); sets with these values: 2
Pset_ProvisionForVoid - Shape: Undefined; Width: 0.58 m; Height: 0.25 m; Depth: 0.25 m

# IfcBuildingElementProxy: Bovedilla 10-3 (Paño 2)
In: PB
Type - Description: Bovedilla de hormigón; PredefinedType: USERDEFINED
Pset_BuildingElementProxyCommon - Reference: Bovedilla 10-3 (Paño 2); sets with these values: 2
Pset_ProvisionForVoid - Shape: Undefined; Width: 0.58 m; Height: 0.25 m; Depth: 0.25 m

# IfcBuildingElementProxy: Bovedilla 10-4 (Paño 2)
In: PB
Type - Description: Bovedilla de hormigón; PredefinedType: USERDEFINED
Pset_BuildingElementProxyCommon - Reference: Bovedilla 10-4 (Paño 2); sets with these values: 2
Pset_ProvisionForVoid - Shape: Undefined; Width: 0.58 m; Height: 0.25 m; Depth: 0.25 m

# IfcBuildingElementProxy: Bovedilla 10-5 (Paño 2)
In: PB
Type - Description: Bovedilla de hormigón; PredefinedType: USERDEFINED
Pset_BuildingElementProxyCommon - Reference: Bovedilla 10-5 (Paño 2); sets with these values: 2
Pset_ProvisionForVoid - Shape: Undefined; Width: 0.58 m; Height: 0.25 m; Depth: 0.25 m

# IfcBuildingElementProxy: Bovedilla 10-6 (Paño 2)
In: PB
Type - Description: Bovedilla de hormigón; PredefinedType: USERDEFINED
Pset_BuildingElementProxyCommon - Reference: Bovedilla 10-6 (Paño 2); sets with these values: 2
Pset_ProvisionForVoid - Shape: Undefined; Width: 0.58 m; Height: 0.25 m; Depth: 0.25 m

# IfcBuildingElementProxy: Bovedilla 10-7 (Paño 2)
In: PB
Type - Description: Bovedilla de hormigón; PredefinedType: USERDEFINED
Pset_BuildingElementProxyCommon - Reference: Bovedilla 10-7 (Paño 2); sets with these values: 2
Pset_ProvisionForVoid - Shape: Undefined; Width: 0.58 m; Height: 0.25 m; Depth: 0.25 m

# IfcBuildingElementProxy: Bovedilla 10-8 (Paño 2)
In: PB
Type - Description: Bovedilla de hormigón; PredefinedType: USERDEFINED
Pset_BuildingElementProxyCommon - Reference: Bovedilla 10-8 (Paño 2); sets with these values: 2
Pset_ProvisionForVoid - Shape: Undefined; Width: 0.58 m; Height: 0.25 m; Depth: 0.25 m

# IfcBuildingElementProxy: Bovedilla 10-9 (Paño 2)
In: PB
Type - Description: Bovedilla de hormigón; PredefinedType: USERDEFINED
Pset_BuildingElementProxyCommon - Reference: Bovedilla 10-9 (Paño 2); sets with these values: 2
Pset_ProvisionForVoid - Shape: Undefined; Width: 0.58 m; Height: 0.25 m; Depth: 0.25 m

# IfcBuildingElementProxy: Bovedilla 11-1 (Paño 2)
In: PB
Type - Description: Bovedilla de hormigón; PredefinedType: USERDEFINED
Pset_BuildingElementProxyCommon - Reference: Bovedilla 11-1 (Paño 2); sets with these values: 2
Pset_ProvisionForVoid - Shape: Undefined; Width: 0.58 m; Height: 0.25 m; Depth: 0.25 m

# IfcBuildingElementProxy: Bovedilla 11-10 (Paño 2)
In: PB
Type - Description: Bovedilla de hormigón; PredefinedType: USERDEFINED
Pset_BuildingElementProxyCommon - Reference: Bovedilla 11-10 (Paño 2); sets with these values: 2
Pset_ProvisionForVoid - Shape: Undefined; Width: 0.58 m; Height: 0.25 m; Depth: 0.25 m

# IfcBuildingElementProxy: Bovedilla 11-11 (Paño 2)
In: PB
Type - Description: Bovedilla de hormigón; PredefinedType: USERDEFINED
Pset_BuildingElementProxyCommon - Reference: Bovedilla 11-11 (Paño 2); sets with these values: 2
Pset_ProvisionForVoid - Shape: Undefined; Width: 0.58 m; Height: 0.25 m; Depth: 0.25 m

# IfcBuildingElementProxy: Bovedilla 11-12 (Paño 2)
In: PB
Type - Description: Bovedilla de hormigón; PredefinedType: USERDEFINED
Pset_BuildingElementProxyCommon - Reference: Bovedilla 11-12 (Paño 2); sets with these values: 2
Pset_ProvisionForVoid - Shape: Undefined; Width: 0.58 m; Height: 0.25 m; Depth: 0.25 m

# IfcBuildingElementProxy: Bovedilla 11-13 (Paño 2)
In: PB
Type - Description: Bovedilla de hormigón; PredefinedType: USERDEFINED
Pset_BuildingElementProxyCommon - Reference: Bovedilla 11-13 (Paño 2); sets with these values: 2
Pset_ProvisionForVoid - Shape: Undefined; Width: 0.58 m; Height: 0.25 m; Depth: 0.25 m

# IfcBuildingElementProxy: Bovedilla 11-14 (Paño 2)
In: PB
Type - Description: Bovedilla de hormigón; PredefinedType: USERDEFINED
Pset_BuildingElementProxyCommon - Reference: Bovedilla 11-14 (Paño 2); sets with these values: 2
Pset_ProvisionForVoid - Shape: Undefined; Width: 0.58 m; Height: 0.25 m; Depth: 0.25 m

# IfcBuildingElementProxy: Bovedilla 11-2 (Paño 2)
In: PB
Type - Description: Bovedilla de hormigón; PredefinedType: USERDEFINED
Pset_BuildingElementProxyCommon - Reference: Bovedilla 11-2 (Paño 2); sets with these values: 2
Pset_ProvisionForVoid - Shape: Undefined; Width: 0.58 m; Height: 0.25 m; Depth: 0.25 m

# IfcBuildingElementProxy: Bovedilla 11-3 (Paño 2)
In: PB
Type - Description: Bovedilla de hormigón; PredefinedType: USERDEFINED
Pset_BuildingElementProxyCommon - Reference: Bovedilla 11-3 (Paño 2); sets with these values: 2
Pset_ProvisionForVoid - Shape: Undefined; Width: 0.58 m; Height: 0.25 m; Depth: 0.25 m

# IfcBuildingElementProxy: Bovedilla 11-4 (Paño 2)
In: PB
Type - Description: Bovedilla de hormigón; PredefinedType: USERDEFINED
Pset_BuildingElementProxyCommon - Reference: Bovedilla 11-4 (Paño 2); sets with these values: 2
Pset_ProvisionForVoid - Shape: Undefined; Width: 0.58 m; Height: 0.25 m; Depth: 0.25 m

# IfcBuildingElementProxy: Bovedilla 11-5 (Paño 2)
In: PB
Type - Description: Bovedilla de hormigón; PredefinedType: USERDEFINED
Pset_BuildingElementProxyCommon - Reference: Bovedilla 11-5 (Paño 2); sets with these values: 2
Pset_ProvisionForVoid - Shape: Undefined; Width: 0.58 m; Height: 0.25 m; Depth: 0.25 m

# IfcBuildingElementProxy: Bovedilla 11-6 (Paño 2)
In: PB
Type - Description: Bovedilla de hormigón; PredefinedType: USERDEFINED
Pset_BuildingElementProxyCommon - Reference: Bovedilla 11-6 (Paño 2); sets with these values: 2
Pset_ProvisionForVoid - Shape: Undefined; Width: 0.58 m; Height: 0.25 m; Depth: 0.25 m

# IfcBuildingElementProxy: Bovedilla 11-7 (Paño 2)
In: PB
Type - Description: Bovedilla de hormigón; PredefinedType: USERDEFINED
Pset_BuildingElementProxyCommon - Reference: Bovedilla 11-7 (Paño 2); sets with these values: 2
Pset_ProvisionForVoid - Shape: Undefined; Width: 0.58 m; Height: 0.25 m; Depth: 0.25 m

# IfcBuildingElementProxy: Bovedilla 11-8 (Paño 2)
In: PB
Type - Description: Bovedilla de hormigón; PredefinedType: USERDEFINED
Pset_BuildingElementProxyCommon - Reference: Bovedilla 11-8 (Paño 2); sets with these values: 2
Pset_ProvisionForVoid - Shape: Undefined; Width: 0.58 m; Height: 0.25 m; Depth: 0.25 m

# IfcBuildingElementProxy: Bovedilla 11-9 (Paño 2)
In: PB
Type - Description: Bovedilla de hormigón; PredefinedType: USERDEFINED
Pset_BuildingElementProxyCommon - Reference: Bovedilla 11-9 (Paño 2); sets with these values: 2
Pset_ProvisionForVoid - Shape: Undefined; Width: 0.58 m; Height: 0.25 m; Depth: 0.25 m

# IfcBuildingElementProxy: Bovedilla 12-1 (Paño 2)
In: PB
Type - Description: Bovedilla de hormigón; PredefinedType: USERDEFINED
Pset_BuildingElementProxyCommon - Reference: Bovedilla 12-1 (Paño 2); sets with these values: 2
Pset_ProvisionForVoid - Shape: Undefined; Width: 0.58 m; Height: 0.25 m; Depth: 0.25 m

# IfcBuildingElementProxy: Bovedilla 12-10 (Paño 2)
In: PB
Type - Description: Bovedilla de hormigón; PredefinedType: USERDEFINED
Pset_BuildingElementProxyCommon - Reference: Bovedilla 12-10 (Paño 2); sets with these values: 2
Pset_ProvisionForVoid - Shape: Undefined; Width: 0.58 m; Height: 0.25 m; Depth: 0.25 m

# IfcBuildingElementProxy: Bovedilla 12-11 (Paño 2)
In: PB
Type - Description: Bovedilla de hormigón; PredefinedType: USERDEFINED
Pset_BuildingElementProxyCommon - Reference: Bovedilla 12-11 (Paño 2); sets with these values: 2
Pset_ProvisionForVoid - Shape: Undefined; Width: 0.58 m; Height: 0.25 m; Depth: 0.25 m

# IfcBuildingElementProxy: Bovedilla 12-12 (Paño 2)
In: PB
Type - Description: Bovedilla de hormigón; PredefinedType: USERDEFINED
Pset_BuildingElementProxyCommon - Reference: Bovedilla 12-12 (Paño 2); sets with these values: 2
Pset_ProvisionForVoid - Shape: Undefined; Width: 0.58 m; Height: 0.25 m; Depth: 0.25 m

# IfcBuildingElementProxy: Bovedilla 12-13 (Paño 2)
In: PB
Type - Description: Bovedilla de hormigón; PredefinedType: USERDEFINED
Pset_BuildingElementProxyCommon - Reference: Bovedilla 12-13 (Paño 2); sets with these values: 2
Pset_ProvisionForVoid - Shape: Undefined; Width: 0.58 m; Height: 0.25 m; Depth: 0.25 m

# IfcBuildingElementProxy: Bovedilla 12-14 (Paño 2)
In: PB
Type - Description: Bovedilla de hormigón; PredefinedType: USERDEFINED
Pset_BuildingElementProxyCommon - Reference: Bovedilla 12-14 (Paño 2); sets with these values: 2
Pset_ProvisionForVoid - Shape: Undefined; Width: 0.58 m; Height: 0.25 m; Depth: 0.25 m

# IfcBuildingElementProxy: Bovedilla 12-2 (Paño 2)
In: PB
Type - Description: Bovedilla de hormigón; PredefinedType: USERDEFINED
Pset_BuildingElementProxyCommon - Reference: Bovedilla 12-2 (Paño 2); sets with these values: 2
Pset_ProvisionForVoid - Shape: Undefined; Width: 0.58 m; Height: 0.25 m; Depth: 0.25 m

# IfcBuildingElementProxy: Bovedilla 12-3 (Paño 2)
In: PB
Type - Description: Bovedilla de hormigón; PredefinedType: USERDEFINED
Pset_BuildingElementProxyCommon - Reference: Bovedilla 12-3 (Paño 2); sets with these values: 2
Pset_ProvisionForVoid - Shape: Undefined; Width: 0.58 m; Height: 0.25 m; Depth: 0.25 m

# IfcBuildingElementProxy: Bovedilla 12-4 (Paño 2)
In: PB
Type - Description: Bovedilla de hormigón; PredefinedType: USERDEFINED
Pset_BuildingElementProxyCommon - Reference: Bovedilla 12-4 (Paño 2); sets with these values: 2
Pset_ProvisionForVoid - Shape: Undefined; Width: 0.58 m; Height: 0.25 m; Depth: 0.25 m

# IfcBuildingElementProxy: Bovedilla 12-5 (Paño 2)
In: PB
Type - Description: Bovedilla de hormigón; PredefinedType: USERDEFINED
Pset_BuildingElementProxyCommon - Reference: Bovedilla 12-5 (Paño 2); sets with these values: 2
Pset_ProvisionForVoid - Shape: Undefined; Width: 0.58 m; Height: 0.25 m; Depth: 0.25 m

# IfcBuildingElementProxy: Bovedilla 12-6 (Paño 2)
In: PB
Type - Description: Bovedilla de hormigón; PredefinedType: USERDEFINED
Pset_BuildingElementProxyCommon - Reference: Bovedilla 12-6 (Paño 2); sets with these values: 2
Pset_ProvisionForVoid - Shape: Undefined; Width: 0.58 m; Height: 0.25 m; Depth: 0.25 m

# IfcBuildingElementProxy: Bovedilla 12-7 (Paño 2)
In: PB
Type - Description: Bovedilla de hormigón; PredefinedType: USERDEFINED
Pset_BuildingElementProxyCommon - Reference: Bovedilla 12-7 (Paño 2); sets with these values: 2
Pset_ProvisionForVoid - Shape: Undefined; Width: 0.58 m; Height: 0.25 m; Depth: 0.25 m

# IfcBuildingElementProxy: Bovedilla 12-8 (Paño 2)
In: PB
Type - Description: Bovedilla de hormigón; PredefinedType: USERDEFINED
Pset_BuildingElementProxyCommon - Reference: Bovedilla 12-8 (Paño 2); sets with these values: 2
Pset_ProvisionForVoid - Shape: Undefined; Width: 0.58 m; Height: 0.25 m; Depth: 0.25 m

# IfcBuildingElementProxy: Bovedilla 12-9 (Paño 2)
In: PB
Type - Description: Bovedilla de hormigón; PredefinedType: USERDEFINED
Pset_BuildingElementProxyCommon - Reference: Bovedilla 12-9 (Paño 2); sets with these values: 2
Pset_ProvisionForVoid - Shape: Undefined; Width: 0.58 m; Height: 0.25 m; Depth: 0.25 m

# IfcBuildingElementProxy: Bovedilla 13-1 (Paño 2)
In: PB
Type - Description: Bovedilla de hormigón; PredefinedType: USERDEFINED
Pset_BuildingElementProxyCommon - Reference: Bovedilla 13-1 (Paño 2); sets with these values: 2
Pset_ProvisionForVoid - Shape: Undefined; Width: 0.58 m; Height: 0.25 m; Depth: 0.25 m

# IfcBuildingElementProxy: Bovedilla 13-10 (Paño 2)
In: PB
Type - Description: Bovedilla de hormigón; PredefinedType: USERDEFINED
Pset_BuildingElementProxyCommon - Reference: Bovedilla 13-10 (Paño 2); sets with these values: 2
Pset_ProvisionForVoid - Shape: Undefined; Width: 0.58 m; Height: 0.25 m; Depth: 0.25 m

# IfcBuildingElementProxy: Bovedilla 13-11 (Paño 2)
In: PB
Type - Description: Bovedilla de hormigón; PredefinedType: USERDEFINED
Pset_BuildingElementProxyCommon - Reference: Bovedilla 13-11 (Paño 2); sets with these values: 2
Pset_ProvisionForVoid - Shape: Undefined; Width: 0.58 m; Height: 0.25 m; Depth: 0.25 m

# IfcBuildingElementProxy: Bovedilla 13-12 (Paño 2)
In: PB
Type - Description: Bovedilla de hormigón; PredefinedType: USERDEFINED
Pset_BuildingElementProxyCommon - Reference: Bovedilla 13-12 (Paño 2); sets with these values: 2
Pset_ProvisionForVoid - Shape: Undefined; Width: 0.58 m; Height: 0.25 m; Depth: 0.25 m

# IfcBuildingElementProxy: Bovedilla 13-13 (Paño 2)
In: PB
Type - Description: Bovedilla de hormigón; PredefinedType: USERDEFINED
Pset_BuildingElementProxyCommon - Reference: Bovedilla 13-13 (Paño 2); sets with these values: 2
Pset_ProvisionForVoid - Shape: Undefined; Width: 0.58 m; Height: 0.25 m; Depth: 0.25 m

# IfcBuildingElementProxy: Bovedilla 13-14 (Paño 2)
In: PB
Type - Description: Bovedilla de hormigón; PredefinedType: USERDEFINED
Pset_BuildingElementProxyCommon - Reference: Bovedilla 13-14 (Paño 2); sets with these values: 2
Pset_ProvisionForVoid - Shape: Undefined; Width: 0.58 m; Height: 0.25 m; Depth: 0.25 m

# IfcBuildingElementProxy: Bovedilla 13-2 (Paño 2)
In: PB
Type - Description: Bovedilla de hormigón; PredefinedType: USERDEFINED
Pset_BuildingElementProxyCommon - Reference: Bovedilla 13-2 (Paño 2); sets with these values: 2
Pset_ProvisionForVoid - Shape: Undefined; Width: 0.58 m; Height: 0.25 m; Depth: 0.25 m

# IfcBuildingElementProxy: Bovedilla 13-3 (Paño 2)
In: PB
Type - Description: Bovedilla de hormigón; PredefinedType: USERDEFINED
Pset_BuildingElementProxyCommon - Reference: Bovedilla 13-3 (Paño 2); sets with these values: 2
Pset_ProvisionForVoid - Shape: Undefined; Width: 0.58 m; Height: 0.25 m; Depth: 0.25 m

# IfcBuildingElementProxy: Bovedilla 13-4 (Paño 2)
In: PB
Type - Description: Bovedilla de hormigón; PredefinedType: USERDEFINED
Pset_BuildingElementProxyCommon - Reference: Bovedilla 13-4 (Paño 2); sets with these values: 2
Pset_ProvisionForVoid - Shape: Undefined; Width: 0.58 m; Height: 0.25 m; Depth: 0.25 m

# IfcBuildingElementProxy: Bovedilla 13-5 (Paño 2)
In: PB
Type - Description: Bovedilla de hormigón; PredefinedType: USERDEFINED
Pset_BuildingElementProxyCommon - Reference: Bovedilla 13-5 (Paño 2); sets with these values: 2
Pset_ProvisionForVoid - Shape: Undefined; Width: 0.58 m; Height: 0.25 m; Depth: 0.25 m

# IfcBuildingElementProxy: Bovedilla 13-6 (Paño 2)
In: PB
Type - Description: Bovedilla de hormigón; PredefinedType: USERDEFINED
Pset_BuildingElementProxyCommon - Reference: Bovedilla 13-6 (Paño 2); sets with these values: 2
Pset_ProvisionForVoid - Shape: Undefined; Width: 0.58 m; Height: 0.25 m; Depth: 0.25 m

# IfcBuildingElementProxy: Bovedilla 13-7 (Paño 2)
In: PB
Type - Description: Bovedilla de hormigón; PredefinedType: USERDEFINED
Pset_BuildingElementProxyCommon - Reference: Bovedilla 13-7 (Paño 2); sets with these values: 2
Pset_ProvisionForVoid - Shape: Undefined; Width: 0.58 m; Height: 0.25 m; Depth: 0.25 m

# IfcBuildingElementProxy: Bovedilla 13-8 (Paño 2)
In: PB
Type - Description: Bovedilla de hormigón; PredefinedType: USERDEFINED
Pset_BuildingElementProxyCommon - Reference: Bovedilla 13-8 (Paño 2); sets with these values: 2
Pset_ProvisionForVoid - Shape: Undefined; Width: 0.58 m; Height: 0.25 m; Depth: 0.25 m

# IfcBuildingElementProxy: Bovedilla 13-9 (Paño 2)
In: PB
Type - Description: Bovedilla de hormigón; PredefinedType: USERDEFINED
Pset_BuildingElementProxyCommon - Reference: Bovedilla 13-9 (Paño 2); sets with these values: 2
Pset_ProvisionForVoid - Shape: Undefined; Width: 0.58 m; Height: 0.25 m; Depth: 0.25 m

# IfcBuildingElementProxy: Bovedilla 14-1 (Paño 2)
In: PB
Type - Description: Bovedilla de hormigón; PredefinedType: USERDEFINED
Pset_BuildingElementProxyCommon - Reference: Bovedilla 14-1 (Paño 2); sets with these values: 2
Pset_ProvisionForVoid - Shape: Undefined; Width: 0.58 m; Height: 0.25 m; Depth: 0.25 m

# IfcBuildingElementProxy: Bovedilla 14-10 (Paño 2)
In: PB
Type - Description: Bovedilla de hormigón; PredefinedType: USERDEFINED
Pset_BuildingElementProxyCommon - Reference: Bovedilla 14-10 (Paño 2); sets with these values: 2
Pset_ProvisionForVoid - Shape: Undefined; Width: 0.58 m; Height: 0.25 m; Depth: 0.25 m

# IfcBuildingElementProxy: Bovedilla 14-11 (Paño 2)
In: PB
Type - Description: Bovedilla de hormigón; PredefinedType: USERDEFINED
Pset_BuildingElementProxyCommon - Reference: Bovedilla 14-11 (Paño 2); sets with these values: 2
Pset_ProvisionForVoid - Shape: Undefined; Width: 0.58 m; Height: 0.25 m; Depth: 0.25 m

# IfcBuildingElementProxy: Bovedilla 14-12 (Paño 2)
In: PB
Type - Description: Bovedilla de hormigón; PredefinedType: USERDEFINED
Pset_BuildingElementProxyCommon - Reference: Bovedilla 14-12 (Paño 2); sets with these values: 2
Pset_ProvisionForVoid - Shape: Undefined; Width: 0.58 m; Height: 0.25 m; Depth: 0.25 m

# IfcBuildingElementProxy: Bovedilla 14-13 (Paño 2)
In: PB
Type - Description: Bovedilla de hormigón; PredefinedType: USERDEFINED
Pset_BuildingElementProxyCommon - Reference: Bovedilla 14-13 (Paño 2); sets with these values: 2
Pset_ProvisionForVoid - Shape: Undefined; Width: 0.58 m; Height: 0.25 m; Depth: 0.25 m

# IfcBuildingElementProxy: Bovedilla 14-2 (Paño 2)
In: PB
Type - Description: Bovedilla de hormigón; PredefinedType: USERDEFINED
Pset_BuildingElementProxyCommon - Reference: Bovedilla 14-2 (Paño 2); sets with these values: 2
Pset_ProvisionForVoid - Shape: Undefined; Width: 0.58 m; Height: 0.25 m; Depth: 0.25 m

# IfcBuildingElementProxy: Bovedilla 14-3 (Paño 2)
In: PB
Type - Description: Bovedilla de hormigón; PredefinedType: USERDEFINED
Pset_BuildingElementProxyCommon - Reference: Bovedilla 14-3 (Paño 2); sets with these values: 2
Pset_ProvisionForVoid - Shape: Undefined; Width: 0.58 m; Height: 0.25 m; Depth: 0.25 m

# IfcBuildingElementProxy: Bovedilla 14-4 (Paño 2)
In: PB
Type - Description: Bovedilla de hormigón; PredefinedType: USERDEFINED
Pset_BuildingElementProxyCommon - Reference: Bovedilla 14-4 (Paño 2); sets with these values: 2
Pset_ProvisionForVoid - Shape: Undefined; Width: 0.58 m; Height: 0.25 m; Depth: 0.25 m

# IfcBuildingElementProxy: Bovedilla 14-5 (Paño 2)
In: PB
Type - Description: Bovedilla de hormigón; PredefinedType: USERDEFINED
Pset_BuildingElementProxyCommon - Reference: Bovedilla 14-5 (Paño 2); sets with these values: 2
Pset_ProvisionForVoid - Shape: Undefined; Width: 0.58 m; Height: 0.25 m; Depth: 0.25 m

# IfcBuildingElementProxy: Bovedilla 14-6 (Paño 2)
In: PB
Type - Description: Bovedilla de hormigón; PredefinedType: USERDEFINED
Pset_BuildingElementProxyCommon - Reference: Bovedilla 14-6 (Paño 2); sets with these values: 2
Pset_ProvisionForVoid - Shape: Undefined; Width: 0.58 m; Height: 0.25 m; Depth: 0.25 m

# IfcBuildingElementProxy: Bovedilla 14-7 (Paño 2)
In: PB
Type - Description: Bovedilla de hormigón; PredefinedType: USERDEFINED
Pset_BuildingElementProxyCommon - Reference: Bovedilla 14-7 (Paño 2); sets with these values: 2
Pset_ProvisionForVoid - Shape: Undefined; Width: 0.58 m; Height: 0.25 m; Depth: 0.25 m

# IfcBuildingElementProxy: Bovedilla 14-8 (Paño 2)
In: PB
Type - Description: Bovedilla de hormigón; PredefinedType: USERDEFINED
Pset_BuildingElementProxyCommon - Reference: Bovedilla 14-8 (Paño 2); sets with these values: 2
Pset_ProvisionForVoid - Shape: Undefined; Width: 0.58 m; Height: 0.25 m; Depth: 0.25 m

# IfcBuildingElementProxy: Bovedilla 14-9 (Paño 2)
In: PB
Type - Description: Bovedilla de hormigón; PredefinedType: USERDEFINED
Pset_BuildingElementProxyCommon - Reference: Bovedilla 14-9 (Paño 2); sets with these values: 2
Pset_ProvisionForVoid - Shape: Undefined; Width: 0.58 m; Height: 0.25 m; Depth: 0.25 m

# IfcBuildingElementProxy: Bovedilla 2-1 (Paño 1)
In: Depósito_
Type - Description: Bovedilla de hormigón; PredefinedType: USERDEFINED
Pset_BuildingElementProxyCommon - Reference: Bovedilla 2-1 (Paño 1); sets with these values: 2
Pset_ProvisionForVoid - Shape: Undefined

# IfcBuildingElementProxy: Bovedilla 2-1 (Paño 11)
In: PB
Type - Description: Bovedilla de hormigón; PredefinedType: USERDEFINED
Pset_BuildingElementProxyCommon - Reference: Bovedilla 2-1 (Paño 11); sets with these values: 2
Pset_ProvisionForVoid - Shape: Undefined; Width: 0.58 m; Height: 0.25 m; Depth: 0.25 m

# IfcBuildingElementProxy: Bovedilla 2-1 (Paño 13)
In: PB
Type - Description: Bovedilla de hormigón; PredefinedType: USERDEFINED
Pset_BuildingElementProxyCommon - Reference: Bovedilla 2-1 (Paño 13); sets with these values: 2
Pset_ProvisionForVoid - Shape: Undefined; Width: 0.58 m; Height: 0.25 m; Depth: 0.25 m

# IfcBuildingElementProxy: Bovedilla 2-1 (Paño 15)
In: PB
Type - Description: Bovedilla de hormigón; PredefinedType: USERDEFINED
Pset_BuildingElementProxyCommon - Reference: Bovedilla 2-1 (Paño 15); sets with these values: 2
Pset_ProvisionForVoid - Shape: Undefined; Width: 0.58 m; Height: 0.25 m; Depth: 0.25 m

# IfcBuildingElementProxy: Bovedilla 2-1 (Paño 2) (2)
Type - Description: Bovedilla de hormigón; PredefinedType: USERDEFINED
Pset_BuildingElementProxyCommon - Reference: Bovedilla 2-1 (Paño 2); sets with these values: 2
Pset_ProvisionForVoid - Shape: Undefined
Name | In
Bovedilla 2-1 (Paño 2) | Depósito_
Bovedilla 2-1 (Paño 2) | PB | Pset_ProvisionForVoid - Width: 0.58 m; Height: 0.25 m; Depth: 0.25 m

# IfcBuildingElementProxy: Bovedilla 2-1 (Paño 3)
In: F1
Type - Description: Bovedilla de hormigón; PredefinedType: USERDEFINED
Pset_BuildingElementProxyCommon - Reference: Bovedilla 2-1 (Paño 3); sets with these values: 2
Pset_ProvisionForVoid - Shape: Undefined; Width: 0.58 m; Height: 0.25 m; Depth: 0.25 m

# IfcBuildingElementProxy: Bovedilla 2-1 (Paño 4)
In: F1
Type - Description: Bovedilla de hormigón; PredefinedType: USERDEFINED
Pset_BuildingElementProxyCommon - Reference: Bovedilla 2-1 (Paño 4); sets with these values: 2
Pset_ProvisionForVoid - Shape: Undefined; Width: 0.58 m; Height: 0.25 m; Depth: 0.25 m

# IfcBuildingElementProxy: Bovedilla 2-1 (Paño 6)
In: PB
Type - Description: Bovedilla de hormigón; PredefinedType: USERDEFINED
Pset_BuildingElementProxyCommon - Reference: Bovedilla 2-1 (Paño 6); sets with these values: 2
Pset_ProvisionForVoid - Shape: Undefined; Width: 0.58 m; Height: 0.25 m; Depth: 0.25 m

# IfcBuildingElementProxy: Bovedilla 2-10 (Paño 1)
In: Depósito_
Type - Description: Bovedilla de hormigón; PredefinedType: USERDEFINED
Pset_BuildingElementProxyCommon - Reference: Bovedilla 2-10 (Paño 1); sets with these values: 2
Pset_ProvisionForVoid - Shape: Undefined

# IfcBuildingElementProxy: Bovedilla 2-10 (Paño 13)
In: PB
Type - Description: Bovedilla de hormigón; PredefinedType: USERDEFINED
Pset_BuildingElementProxyCommon - Reference: Bovedilla 2-10 (Paño 13); sets with these values: 2
Pset_ProvisionForVoid - Shape: Undefined; Width: 0.58 m; Height: 0.25 m; Depth: 0.25 m

# IfcBuildingElementProxy: Bovedilla 2-10 (Paño 15)
In: PB
Type - Description: Bovedilla de hormigón; PredefinedType: USERDEFINED
Pset_BuildingElementProxyCommon - Reference: Bovedilla 2-10 (Paño 15); sets with these values: 2
Pset_ProvisionForVoid - Shape: Undefined; Width: 0.58 m; Height: 0.25 m; Depth: 0.25 m

# IfcBuildingElementProxy: Bovedilla 2-10 (Paño 2) (2)
Type - Description: Bovedilla de hormigón; PredefinedType: USERDEFINED
Pset_BuildingElementProxyCommon - Reference: Bovedilla 2-10 (Paño 2); sets with these values: 2
Pset_ProvisionForVoid - Shape: Undefined
Name | In
Bovedilla 2-10 (Paño 2) | Depósito_
Bovedilla 2-10 (Paño 2) | PB | Pset_ProvisionForVoid - Width: 0.58 m; Height: 0.25 m; Depth: 0.25 m

# IfcBuildingElementProxy: Bovedilla 2-10 (Paño 3)
In: F1
Type - Description: Bovedilla de hormigón; PredefinedType: USERDEFINED
Pset_BuildingElementProxyCommon - Reference: Bovedilla 2-10 (Paño 3); sets with these values: 2
Pset_ProvisionForVoid - Shape: Undefined; Width: 0.58 m; Height: 0.25 m; Depth: 0.25 m

# IfcBuildingElementProxy: Bovedilla 2-10 (Paño 4)
In: F1
Type - Description: Bovedilla de hormigón; PredefinedType: USERDEFINED
Pset_BuildingElementProxyCommon - Reference: Bovedilla 2-10 (Paño 4); sets with these values: 2
Pset_ProvisionForVoid - Shape: Undefined; Width: 0.58 m; Height: 0.25 m; Depth: 0.25 m

# IfcBuildingElementProxy: Bovedilla 2-10 (Paño 6)
In: PB
Type - Description: Bovedilla de hormigón; PredefinedType: USERDEFINED
Pset_BuildingElementProxyCommon - Reference: Bovedilla 2-10 (Paño 6); sets with these values: 2
Pset_ProvisionForVoid - Shape: Undefined; Width: 0.58 m; Height: 0.25 m; Depth: 0.25 m

# IfcBuildingElementProxy: Bovedilla 2-11 (Paño 1)
In: Depósito_
Type - Description: Bovedilla de hormigón; PredefinedType: USERDEFINED
Pset_BuildingElementProxyCommon - Reference: Bovedilla 2-11 (Paño 1); sets with these values: 2
Pset_ProvisionForVoid - Shape: Undefined

# IfcBuildingElementProxy: Bovedilla 2-11 (Paño 13)
In: PB
Type - Description: Bovedilla de hormigón; PredefinedType: USERDEFINED
Pset_BuildingElementProxyCommon - Reference: Bovedilla 2-11 (Paño 13); sets with these values: 2
Pset_ProvisionForVoid - Shape: Undefined; Width: 0.58 m; Height: 0.25 m; Depth: 0.25 m

# IfcBuildingElementProxy: Bovedilla 2-11 (Paño 15)
In: PB
Type - Description: Bovedilla de hormigón; PredefinedType: USERDEFINED
Pset_BuildingElementProxyCommon - Reference: Bovedilla 2-11 (Paño 15); sets with these values: 2
Pset_ProvisionForVoid - Shape: Undefined; Width: 0.58 m; Height: 0.25 m; Depth: 0.25 m

# IfcBuildingElementProxy: Bovedilla 2-11 (Paño 2) (2)
Type - Description: Bovedilla de hormigón; PredefinedType: USERDEFINED
Pset_BuildingElementProxyCommon - Reference: Bovedilla 2-11 (Paño 2); sets with these values: 2
Pset_ProvisionForVoid - Shape: Undefined
Name | In
Bovedilla 2-11 (Paño 2) | Depósito_
Bovedilla 2-11 (Paño 2) | PB | Pset_ProvisionForVoid - Width: 0.58 m; Height: 0.25 m; Depth: 0.25 m

# IfcBuildingElementProxy: Bovedilla 2-11 (Paño 3)
In: F1
Type - Description: Bovedilla de hormigón; PredefinedType: USERDEFINED
Pset_BuildingElementProxyCommon - Reference: Bovedilla 2-11 (Paño 3); sets with these values: 2
Pset_ProvisionForVoid - Shape: Undefined; Width: 0.58 m; Height: 0.25 m; Depth: 0.25 m

# IfcBuildingElementProxy: Bovedilla 2-11 (Paño 4)
In: F1
Type - Description: Bovedilla de hormigón; PredefinedType: USERDEFINED
Pset_BuildingElementProxyCommon - Reference: Bovedilla 2-11 (Paño 4); sets with these values: 2
Pset_ProvisionForVoid - Shape: Undefined; Width: 0.58 m; Height: 0.25 m; Depth: 0.25 m

# IfcBuildingElementProxy: Bovedilla 2-11 (Paño 6)
In: PB
Type - Description: Bovedilla de hormigón; PredefinedType: USERDEFINED
Pset_BuildingElementProxyCommon - Reference: Bovedilla 2-11 (Paño 6); sets with these values: 2
Pset_ProvisionForVoid - Shape: Undefined; Width: 0.58 m; Height: 0.25 m; Depth: 0.25 m

# IfcBuildingElementProxy: Bovedilla 2-12 (Paño 1)
In: Depósito_
Type - Description: Bovedilla de hormigón; PredefinedType: USERDEFINED
Pset_BuildingElementProxyCommon - Reference: Bovedilla 2-12 (Paño 1); sets with these values: 2
Pset_ProvisionForVoid - Shape: Undefined

# IfcBuildingElementProxy: Bovedilla 2-12 (Paño 13)
In: PB
Type - Description: Bovedilla de hormigón; PredefinedType: USERDEFINED
Pset_BuildingElementProxyCommon - Reference: Bovedilla 2-12 (Paño 13); sets with these values: 2
Pset_ProvisionForVoid - Shape: Undefined; Width: 0.58 m; Height: 0.25 m; Depth: 0.25 m

# IfcBuildingElementProxy: Bovedilla 2-12 (Paño 15)
In: PB
Type - Description: Bovedilla de hormigón; PredefinedType: USERDEFINED
Pset_BuildingElementProxyCommon - Reference: Bovedilla 2-12 (Paño 15); sets with these values: 2
Pset_ProvisionForVoid - Shape: Undefined; Width: 0.58 m; Height: 0.25 m; Depth: 0.25 m

# IfcBuildingElementProxy: Bovedilla 2-12 (Paño 2) (2)
Type - Description: Bovedilla de hormigón; PredefinedType: USERDEFINED
Pset_BuildingElementProxyCommon - Reference: Bovedilla 2-12 (Paño 2); sets with these values: 2
Pset_ProvisionForVoid - Shape: Undefined
Name | In
Bovedilla 2-12 (Paño 2) | Depósito_
Bovedilla 2-12 (Paño 2) | PB | Pset_ProvisionForVoid - Width: 0.58 m; Height: 0.25 m; Depth: 0.25 m

# IfcBuildingElementProxy: Bovedilla 2-12 (Paño 3)
In: F1
Type - Description: Bovedilla de hormigón; PredefinedType: USERDEFINED
Pset_BuildingElementProxyCommon - Reference: Bovedilla 2-12 (Paño 3); sets with these values: 2
Pset_ProvisionForVoid - Shape: Undefined; Width: 0.58 m; Height: 0.25 m; Depth: 0.25 m

# IfcBuildingElementProxy: Bovedilla 2-12 (Paño 4)
In: F1
Type - Description: Bovedilla de hormigón; PredefinedType: USERDEFINED
Pset_BuildingElementProxyCommon - Reference: Bovedilla 2-12 (Paño 4); sets with these values: 2
Pset_ProvisionForVoid - Shape: Undefined; Width: 0.58 m; Height: 0.25 m; Depth: 0.25 m

# IfcBuildingElementProxy: Bovedilla 2-12 (Paño 6)
In: PB
Type - Description: Bovedilla de hormigón; PredefinedType: USERDEFINED
Pset_BuildingElementProxyCommon - Reference: Bovedilla 2-12 (Paño 6); sets with these values: 2
Pset_ProvisionForVoid - Shape: Undefined; Width: 0.58 m; Height: 0.25 m; Depth: 0.25 m

# IfcBuildingElementProxy: Bovedilla 2-13 (Paño 1)
In: Depósito_
Type - Description: Bovedilla de hormigón; PredefinedType: USERDEFINED
Pset_BuildingElementProxyCommon - Reference: Bovedilla 2-13 (Paño 1); sets with these values: 2
Pset_ProvisionForVoid - Shape: Undefined

# IfcBuildingElementProxy: Bovedilla 2-13 (Paño 13)
In: PB
Type - Description: Bovedilla de hormigón; PredefinedType: USERDEFINED
Pset_BuildingElementProxyCommon - Reference: Bovedilla 2-13 (Paño 13); sets with these values: 2
Pset_ProvisionForVoid - Shape: Undefined; Width: 0.58 m; Height: 0.25 m; Depth: 0.25 m

# IfcBuildingElementProxy: Bovedilla 2-13 (Paño 15)
In: PB
Type - Description: Bovedilla de hormigón; PredefinedType: USERDEFINED
Pset_BuildingElementProxyCommon - Reference: Bovedilla 2-13 (Paño 15); sets with these values: 2
Pset_ProvisionForVoid - Shape: Undefined; Width: 0.58 m; Height: 0.25 m; Depth: 0.25 m

# IfcBuildingElementProxy: Bovedilla 2-13 (Paño 2) (2)
Type - Description: Bovedilla de hormigón; PredefinedType: USERDEFINED
Pset_BuildingElementProxyCommon - Reference: Bovedilla 2-13 (Paño 2); sets with these values: 2
Pset_ProvisionForVoid - Shape: Undefined
Name | In
Bovedilla 2-13 (Paño 2) | Depósito_
Bovedilla 2-13 (Paño 2) | PB | Pset_ProvisionForVoid - Width: 0.58 m; Height: 0.25 m; Depth: 0.25 m

# IfcBuildingElementProxy: Bovedilla 2-13 (Paño 3)
In: F1
Type - Description: Bovedilla de hormigón; PredefinedType: USERDEFINED
Pset_BuildingElementProxyCommon - Reference: Bovedilla 2-13 (Paño 3); sets with these values: 2
Pset_ProvisionForVoid - Shape: Undefined; Width: 0.58 m; Height: 0.25 m; Depth: 0.25 m

# IfcBuildingElementProxy: Bovedilla 2-13 (Paño 4)
In: F1
Type - Description: Bovedilla de hormigón; PredefinedType: USERDEFINED
Pset_BuildingElementProxyCommon - Reference: Bovedilla 2-13 (Paño 4); sets with these values: 2
Pset_ProvisionForVoid - Shape: Undefined; Width: 0.58 m; Height: 0.25 m; Depth: 0.25 m

# IfcBuildingElementProxy: Bovedilla 2-13 (Paño 6)
In: PB
Type - Description: Bovedilla de hormigón; PredefinedType: USERDEFINED
Pset_BuildingElementProxyCommon - Reference: Bovedilla 2-13 (Paño 6); sets with these values: 2
Pset_ProvisionForVoid - Shape: Undefined; Width: 0.58 m; Height: 0.25 m; Depth: 0.25 m

# IfcBuildingElementProxy: Bovedilla 2-14 (Paño 13)
In: PB
Type - Description: Bovedilla de hormigón; PredefinedType: USERDEFINED
Pset_BuildingElementProxyCommon - Reference: Bovedilla 2-14 (Paño 13); sets with these values: 2
Pset_ProvisionForVoid - Shape: Undefined; Width: 0.58 m; Height: 0.25 m; Depth: 0.25 m

# IfcBuildingElementProxy: Bovedilla 2-14 (Paño 15)
In: PB
Type - Description: Bovedilla de hormigón; PredefinedType: USERDEFINED
Pset_BuildingElementProxyCommon - Reference: Bovedilla 2-14 (Paño 15); sets with these values: 2
Pset_ProvisionForVoid - Shape: Undefined; Width: 0.58 m; Height: 0.25 m; Depth: 0.25 m

# IfcBuildingElementProxy: Bovedilla 2-14 (Paño 2)
In: PB
Type - Description: Bovedilla de hormigón; PredefinedType: USERDEFINED
Pset_BuildingElementProxyCommon - Reference: Bovedilla 2-14 (Paño 2); sets with these values: 2
Pset_ProvisionForVoid - Shape: Undefined; Width: 0.58 m; Height: 0.25 m; Depth: 0.25 m

# IfcBuildingElementProxy: Bovedilla 2-14 (Paño 3)
In: F1
Type - Description: Bovedilla de hormigón; PredefinedType: USERDEFINED
Pset_BuildingElementProxyCommon - Reference: Bovedilla 2-14 (Paño 3); sets with these values: 2
Pset_ProvisionForVoid - Shape: Undefined; Width: 0.58 m; Height: 0.25 m; Depth: 0.25 m

# IfcBuildingElementProxy: Bovedilla 2-14 (Paño 4)
In: F1
Type - Description: Bovedilla de hormigón; PredefinedType: USERDEFINED
Pset_BuildingElementProxyCommon - Reference: Bovedilla 2-14 (Paño 4); sets with these values: 2
Pset_ProvisionForVoid - Shape: Undefined; Width: 0.58 m; Height: 0.25 m; Depth: 0.25 m

# IfcBuildingElementProxy: Bovedilla 2-14 (Paño 6)
In: PB
Type - Description: Bovedilla de hormigón; PredefinedType: USERDEFINED
Pset_BuildingElementProxyCommon - Reference: Bovedilla 2-14 (Paño 6); sets with these values: 2
Pset_ProvisionForVoid - Shape: Undefined; Width: 0.58 m; Height: 0.25 m; Depth: 0.25 m

# IfcBuildingElementProxy: Bovedilla 2-15 (Paño 13)
In: PB
Type - Description: Bovedilla de hormigón; PredefinedType: USERDEFINED
Pset_BuildingElementProxyCommon - Reference: Bovedilla 2-15 (Paño 13); sets with these values: 2
Pset_ProvisionForVoid - Shape: Undefined; Width: 0.58 m; Height: 0.25 m; Depth: 0.25 m

# IfcBuildingElementProxy: Bovedilla 2-15 (Paño 15)
In: PB
Type - Description: Bovedilla de hormigón; PredefinedType: USERDEFINED
Pset_BuildingElementProxyCommon - Reference: Bovedilla 2-15 (Paño 15); sets with these values: 2
Pset_ProvisionForVoid - Shape: Undefined; Width: 0.58 m; Height: 0.25 m; Depth: 0.25 m

# IfcBuildingElementProxy: Bovedilla 2-15 (Paño 3)
In: F1
Type - Description: Bovedilla de hormigón; PredefinedType: USERDEFINED
Pset_BuildingElementProxyCommon - Reference: Bovedilla 2-15 (Paño 3); sets with these values: 2
Pset_ProvisionForVoid - Shape: Undefined; Width: 0.58 m; Height: 0.25 m; Depth: 0.25 m

# IfcBuildingElementProxy: Bovedilla 2-15 (Paño 4)
In: F1
Type - Description: Bovedilla de hormigón; PredefinedType: USERDEFINED
Pset_BuildingElementProxyCommon - Reference: Bovedilla 2-15 (Paño 4); sets with these values: 2
Pset_ProvisionForVoid - Shape: Undefined; Width: 0.58 m; Height: 0.25 m; Depth: 0.25 m

# IfcBuildingElementProxy: Bovedilla 2-15 (Paño 6)
In: PB
Type - Description: Bovedilla de hormigón; PredefinedType: USERDEFINED
Pset_BuildingElementProxyCommon - Reference: Bovedilla 2-15 (Paño 6); sets with these values: 2
Pset_ProvisionForVoid - Shape: Undefined; Width: 0.58 m; Height: 0.25 m; Depth: 0.25 m

# IfcBuildingElementProxy: Bovedilla 2-16 (Paño 15)
In: PB
Type - Description: Bovedilla de hormigón; PredefinedType: USERDEFINED
Pset_BuildingElementProxyCommon - Reference: Bovedilla 2-16 (Paño 15); sets with these values: 2
Pset_ProvisionForVoid - Shape: Undefined; Width: 0.58 m; Height: 0.25 m; Depth: 0.25 m

# IfcBuildingElementProxy: Bovedilla 2-16 (Paño 3)
In: F1
Type - Description: Bovedilla de hormigón; PredefinedType: USERDEFINED
Pset_BuildingElementProxyCommon - Reference: Bovedilla 2-16 (Paño 3); sets with these values: 2
Pset_ProvisionForVoid - Shape: Undefined; Width: 0.58 m; Height: 0.25 m; Depth: 0.25 m

# IfcBuildingElementProxy: Bovedilla 2-16 (Paño 4)
In: F1
Type - Description: Bovedilla de hormigón; PredefinedType: USERDEFINED
Pset_BuildingElementProxyCommon - Reference: Bovedilla 2-16 (Paño 4); sets with these values: 2
Pset_ProvisionForVoid - Shape: Undefined; Width: 0.58 m; Height: 0.25 m; Depth: 0.25 m

# IfcBuildingElementProxy: Bovedilla 2-16 (Paño 6)
In: PB
Type - Description: Bovedilla de hormigón; PredefinedType: USERDEFINED
Pset_BuildingElementProxyCommon - Reference: Bovedilla 2-16 (Paño 6); sets with these values: 2
Pset_ProvisionForVoid - Shape: Undefined; Width: 0.58 m; Height: 0.25 m; Depth: 0.25 m

# IfcBuildingElementProxy: Bovedilla 2-17 (Paño 15)
In: PB
Type - Description: Bovedilla de hormigón; PredefinedType: USERDEFINED
Pset_BuildingElementProxyCommon - Reference: Bovedilla 2-17 (Paño 15); sets with these values: 2
Pset_ProvisionForVoid - Shape: Undefined; Width: 0.58 m; Height: 0.25 m; Depth: 0.25 m

# IfcBuildingElementProxy: Bovedilla 2-17 (Paño 6)
In: PB
Type - Description: Bovedilla de hormigón; PredefinedType: USERDEFINED
Pset_BuildingElementProxyCommon - Reference: Bovedilla 2-17 (Paño 6); sets with these values: 2
Pset_ProvisionForVoid - Shape: Undefined; Width: 0.58 m; Height: 0.25 m; Depth: 0.25 m

# IfcBuildingElementProxy: Bovedilla 2-18 (Paño 15)
In: PB
Type - Description: Bovedilla de hormigón; PredefinedType: USERDEFINED
Pset_BuildingElementProxyCommon - Reference: Bovedilla 2-18 (Paño 15); sets with these values: 2
Pset_ProvisionForVoid - Shape: Undefined; Width: 0.58 m; Height: 0.25 m; Depth: 0.25 m

# IfcBuildingElementProxy: Bovedilla 2-18 (Paño 6)
In: PB
Type - Description: Bovedilla de hormigón; PredefinedType: USERDEFINED
Pset_BuildingElementProxyCommon - Reference: Bovedilla 2-18 (Paño 6); sets with these values: 2
Pset_ProvisionForVoid - Shape: Undefined; Width: 0.58 m; Height: 0.25 m; Depth: 0.25 m

# IfcBuildingElementProxy: Bovedilla 2-19 (Paño 15)
In: PB
Type - Description: Bovedilla de hormigón; PredefinedType: USERDEFINED
Pset_BuildingElementProxyCommon - Reference: Bovedilla 2-19 (Paño 15); sets with these values: 2
Pset_ProvisionForVoid - Shape: Undefined; Width: 0.58 m; Height: 0.25 m; Depth: 0.25 m

# IfcBuildingElementProxy: Bovedilla 2-19 (Paño 6)
In: PB
Type - Description: Bovedilla de hormigón; PredefinedType: USERDEFINED
Pset_BuildingElementProxyCommon - Reference: Bovedilla 2-19 (Paño 6); sets with these values: 2
Pset_ProvisionForVoid - Shape: Undefined; Width: 0.58 m; Height: 0.25 m; Depth: 0.25 m

# IfcBuildingElementProxy: Bovedilla 2-2 (Paño 1)
In: Depósito_
Type - Description: Bovedilla de hormigón; PredefinedType: USERDEFINED
Pset_BuildingElementProxyCommon - Reference: Bovedilla 2-2 (Paño 1); sets with these values: 2
Pset_ProvisionForVoid - Shape: Undefined

# IfcBuildingElementProxy: Bovedilla 2-2 (Paño 11)
In: PB
Type - Description: Bovedilla de hormigón; PredefinedType: USERDEFINED
Pset_BuildingElementProxyCommon - Reference: Bovedilla 2-2 (Paño 11); sets with these values: 2
Pset_ProvisionForVoid - Shape: Undefined; Width: 0.58 m; Height: 0.25 m; Depth: 0.25 m

# IfcBuildingElementProxy: Bovedilla 2-2 (Paño 13)
In: PB
Type - Description: Bovedilla de hormigón; PredefinedType: USERDEFINED
Pset_BuildingElementProxyCommon - Reference: Bovedilla 2-2 (Paño 13); sets with these values: 2
Pset_ProvisionForVoid - Shape: Undefined; Width: 0.58 m; Height: 0.25 m; Depth: 0.25 m

# IfcBuildingElementProxy: Bovedilla 2-2 (Paño 15)
In: PB
Type - Description: Bovedilla de hormigón; PredefinedType: USERDEFINED
Pset_BuildingElementProxyCommon - Reference: Bovedilla 2-2 (Paño 15); sets with these values: 2
Pset_ProvisionForVoid - Shape: Undefined; Width: 0.58 m; Height: 0.25 m; Depth: 0.25 m

# IfcBuildingElementProxy: Bovedilla 2-2 (Paño 2) (2)
Type - Description: Bovedilla de hormigón; PredefinedType: USERDEFINED
Pset_BuildingElementProxyCommon - Reference: Bovedilla 2-2 (Paño 2); sets with these values: 2
Pset_ProvisionForVoid - Shape: Undefined
Name | In
Bovedilla 2-2 (Paño 2) | Depósito_
Bovedilla 2-2 (Paño 2) | PB | Pset_ProvisionForVoid - Width: 0.58 m; Height: 0.25 m; Depth: 0.25 m

# IfcBuildingElementProxy: Bovedilla 2-2 (Paño 3)
In: F1
Type - Description: Bovedilla de hormigón; PredefinedType: USERDEFINED
Pset_BuildingElementProxyCommon - Reference: Bovedilla 2-2 (Paño 3); sets with these values: 2
Pset_ProvisionForVoid - Shape: Undefined; Width: 0.58 m; Height: 0.25 m; Depth: 0.25 m

# IfcBuildingElementProxy: Bovedilla 2-2 (Paño 4)
In: F1
Type - Description: Bovedilla de hormigón; PredefinedType: USERDEFINED
Pset_BuildingElementProxyCommon - Reference: Bovedilla 2-2 (Paño 4); sets with these values: 2
Pset_ProvisionForVoid - Shape: Undefined; Width: 0.58 m; Height: 0.25 m; Depth: 0.25 m

# IfcBuildingElementProxy: Bovedilla 2-2 (Paño 6)
In: PB
Type - Description: Bovedilla de hormigón; PredefinedType: USERDEFINED
Pset_BuildingElementProxyCommon - Reference: Bovedilla 2-2 (Paño 6); sets with these values: 2
Pset_ProvisionForVoid - Shape: Undefined; Width: 0.58 m; Height: 0.25 m; Depth: 0.25 m

# IfcBuildingElementProxy: Bovedilla 2-20 (Paño 15)
In: PB
Type - Description: Bovedilla de hormigón; PredefinedType: USERDEFINED
Pset_BuildingElementProxyCommon - Reference: Bovedilla 2-20 (Paño 15); sets with these values: 2
Pset_ProvisionForVoid - Shape: Undefined; Width: 0.58 m; Height: 0.25 m; Depth: 0.25 m

# IfcBuildingElementProxy: Bovedilla 2-20 (Paño 6)
In: PB
Type - Description: Bovedilla de hormigón; PredefinedType: USERDEFINED
Pset_BuildingElementProxyCommon - Reference: Bovedilla 2-20 (Paño 6); sets with these values: 2
Pset_ProvisionForVoid - Shape: Undefined; Width: 0.58 m; Height: 0.25 m; Depth: 0.25 m

# IfcBuildingElementProxy: Bovedilla 2-21 (Paño 15)
In: PB
Type - Description: Bovedilla de hormigón; PredefinedType: USERDEFINED
Pset_BuildingElementProxyCommon - Reference: Bovedilla 2-21 (Paño 15); sets with these values: 2
Pset_ProvisionForVoid - Shape: Undefined; Width: 0.58 m; Height: 0.25 m; Depth: 0.25 m

# IfcBuildingElementProxy: Bovedilla 2-21 (Paño 6)
In: PB
Type - Description: Bovedilla de hormigón; PredefinedType: USERDEFINED
Pset_BuildingElementProxyCommon - Reference: Bovedilla 2-21 (Paño 6); sets with these values: 2
Pset_ProvisionForVoid - Shape: Undefined; Width: 0.58 m; Height: 0.25 m; Depth: 0.25 m

# IfcBuildingElementProxy: Bovedilla 2-22 (Paño 15)
In: PB
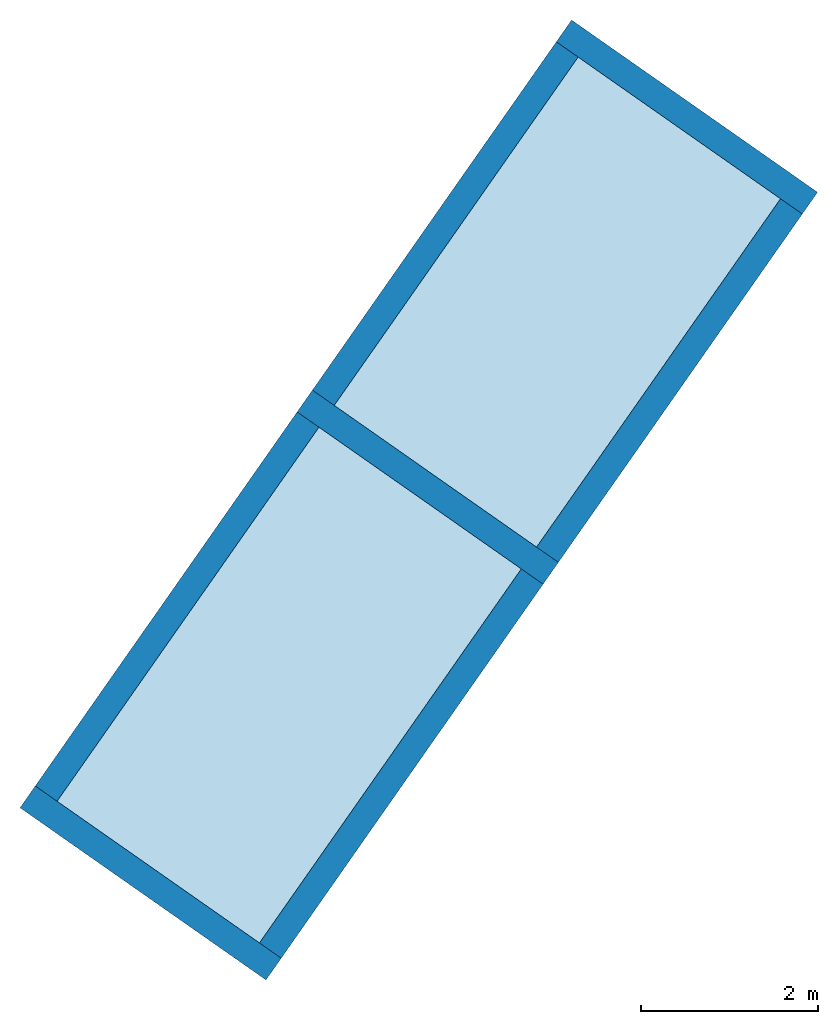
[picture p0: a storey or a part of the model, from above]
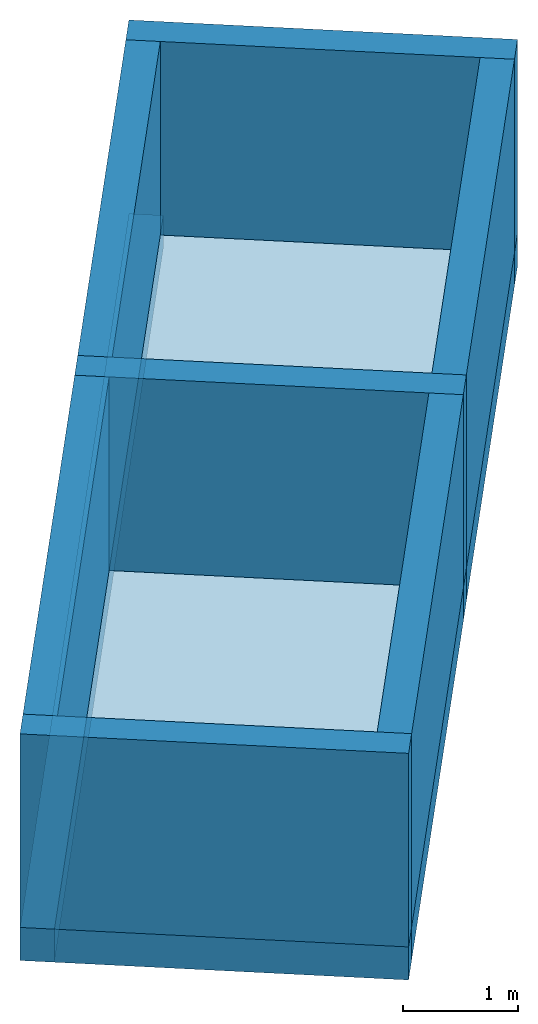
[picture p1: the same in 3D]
Properties of the parts of a building model (IFC2X3), part 3 of 5

# IfcBuildingElementProxy: Bovedilla 2-22 (Paño 15)
Type - Description: Bovedilla de hormigón; PredefinedType: USERDEFINED
Pset_BuildingElementProxyCommon - Reference: Bovedilla 2-22 (Paño 15); sets with these values: 2
Pset_ProvisionForVoid - Shape: Undefined; Width: 0.58 m; Height: 0.25 m; Depth: 0.25 m

# IfcBuildingElementProxy: Bovedilla 2-22 (Paño 6)
In: PB
Type - Description: Bovedilla de hormigón; PredefinedType: USERDEFINED
Pset_BuildingElementProxyCommon - Reference: Bovedilla 2-22 (Paño 6); sets with these values: 2
Pset_ProvisionForVoid - Shape: Undefined; Width: 0.58 m; Height: 0.25 m; Depth: 0.25 m

# IfcBuildingElementProxy: Bovedilla 2-23 (Paño 15)
In: PB
Type - Description: Bovedilla de hormigón; PredefinedType: USERDEFINED
Pset_BuildingElementProxyCommon - Reference: Bovedilla 2-23 (Paño 15); sets with these values: 2
Pset_ProvisionForVoid - Shape: Undefined; Width: 0.58 m; Height: 0.25 m; Depth: 0.25 m

# IfcBuildingElementProxy: Bovedilla 2-23 (Paño 6)
In: PB
Type - Description: Bovedilla de hormigón; PredefinedType: USERDEFINED
Pset_BuildingElementProxyCommon - Reference: Bovedilla 2-23 (Paño 6); sets with these values: 2
Pset_ProvisionForVoid - Shape: Undefined; Width: 0.58 m; Height: 0.25 m; Depth: 0.25 m

# IfcBuildingElementProxy: Bovedilla 2-24 (Paño 15)
In: PB
Type - Description: Bovedilla de hormigón; PredefinedType: USERDEFINED
Pset_BuildingElementProxyCommon - Reference: Bovedilla 2-24 (Paño 15); sets with these values: 2
Pset_ProvisionForVoid - Shape: Undefined; Width: 0.58 m; Height: 0.25 m; Depth: 0.25 m

# IfcBuildingElementProxy: Bovedilla 2-24 (Paño 6)
In: PB
Type - Description: Bovedilla de hormigón; PredefinedType: USERDEFINED
Pset_BuildingElementProxyCommon - Reference: Bovedilla 2-24 (Paño 6); sets with these values: 2
Pset_ProvisionForVoid - Shape: Undefined; Width: 0.58 m; Height: 0.25 m; Depth: 0.25 m

# IfcBuildingElementProxy: Bovedilla 2-25 (Paño 6)
In: PB
Type - Description: Bovedilla de hormigón; PredefinedType: USERDEFINED
Pset_BuildingElementProxyCommon - Reference: Bovedilla 2-25 (Paño 6); sets with these values: 2
Pset_ProvisionForVoid - Shape: Undefined; Width: 0.58 m; Height: 0.25 m; Depth: 0.25 m

# IfcBuildingElementProxy: Bovedilla 2-3 (Paño 1)
In: Depósito_
Type - Description: Bovedilla de hormigón; PredefinedType: USERDEFINED
Pset_BuildingElementProxyCommon - Reference: Bovedilla 2-3 (Paño 1); sets with these values: 2
Pset_ProvisionForVoid - Shape: Undefined

# IfcBuildingElementProxy: Bovedilla 2-3 (Paño 11)
In: PB
Type - Description: Bovedilla de hormigón; PredefinedType: USERDEFINED
Pset_BuildingElementProxyCommon - Reference: Bovedilla 2-3 (Paño 11); sets with these values: 2
Pset_ProvisionForVoid - Shape: Undefined; Width: 0.58 m; Height: 0.25 m; Depth: 0.25 m

# IfcBuildingElementProxy: Bovedilla 2-3 (Paño 13)
In: PB
Type - Description: Bovedilla de hormigón; PredefinedType: USERDEFINED
Pset_BuildingElementProxyCommon - Reference: Bovedilla 2-3 (Paño 13); sets with these values: 2
Pset_ProvisionForVoid - Shape: Undefined; Width: 0.58 m; Height: 0.25 m; Depth: 0.25 m

# IfcBuildingElementProxy: Bovedilla 2-3 (Paño 15)
In: PB
Type - Description: Bovedilla de hormigón; PredefinedType: USERDEFINED
Pset_BuildingElementProxyCommon - Reference: Bovedilla 2-3 (Paño 15); sets with these values: 2
Pset_ProvisionForVoid - Shape: Undefined; Width: 0.58 m; Height: 0.25 m; Depth: 0.25 m

# IfcBuildingElementProxy: Bovedilla 2-3 (Paño 2) (2)
Type - Description: Bovedilla de hormigón; PredefinedType: USERDEFINED
Pset_BuildingElementProxyCommon - Reference: Bovedilla 2-3 (Paño 2); sets with these values: 2
Pset_ProvisionForVoid - Shape: Undefined
Name | In
Bovedilla 2-3 (Paño 2) | Depósito_
Bovedilla 2-3 (Paño 2) | PB | Pset_ProvisionForVoid - Width: 0.58 m; Height: 0.25 m; Depth: 0.25 m

# IfcBuildingElementProxy: Bovedilla 2-3 (Paño 3)
In: F1
Type - Description: Bovedilla de hormigón; PredefinedType: USERDEFINED
Pset_BuildingElementProxyCommon - Reference: Bovedilla 2-3 (Paño 3); sets with these values: 2
Pset_ProvisionForVoid - Shape: Undefined; Width: 0.58 m; Height: 0.25 m; Depth: 0.25 m

# IfcBuildingElementProxy: Bovedilla 2-3 (Paño 4)
In: F1
Type - Description: Bovedilla de hormigón; PredefinedType: USERDEFINED
Pset_BuildingElementProxyCommon - Reference: Bovedilla 2-3 (Paño 4); sets with these values: 2
Pset_ProvisionForVoid - Shape: Undefined; Width: 0.58 m; Height: 0.25 m; Depth: 0.25 m

# IfcBuildingElementProxy: Bovedilla 2-3 (Paño 6)
In: PB
Type - Description: Bovedilla de hormigón; PredefinedType: USERDEFINED
Pset_BuildingElementProxyCommon - Reference: Bovedilla 2-3 (Paño 6); sets with these values: 2
Pset_ProvisionForVoid - Shape: Undefined; Width: 0.58 m; Height: 0.25 m; Depth: 0.25 m

# IfcBuildingElementProxy: Bovedilla 2-4 (Paño 1)
In: Depósito_
Type - Description: Bovedilla de hormigón; PredefinedType: USERDEFINED
Pset_BuildingElementProxyCommon - Reference: Bovedilla 2-4 (Paño 1); sets with these values: 2
Pset_ProvisionForVoid - Shape: Undefined

# IfcBuildingElementProxy: Bovedilla 2-4 (Paño 13)
In: PB
Type - Description: Bovedilla de hormigón; PredefinedType: USERDEFINED
Pset_BuildingElementProxyCommon - Reference: Bovedilla 2-4 (Paño 13); sets with these values: 2
Pset_ProvisionForVoid - Shape: Undefined; Width: 0.58 m; Height: 0.25 m; Depth: 0.25 m

# IfcBuildingElementProxy: Bovedilla 2-4 (Paño 15)
In: PB
Type - Description: Bovedilla de hormigón; PredefinedType: USERDEFINED
Pset_BuildingElementProxyCommon - Reference: Bovedilla 2-4 (Paño 15); sets with these values: 2
Pset_ProvisionForVoid - Shape: Undefined; Width: 0.58 m; Height: 0.25 m; Depth: 0.25 m

# IfcBuildingElementProxy: Bovedilla 2-4 (Paño 2) (2)
Type - Description: Bovedilla de hormigón; PredefinedType: USERDEFINED
Pset_BuildingElementProxyCommon - Reference: Bovedilla 2-4 (Paño 2); sets with these values: 2
Pset_ProvisionForVoid - Shape: Undefined
Name | In
Bovedilla 2-4 (Paño 2) | Depósito_
Bovedilla 2-4 (Paño 2) | PB | Pset_ProvisionForVoid - Width: 0.58 m; Height: 0.25 m; Depth: 0.25 m

# IfcBuildingElementProxy: Bovedilla 2-4 (Paño 3)
In: F1
Type - Description: Bovedilla de hormigón; PredefinedType: USERDEFINED
Pset_BuildingElementProxyCommon - Reference: Bovedilla 2-4 (Paño 3); sets with these values: 2
Pset_ProvisionForVoid - Shape: Undefined; Width: 0.58 m; Height: 0.25 m; Depth: 0.25 m

# IfcBuildingElementProxy: Bovedilla 2-4 (Paño 4)
In: F1
Type - Description: Bovedilla de hormigón; PredefinedType: USERDEFINED
Pset_BuildingElementProxyCommon - Reference: Bovedilla 2-4 (Paño 4); sets with these values: 2
Pset_ProvisionForVoid - Shape: Undefined; Width: 0.58 m; Height: 0.25 m; Depth: 0.25 m

# IfcBuildingElementProxy: Bovedilla 2-4 (Paño 6)
In: PB
Type - Description: Bovedilla de hormigón; PredefinedType: USERDEFINED
Pset_BuildingElementProxyCommon - Reference: Bovedilla 2-4 (Paño 6); sets with these values: 2
Pset_ProvisionForVoid - Shape: Undefined; Width: 0.58 m; Height: 0.25 m; Depth: 0.25 m

# IfcBuildingElementProxy: Bovedilla 2-5 (Paño 1)
In: Depósito_
Type - Description: Bovedilla de hormigón; PredefinedType: USERDEFINED
Pset_BuildingElementProxyCommon - Reference: Bovedilla 2-5 (Paño 1); sets with these values: 2
Pset_ProvisionForVoid - Shape: Undefined

# IfcBuildingElementProxy: Bovedilla 2-5 (Paño 13)
In: PB
Type - Description: Bovedilla de hormigón; PredefinedType: USERDEFINED
Pset_BuildingElementProxyCommon - Reference: Bovedilla 2-5 (Paño 13); sets with these values: 2
Pset_ProvisionForVoid - Shape: Undefined; Width: 0.58 m; Height: 0.25 m; Depth: 0.25 m

# IfcBuildingElementProxy: Bovedilla 2-5 (Paño 15)
In: PB
Type - Description: Bovedilla de hormigón; PredefinedType: USERDEFINED
Pset_BuildingElementProxyCommon - Reference: Bovedilla 2-5 (Paño 15); sets with these values: 2
Pset_ProvisionForVoid - Shape: Undefined; Width: 0.58 m; Height: 0.25 m; Depth: 0.25 m

# IfcBuildingElementProxy: Bovedilla 2-5 (Paño 2) (2)
Type - Description: Bovedilla de hormigón; PredefinedType: USERDEFINED
Pset_BuildingElementProxyCommon - Reference: Bovedilla 2-5 (Paño 2); sets with these values: 2
Pset_ProvisionForVoid - Shape: Undefined
Name | In
Bovedilla 2-5 (Paño 2) | Depósito_
Bovedilla 2-5 (Paño 2) | PB | Pset_ProvisionForVoid - Width: 0.58 m; Height: 0.25 m; Depth: 0.25 m

# IfcBuildingElementProxy: Bovedilla 2-5 (Paño 3)
In: F1
Type - Description: Bovedilla de hormigón; PredefinedType: USERDEFINED
Pset_BuildingElementProxyCommon - Reference: Bovedilla 2-5 (Paño 3); sets with these values: 2
Pset_ProvisionForVoid - Shape: Undefined; Width: 0.58 m; Height: 0.25 m; Depth: 0.25 m

# IfcBuildingElementProxy: Bovedilla 2-5 (Paño 4)
In: F1
Type - Description: Bovedilla de hormigón; PredefinedType: USERDEFINED
Pset_BuildingElementProxyCommon - Reference: Bovedilla 2-5 (Paño 4); sets with these values: 2
Pset_ProvisionForVoid - Shape: Undefined; Width: 0.58 m; Height: 0.25 m; Depth: 0.25 m

# IfcBuildingElementProxy: Bovedilla 2-5 (Paño 6)
In: PB
Type - Description: Bovedilla de hormigón; PredefinedType: USERDEFINED
Pset_BuildingElementProxyCommon - Reference: Bovedilla 2-5 (Paño 6); sets with these values: 2
Pset_ProvisionForVoid - Shape: Undefined; Width: 0.58 m; Height: 0.25 m; Depth: 0.25 m

# IfcBuildingElementProxy: Bovedilla 2-6 (Paño 1)
In: Depósito_
Type - Description: Bovedilla de hormigón; PredefinedType: USERDEFINED
Pset_BuildingElementProxyCommon - Reference: Bovedilla 2-6 (Paño 1); sets with these values: 2
Pset_ProvisionForVoid - Shape: Undefined

# IfcBuildingElementProxy: Bovedilla 2-6 (Paño 13)
In: PB
Type - Description: Bovedilla de hormigón; PredefinedType: USERDEFINED
Pset_BuildingElementProxyCommon - Reference: Bovedilla 2-6 (Paño 13); sets with these values: 2
Pset_ProvisionForVoid - Shape: Undefined; Width: 0.58 m; Height: 0.25 m; Depth: 0.25 m

# IfcBuildingElementProxy: Bovedilla 2-6 (Paño 15)
In: PB
Type - Description: Bovedilla de hormigón; PredefinedType: USERDEFINED
Pset_BuildingElementProxyCommon - Reference: Bovedilla 2-6 (Paño 15); sets with these values: 2
Pset_ProvisionForVoid - Shape: Undefined; Width: 0.58 m; Height: 0.25 m; Depth: 0.25 m

# IfcBuildingElementProxy: Bovedilla 2-6 (Paño 2) (2)
Type - Description: Bovedilla de hormigón; PredefinedType: USERDEFINED
Pset_BuildingElementProxyCommon - Reference: Bovedilla 2-6 (Paño 2); sets with these values: 2
Pset_ProvisionForVoid - Shape: Undefined
Name | In
Bovedilla 2-6 (Paño 2) | Depósito_
Bovedilla 2-6 (Paño 2) | PB | Pset_ProvisionForVoid - Width: 0.58 m; Height: 0.25 m; Depth: 0.25 m

# IfcBuildingElementProxy: Bovedilla 2-6 (Paño 3)
In: F1
Type - Description: Bovedilla de hormigón; PredefinedType: USERDEFINED
Pset_BuildingElementProxyCommon - Reference: Bovedilla 2-6 (Paño 3); sets with these values: 2
Pset_ProvisionForVoid - Shape: Undefined; Width: 0.58 m; Height: 0.25 m; Depth: 0.25 m

# IfcBuildingElementProxy: Bovedilla 2-6 (Paño 4)
In: F1
Type - Description: Bovedilla de hormigón; PredefinedType: USERDEFINED
Pset_BuildingElementProxyCommon - Reference: Bovedilla 2-6 (Paño 4); sets with these values: 2
Pset_ProvisionForVoid - Shape: Undefined; Width: 0.58 m; Height: 0.25 m; Depth: 0.25 m

# IfcBuildingElementProxy: Bovedilla 2-6 (Paño 6)
In: PB
Type - Description: Bovedilla de hormigón; PredefinedType: USERDEFINED
Pset_BuildingElementProxyCommon - Reference: Bovedilla 2-6 (Paño 6); sets with these values: 2
Pset_ProvisionForVoid - Shape: Undefined; Width: 0.58 m; Height: 0.25 m; Depth: 0.25 m

# IfcBuildingElementProxy: Bovedilla 2-7 (Paño 1)
In: Depósito_
Type - Description: Bovedilla de hormigón; PredefinedType: USERDEFINED
Pset_BuildingElementProxyCommon - Reference: Bovedilla 2-7 (Paño 1); sets with these values: 2
Pset_ProvisionForVoid - Shape: Undefined

# IfcBuildingElementProxy: Bovedilla 2-7 (Paño 13)
In: PB
Type - Description: Bovedilla de hormigón; PredefinedType: USERDEFINED
Pset_BuildingElementProxyCommon - Reference: Bovedilla 2-7 (Paño 13); sets with these values: 2
Pset_ProvisionForVoid - Shape: Undefined; Width: 0.58 m; Height: 0.25 m; Depth: 0.25 m

# IfcBuildingElementProxy: Bovedilla 2-7 (Paño 15)
In: PB
Type - Description: Bovedilla de hormigón; PredefinedType: USERDEFINED
Pset_BuildingElementProxyCommon - Reference: Bovedilla 2-7 (Paño 15); sets with these values: 2
Pset_ProvisionForVoid - Shape: Undefined; Width: 0.58 m; Height: 0.25 m; Depth: 0.25 m

# IfcBuildingElementProxy: Bovedilla 2-7 (Paño 2) (2)
Type - Description: Bovedilla de hormigón; PredefinedType: USERDEFINED
Pset_BuildingElementProxyCommon - Reference: Bovedilla 2-7 (Paño 2); sets with these values: 2
Pset_ProvisionForVoid - Shape: Undefined
Name | In
Bovedilla 2-7 (Paño 2) | Depósito_
Bovedilla 2-7 (Paño 2) | PB | Pset_ProvisionForVoid - Width: 0.58 m; Height: 0.25 m; Depth: 0.25 m

# IfcBuildingElementProxy: Bovedilla 2-7 (Paño 3)
In: F1
Type - Description: Bovedilla de hormigón; PredefinedType: USERDEFINED
Pset_BuildingElementProxyCommon - Reference: Bovedilla 2-7 (Paño 3); sets with these values: 2
Pset_ProvisionForVoid - Shape: Undefined; Width: 0.58 m; Height: 0.25 m; Depth: 0.25 m

# IfcBuildingElementProxy: Bovedilla 2-7 (Paño 4)
In: F1
Type - Description: Bovedilla de hormigón; PredefinedType: USERDEFINED
Pset_BuildingElementProxyCommon - Reference: Bovedilla 2-7 (Paño 4); sets with these values: 2
Pset_ProvisionForVoid - Shape: Undefined; Width: 0.58 m; Height: 0.25 m; Depth: 0.25 m

# IfcBuildingElementProxy: Bovedilla 2-7 (Paño 6)
In: PB
Type - Description: Bovedilla de hormigón; PredefinedType: USERDEFINED
Pset_BuildingElementProxyCommon - Reference: Bovedilla 2-7 (Paño 6); sets with these values: 2
Pset_ProvisionForVoid - Shape: Undefined; Width: 0.58 m; Height: 0.25 m; Depth: 0.25 m

# IfcBuildingElementProxy: Bovedilla 2-8 (Paño 1)
In: Depósito_
Type - Description: Bovedilla de hormigón; PredefinedType: USERDEFINED
Pset_BuildingElementProxyCommon - Reference: Bovedilla 2-8 (Paño 1); sets with these values: 2
Pset_ProvisionForVoid - Shape: Undefined

# IfcBuildingElementProxy: Bovedilla 2-8 (Paño 13)
In: PB
Type - Description: Bovedilla de hormigón; PredefinedType: USERDEFINED
Pset_BuildingElementProxyCommon - Reference: Bovedilla 2-8 (Paño 13); sets with these values: 2
Pset_ProvisionForVoid - Shape: Undefined; Width: 0.58 m; Height: 0.25 m; Depth: 0.25 m

# IfcBuildingElementProxy: Bovedilla 2-8 (Paño 15)
In: PB
Type - Description: Bovedilla de hormigón; PredefinedType: USERDEFINED
Pset_BuildingElementProxyCommon - Reference: Bovedilla 2-8 (Paño 15); sets with these values: 2
Pset_ProvisionForVoid - Shape: Undefined; Width: 0.58 m; Height: 0.25 m; Depth: 0.25 m

# IfcBuildingElementProxy: Bovedilla 2-8 (Paño 2) (2)
Type - Description: Bovedilla de hormigón; PredefinedType: USERDEFINED
Pset_BuildingElementProxyCommon - Reference: Bovedilla 2-8 (Paño 2); sets with these values: 2
Pset_ProvisionForVoid - Shape: Undefined
Name | In
Bovedilla 2-8 (Paño 2) | Depósito_
Bovedilla 2-8 (Paño 2) | PB | Pset_ProvisionForVoid - Width: 0.58 m; Height: 0.25 m; Depth: 0.25 m

# IfcBuildingElementProxy: Bovedilla 2-8 (Paño 3)
In: F1
Type - Description: Bovedilla de hormigón; PredefinedType: USERDEFINED
Pset_BuildingElementProxyCommon - Reference: Bovedilla 2-8 (Paño 3); sets with these values: 2
Pset_ProvisionForVoid - Shape: Undefined; Width: 0.58 m; Height: 0.25 m; Depth: 0.25 m

# IfcBuildingElementProxy: Bovedilla 2-8 (Paño 4)
In: F1
Type - Description: Bovedilla de hormigón; PredefinedType: USERDEFINED
Pset_BuildingElementProxyCommon - Reference: Bovedilla 2-8 (Paño 4); sets with these values: 2
Pset_ProvisionForVoid - Shape: Undefined; Width: 0.58 m; Height: 0.25 m; Depth: 0.25 m

# IfcBuildingElementProxy: Bovedilla 2-8 (Paño 6)
In: PB
Type - Description: Bovedilla de hormigón; PredefinedType: USERDEFINED
Pset_BuildingElementProxyCommon - Reference: Bovedilla 2-8 (Paño 6); sets with these values: 2
Pset_ProvisionForVoid - Shape: Undefined; Width: 0.58 m; Height: 0.25 m; Depth: 0.25 m

# IfcBuildingElementProxy: Bovedilla 2-9 (Paño 1)
In: Depósito_
Type - Description: Bovedilla de hormigón; PredefinedType: USERDEFINED
Pset_BuildingElementProxyCommon - Reference: Bovedilla 2-9 (Paño 1); sets with these values: 2
Pset_ProvisionForVoid - Shape: Undefined

# IfcBuildingElementProxy: Bovedilla 2-9 (Paño 13)
In: PB
Type - Description: Bovedilla de hormigón; PredefinedType: USERDEFINED
Pset_BuildingElementProxyCommon - Reference: Bovedilla 2-9 (Paño 13); sets with these values: 2
Pset_ProvisionForVoid - Shape: Undefined; Width: 0.58 m; Height: 0.25 m; Depth: 0.25 m

# IfcBuildingElementProxy: Bovedilla 2-9 (Paño 15)
In: PB
Type - Description: Bovedilla de hormigón; PredefinedType: USERDEFINED
Pset_BuildingElementProxyCommon - Reference: Bovedilla 2-9 (Paño 15); sets with these values: 2
Pset_ProvisionForVoid - Shape: Undefined; Width: 0.58 m; Height: 0.25 m; Depth: 0.25 m

# IfcBuildingElementProxy: Bovedilla 2-9 (Paño 2) (2)
Type - Description: Bovedilla de hormigón; PredefinedType: USERDEFINED
Pset_BuildingElementProxyCommon - Reference: Bovedilla 2-9 (Paño 2); sets with these values: 2
Pset_ProvisionForVoid - Shape: Undefined
Name | In
Bovedilla 2-9 (Paño 2) | Depósito_
Bovedilla 2-9 (Paño 2) | PB | Pset_ProvisionForVoid - Width: 0.58 m; Height: 0.25 m; Depth: 0.25 m

# IfcBuildingElementProxy: Bovedilla 2-9 (Paño 3)
In: F1
Type - Description: Bovedilla de hormigón; PredefinedType: USERDEFINED
Pset_BuildingElementProxyCommon - Reference: Bovedilla 2-9 (Paño 3); sets with these values: 2
Pset_ProvisionForVoid - Shape: Undefined; Width: 0.58 m; Height: 0.25 m; Depth: 0.25 m

# IfcBuildingElementProxy: Bovedilla 2-9 (Paño 4)
In: F1
Type - Description: Bovedilla de hormigón; PredefinedType: USERDEFINED
Pset_BuildingElementProxyCommon - Reference: Bovedilla 2-9 (Paño 4); sets with these values: 2
Pset_ProvisionForVoid - Shape: Undefined; Width: 0.58 m; Height: 0.25 m; Depth: 0.25 m

# IfcBuildingElementProxy: Bovedilla 2-9 (Paño 6)
In: PB
Type - Description: Bovedilla de hormigón; PredefinedType: USERDEFINED
Pset_BuildingElementProxyCommon - Reference: Bovedilla 2-9 (Paño 6); sets with these values: 2
Pset_ProvisionForVoid - Shape: Undefined; Width: 0.58 m; Height: 0.25 m; Depth: 0.25 m

# IfcBuildingElementProxy: Bovedilla 3-1 (Paño 1)
In: Depósito_
Type - Description: Bovedilla de hormigón; PredefinedType: USERDEFINED
Pset_BuildingElementProxyCommon - Reference: Bovedilla 3-1 (Paño 1); sets with these values: 2
Pset_ProvisionForVoid - Shape: Undefined

# IfcBuildingElementProxy: Bovedilla 3-1 (Paño 2) (2)
Type - Description: Bovedilla de hormigón; PredefinedType: USERDEFINED
Pset_BuildingElementProxyCommon - Reference: Bovedilla 3-1 (Paño 2); sets with these values: 2
Pset_ProvisionForVoid - Shape: Undefined
Name | In
Bovedilla 3-1 (Paño 2) | Depósito_
Bovedilla 3-1 (Paño 2) | PB | Pset_ProvisionForVoid - Width: 0.58 m; Height: 0.25 m; Depth: 0.25 m

# IfcBuildingElementProxy: Bovedilla 3-1 (Paño 3)
In: F1
Type - Description: Bovedilla de hormigón; PredefinedType: USERDEFINED
Pset_BuildingElementProxyCommon - Reference: Bovedilla 3-1 (Paño 3); sets with these values: 2
Pset_ProvisionForVoid - Shape: Undefined; Width: 0.58 m; Height: 0.25 m; Depth: 0.25 m

# IfcBuildingElementProxy: Bovedilla 3-1 (Paño 4)
In: F1
Type - Description: Bovedilla de hormigón; PredefinedType: USERDEFINED
Pset_BuildingElementProxyCommon - Reference: Bovedilla 3-1 (Paño 4); sets with these values: 2
Pset_ProvisionForVoid - Shape: Undefined; Width: 0.58 m; Height: 0.25 m; Depth: 0.25 m

# IfcBuildingElementProxy: Bovedilla 3-1 (Paño 6)
In: PB
Type - Description: Bovedilla de hormigón; PredefinedType: USERDEFINED
Pset_BuildingElementProxyCommon - Reference: Bovedilla 3-1 (Paño 6); sets with these values: 2
Pset_ProvisionForVoid - Shape: Undefined; Width: 0.58 m; Height: 0.25 m; Depth: 0.25 m

# IfcBuildingElementProxy: Bovedilla 3-10 (Paño 1)
In: Depósito_
Type - Description: Bovedilla de hormigón; PredefinedType: USERDEFINED
Pset_BuildingElementProxyCommon - Reference: Bovedilla 3-10 (Paño 1); sets with these values: 2
Pset_ProvisionForVoid - Shape: Undefined

# IfcBuildingElementProxy: Bovedilla 3-10 (Paño 2) (2)
Type - Description: Bovedilla de hormigón; PredefinedType: USERDEFINED
Pset_BuildingElementProxyCommon - Reference: Bovedilla 3-10 (Paño 2); sets with these values: 2
Pset_ProvisionForVoid - Shape: Undefined
Name | In
Bovedilla 3-10 (Paño 2) | Depósito_
Bovedilla 3-10 (Paño 2) | PB | Pset_ProvisionForVoid - Width: 0.58 m; Height: 0.25 m; Depth: 0.25 m

# IfcBuildingElementProxy: Bovedilla 3-10 (Paño 3)
In: F1
Type - Description: Bovedilla de hormigón; PredefinedType: USERDEFINED
Pset_BuildingElementProxyCommon - Reference: Bovedilla 3-10 (Paño 3); sets with these values: 2
Pset_ProvisionForVoid - Shape: Undefined; Width: 0.58 m; Height: 0.25 m; Depth: 0.25 m

# IfcBuildingElementProxy: Bovedilla 3-10 (Paño 4)
In: F1
Type - Description: Bovedilla de hormigón; PredefinedType: USERDEFINED
Pset_BuildingElementProxyCommon - Reference: Bovedilla 3-10 (Paño 4); sets with these values: 2
Pset_ProvisionForVoid - Shape: Undefined; Width: 0.58 m; Height: 0.25 m; Depth: 0.25 m

# IfcBuildingElementProxy: Bovedilla 3-10 (Paño 6)
In: PB
Type - Description: Bovedilla de hormigón; PredefinedType: USERDEFINED
Pset_BuildingElementProxyCommon - Reference: Bovedilla 3-10 (Paño 6); sets with these values: 2
Pset_ProvisionForVoid - Shape: Undefined; Width: 0.58 m; Height: 0.25 m; Depth: 0.25 m

# IfcBuildingElementProxy: Bovedilla 3-11 (Paño 1)
In: Depósito_
Type - Description: Bovedilla de hormigón; PredefinedType: USERDEFINED
Pset_BuildingElementProxyCommon - Reference: Bovedilla 3-11 (Paño 1); sets with these values: 2
Pset_ProvisionForVoid - Shape: Undefined

# IfcBuildingElementProxy: Bovedilla 3-11 (Paño 2) (2)
Type - Description: Bovedilla de hormigón; PredefinedType: USERDEFINED
Pset_BuildingElementProxyCommon - Reference: Bovedilla 3-11 (Paño 2); sets with these values: 2
Pset_ProvisionForVoid - Shape: Undefined
Name | In
Bovedilla 3-11 (Paño 2) | Depósito_
Bovedilla 3-11 (Paño 2) | PB | Pset_ProvisionForVoid - Width: 0.58 m; Height: 0.25 m; Depth: 0.25 m

# IfcBuildingElementProxy: Bovedilla 3-11 (Paño 3)
In: F1
Type - Description: Bovedilla de hormigón; PredefinedType: USERDEFINED
Pset_BuildingElementProxyCommon - Reference: Bovedilla 3-11 (Paño 3); sets with these values: 2
Pset_ProvisionForVoid - Shape: Undefined; Width: 0.58 m; Height: 0.25 m; Depth: 0.25 m

# IfcBuildingElementProxy: Bovedilla 3-11 (Paño 4)
In: F1
Type - Description: Bovedilla de hormigón; PredefinedType: USERDEFINED
Pset_BuildingElementProxyCommon - Reference: Bovedilla 3-11 (Paño 4); sets with these values: 2
Pset_ProvisionForVoid - Shape: Undefined; Width: 0.58 m; Height: 0.25 m; Depth: 0.25 m

# IfcBuildingElementProxy: Bovedilla 3-11 (Paño 6)
In: PB
Type - Description: Bovedilla de hormigón; PredefinedType: USERDEFINED
Pset_BuildingElementProxyCommon - Reference: Bovedilla 3-11 (Paño 6); sets with these values: 2
Pset_ProvisionForVoid - Shape: Undefined; Width: 0.58 m; Height: 0.25 m; Depth: 0.25 m

# IfcBuildingElementProxy: Bovedilla 3-12 (Paño 1)
In: Depósito_
Type - Description: Bovedilla de hormigón; PredefinedType: USERDEFINED
Pset_BuildingElementProxyCommon - Reference: Bovedilla 3-12 (Paño 1); sets with these values: 2
Pset_ProvisionForVoid - Shape: Undefined

# IfcBuildingElementProxy: Bovedilla 3-12 (Paño 2) (2)
Type - Description: Bovedilla de hormigón; PredefinedType: USERDEFINED
Pset_BuildingElementProxyCommon - Reference: Bovedilla 3-12 (Paño 2); sets with these values: 2
Pset_ProvisionForVoid - Shape: Undefined
Name | In
Bovedilla 3-12 (Paño 2) | Depósito_
Bovedilla 3-12 (Paño 2) | PB | Pset_ProvisionForVoid - Width: 0.58 m; Height: 0.25 m; Depth: 0.25 m

# IfcBuildingElementProxy: Bovedilla 3-12 (Paño 3)
In: F1
Type - Description: Bovedilla de hormigón; PredefinedType: USERDEFINED
Pset_BuildingElementProxyCommon - Reference: Bovedilla 3-12 (Paño 3); sets with these values: 2
Pset_ProvisionForVoid - Shape: Undefined; Width: 0.58 m; Height: 0.25 m; Depth: 0.25 m

# IfcBuildingElementProxy: Bovedilla 3-12 (Paño 4)
In: F1
Type - Description: Bovedilla de hormigón; PredefinedType: USERDEFINED
Pset_BuildingElementProxyCommon - Reference: Bovedilla 3-12 (Paño 4); sets with these values: 2
Pset_ProvisionForVoid - Shape: Undefined; Width: 0.58 m; Height: 0.25 m; Depth: 0.25 m

# IfcBuildingElementProxy: Bovedilla 3-12 (Paño 6)
In: PB
Type - Description: Bovedilla de hormigón; PredefinedType: USERDEFINED
Pset_BuildingElementProxyCommon - Reference: Bovedilla 3-12 (Paño 6); sets with these values: 2
Pset_ProvisionForVoid - Shape: Undefined; Width: 0.58 m; Height: 0.25 m; Depth: 0.25 m

# IfcBuildingElementProxy: Bovedilla 3-13 (Paño 1)
In: Depósito_
Type - Description: Bovedilla de hormigón; PredefinedType: USERDEFINED
Pset_BuildingElementProxyCommon - Reference: Bovedilla 3-13 (Paño 1); sets with these values: 2
Pset_ProvisionForVoid - Shape: Undefined

# IfcBuildingElementProxy: Bovedilla 3-13 (Paño 2) (2)
Type - Description: Bovedilla de hormigón; PredefinedType: USERDEFINED
Pset_BuildingElementProxyCommon - Reference: Bovedilla 3-13 (Paño 2); sets with these values: 2
Pset_ProvisionForVoid - Shape: Undefined
Name | In
Bovedilla 3-13 (Paño 2) | Depósito_
Bovedilla 3-13 (Paño 2) | PB | Pset_ProvisionForVoid - Width: 0.58 m; Height: 0.25 m; Depth: 0.25 m

# IfcBuildingElementProxy: Bovedilla 3-13 (Paño 3)
In: F1
Type - Description: Bovedilla de hormigón; PredefinedType: USERDEFINED
Pset_BuildingElementProxyCommon - Reference: Bovedilla 3-13 (Paño 3); sets with these values: 2
Pset_ProvisionForVoid - Shape: Undefined; Width: 0.58 m; Height: 0.25 m; Depth: 0.25 m

# IfcBuildingElementProxy: Bovedilla 3-13 (Paño 4)
In: F1
Type - Description: Bovedilla de hormigón; PredefinedType: USERDEFINED
Pset_BuildingElementProxyCommon - Reference: Bovedilla 3-13 (Paño 4); sets with these values: 2
Pset_ProvisionForVoid - Shape: Undefined; Width: 0.58 m; Height: 0.25 m; Depth: 0.25 m

# IfcBuildingElementProxy: Bovedilla 3-13 (Paño 6)
In: PB
Type - Description: Bovedilla de hormigón; PredefinedType: USERDEFINED
Pset_BuildingElementProxyCommon - Reference: Bovedilla 3-13 (Paño 6); sets with these values: 2
Pset_ProvisionForVoid - Shape: Undefined; Width: 0.58 m; Height: 0.25 m; Depth: 0.25 m

# IfcBuildingElementProxy: Bovedilla 3-14 (Paño 2)
In: PB
Type - Description: Bovedilla de hormigón; PredefinedType: USERDEFINED
Pset_BuildingElementProxyCommon - Reference: Bovedilla 3-14 (Paño 2); sets with these values: 2
Pset_ProvisionForVoid - Shape: Undefined; Width: 0.58 m; Height: 0.25 m; Depth: 0.25 m

# IfcBuildingElementProxy: Bovedilla 3-14 (Paño 3)
In: F1
Type - Description: Bovedilla de hormigón; PredefinedType: USERDEFINED
Pset_BuildingElementProxyCommon - Reference: Bovedilla 3-14 (Paño 3); sets with these values: 2
Pset_ProvisionForVoid - Shape: Undefined; Width: 0.58 m; Height: 0.25 m; Depth: 0.25 m

# IfcBuildingElementProxy: Bovedilla 3-14 (Paño 4)
In: F1
Type - Description: Bovedilla de hormigón; PredefinedType: USERDEFINED
Pset_BuildingElementProxyCommon - Reference: Bovedilla 3-14 (Paño 4); sets with these values: 2
Pset_ProvisionForVoid - Shape: Undefined; Width: 0.58 m; Height: 0.25 m; Depth: 0.25 m

# IfcBuildingElementProxy: Bovedilla 3-14 (Paño 6)
In: PB
Type - Description: Bovedilla de hormigón; PredefinedType: USERDEFINED
Pset_BuildingElementProxyCommon - Reference: Bovedilla 3-14 (Paño 6); sets with these values: 2
Pset_ProvisionForVoid - Shape: Undefined; Width: 0.58 m; Height: 0.25 m; Depth: 0.25 m

# IfcBuildingElementProxy: Bovedilla 3-15 (Paño 3)
In: F1
Type - Description: Bovedilla de hormigón; PredefinedType: USERDEFINED
Pset_BuildingElementProxyCommon - Reference: Bovedilla 3-15 (Paño 3); sets with these values: 2
Pset_ProvisionForVoid - Shape: Undefined; Width: 0.58 m; Height: 0.25 m; Depth: 0.25 m

# IfcBuildingElementProxy: Bovedilla 3-15 (Paño 4)
In: F1
Type - Description: Bovedilla de hormigón; PredefinedType: USERDEFINED
Pset_BuildingElementProxyCommon - Reference: Bovedilla 3-15 (Paño 4); sets with these values: 2
Pset_ProvisionForVoid - Shape: Undefined; Width: 0.58 m; Height: 0.25 m; Depth: 0.25 m

# IfcBuildingElementProxy: Bovedilla 3-15 (Paño 6)
In: PB
Type - Description: Bovedilla de hormigón; PredefinedType: USERDEFINED
Pset_BuildingElementProxyCommon - Reference: Bovedilla 3-15 (Paño 6); sets with these values: 2
Pset_ProvisionForVoid - Shape: Undefined; Width: 0.58 m; Height: 0.25 m; Depth: 0.25 m

# IfcBuildingElementProxy: Bovedilla 3-16 (Paño 3)
In: F1
Type - Description: Bovedilla de hormigón; PredefinedType: USERDEFINED
Pset_BuildingElementProxyCommon - Reference: Bovedilla 3-16 (Paño 3); sets with these values: 2
Pset_ProvisionForVoid - Shape: Undefined; Width: 0.58 m; Height: 0.25 m; Depth: 0.25 m

# IfcBuildingElementProxy: Bovedilla 3-16 (Paño 4)
In: F1
Type - Description: Bovedilla de hormigón; PredefinedType: USERDEFINED
Pset_BuildingElementProxyCommon - Reference: Bovedilla 3-16 (Paño 4); sets with these values: 2
Pset_ProvisionForVoid - Shape: Undefined; Width: 0.58 m; Height: 0.25 m; Depth: 0.25 m

# IfcBuildingElementProxy: Bovedilla 3-16 (Paño 6)
In: PB
Type - Description: Bovedilla de hormigón; PredefinedType: USERDEFINED
Pset_BuildingElementProxyCommon - Reference: Bovedilla 3-16 (Paño 6); sets with these values: 2
Pset_ProvisionForVoid - Shape: Undefined; Width: 0.58 m; Height: 0.25 m; Depth: 0.25 m

# IfcBuildingElementProxy: Bovedilla 3-17 (Paño 6)
In: PB
Type - Description: Bovedilla de hormigón; PredefinedType: USERDEFINED
Pset_BuildingElementProxyCommon - Reference: Bovedilla 3-17 (Paño 6); sets with these values: 2
Pset_ProvisionForVoid - Shape: Undefined; Width: 0.58 m; Height: 0.25 m; Depth: 0.25 m

# IfcBuildingElementProxy: Bovedilla 3-18 (Paño 6)
In: PB
Type - Description: Bovedilla de hormigón; PredefinedType: USERDEFINED
Pset_BuildingElementProxyCommon - Reference: Bovedilla 3-18 (Paño 6); sets with these values: 2
Pset_ProvisionForVoid - Shape: Undefined; Width: 0.58 m; Height: 0.25 m; Depth: 0.25 m

# IfcBuildingElementProxy: Bovedilla 3-19 (Paño 6)
In: PB
Type - Description: Bovedilla de hormigón; PredefinedType: USERDEFINED
Pset_BuildingElementProxyCommon - Reference: Bovedilla 3-19 (Paño 6); sets with these values: 2
Pset_ProvisionForVoid - Shape: Undefined; Width: 0.58 m; Height: 0.25 m; Depth: 0.25 m

# IfcBuildingElementProxy: Bovedilla 3-2 (Paño 1)
In: Depósito_
Type - Description: Bovedilla de hormigón; PredefinedType: USERDEFINED
Pset_BuildingElementProxyCommon - Reference: Bovedilla 3-2 (Paño 1); sets with these values: 2
Pset_ProvisionForVoid - Shape: Undefined

# IfcBuildingElementProxy: Bovedilla 3-2 (Paño 2) (2)
Type - Description: Bovedilla de hormigón; PredefinedType: USERDEFINED
Pset_BuildingElementProxyCommon - Reference: Bovedilla 3-2 (Paño 2); sets with these values: 2
Pset_ProvisionForVoid - Shape: Undefined
Name | In
Bovedilla 3-2 (Paño 2) | Depósito_
Bovedilla 3-2 (Paño 2) | PB | Pset_ProvisionForVoid - Width: 0.58 m; Height: 0.25 m; Depth: 0.25 m

# IfcBuildingElementProxy: Bovedilla 3-2 (Paño 3)
In: F1
Type - Description: Bovedilla de hormigón; PredefinedType: USERDEFINED
Pset_BuildingElementProxyCommon - Reference: Bovedilla 3-2 (Paño 3); sets with these values: 2
Pset_ProvisionForVoid - Shape: Undefined; Width: 0.58 m; Height: 0.25 m; Depth: 0.25 m

# IfcBuildingElementProxy: Bovedilla 3-2 (Paño 4)
In: F1
Type - Description: Bovedilla de hormigón; PredefinedType: USERDEFINED
Pset_BuildingElementProxyCommon - Reference: Bovedilla 3-2 (Paño 4); sets with these values: 2
Pset_ProvisionForVoid - Shape: Undefined; Width: 0.58 m; Height: 0.25 m; Depth: 0.25 m

# IfcBuildingElementProxy: Bovedilla 3-2 (Paño 6)
In: PB
Type - Description: Bovedilla de hormigón; PredefinedType: USERDEFINED
Pset_BuildingElementProxyCommon - Reference: Bovedilla 3-2 (Paño 6); sets with these values: 2
Pset_ProvisionForVoid - Shape: Undefined; Width: 0.58 m; Height: 0.25 m; Depth: 0.25 m

# IfcBuildingElementProxy: Bovedilla 3-20 (Paño 6)
In: PB
Type - Description: Bovedilla de hormigón; PredefinedType: USERDEFINED
Pset_BuildingElementProxyCommon - Reference: Bovedilla 3-20 (Paño 6); sets with these values: 2
Pset_ProvisionForVoid - Shape: Undefined; Width: 0.58 m; Height: 0.25 m; Depth: 0.25 m

# IfcBuildingElementProxy: Bovedilla 3-21 (Paño 6)
In: PB
Type - Description: Bovedilla de hormigón; PredefinedType: USERDEFINED
Pset_BuildingElementProxyCommon - Reference: Bovedilla 3-21 (Paño 6); sets with these values: 2
Pset_ProvisionForVoid - Shape: Undefined; Width: 0.58 m; Height: 0.25 m; Depth: 0.25 m

# IfcBuildingElementProxy: Bovedilla 3-22 (Paño 6)
In: PB
Type - Description: Bovedilla de hormigón; PredefinedType: USERDEFINED
Pset_BuildingElementProxyCommon - Reference: Bovedilla 3-22 (Paño 6); sets with these values: 2
Pset_ProvisionForVoid - Shape: Undefined; Width: 0.58 m; Height: 0.25 m; Depth: 0.25 m

# IfcBuildingElementProxy: Bovedilla 3-23 (Paño 6)
In: PB
Type - Description: Bovedilla de hormigón; PredefinedType: USERDEFINED
Pset_BuildingElementProxyCommon - Reference: Bovedilla 3-23 (Paño 6); sets with these values: 2
Pset_ProvisionForVoid - Shape: Undefined; Width: 0.58 m; Height: 0.25 m; Depth: 0.25 m

# IfcBuildingElementProxy: Bovedilla 3-24 (Paño 6)
In: PB
Type - Description: Bovedilla de hormigón; PredefinedType: USERDEFINED
Pset_BuildingElementProxyCommon - Reference: Bovedilla 3-24 (Paño 6); sets with these values: 2
Pset_ProvisionForVoid - Shape: Undefined; Width: 0.58 m; Height: 0.25 m; Depth: 0.25 m

# IfcBuildingElementProxy: Bovedilla 3-25 (Paño 6)
In: PB
Type - Description: Bovedilla de hormigón; PredefinedType: USERDEFINED
Pset_BuildingElementProxyCommon - Reference: Bovedilla 3-25 (Paño 6); sets with these values: 2
Pset_ProvisionForVoid - Shape: Undefined; Width: 0.58 m; Height: 0.25 m; Depth: 0.25 m

# IfcBuildingElementProxy: Bovedilla 3-3 (Paño 1)
In: Depósito_
Type - Description: Bovedilla de hormigón; PredefinedType: USERDEFINED
Pset_BuildingElementProxyCommon - Reference: Bovedilla 3-3 (Paño 1); sets with these values: 2
Pset_ProvisionForVoid - Shape: Undefined

# IfcBuildingElementProxy: Bovedilla 3-3 (Paño 2) (2)
Type - Description: Bovedilla de hormigón; PredefinedType: USERDEFINED
Pset_BuildingElementProxyCommon - Reference: Bovedilla 3-3 (Paño 2); sets with these values: 2
Pset_ProvisionForVoid - Shape: Undefined
Name | In
Bovedilla 3-3 (Paño 2) | Depósito_
Bovedilla 3-3 (Paño 2) | PB | Pset_ProvisionForVoid - Width: 0.58 m; Height: 0.25 m; Depth: 0.25 m

# IfcBuildingElementProxy: Bovedilla 3-3 (Paño 3)
In: F1
Type - Description: Bovedilla de hormigón; PredefinedType: USERDEFINED
Pset_BuildingElementProxyCommon - Reference: Bovedilla 3-3 (Paño 3); sets with these values: 2
Pset_ProvisionForVoid - Shape: Undefined; Width: 0.58 m; Height: 0.25 m; Depth: 0.25 m

# IfcBuildingElementProxy: Bovedilla 3-3 (Paño 4)
In: F1
Type - Description: Bovedilla de hormigón; PredefinedType: USERDEFINED
Pset_BuildingElementProxyCommon - Reference: Bovedilla 3-3 (Paño 4); sets with these values: 2
Pset_ProvisionForVoid - Shape: Undefined; Width: 0.58 m; Height: 0.25 m; Depth: 0.25 m

# IfcBuildingElementProxy: Bovedilla 3-3 (Paño 6)
In: PB
Type - Description: Bovedilla de hormigón; PredefinedType: USERDEFINED
Pset_BuildingElementProxyCommon - Reference: Bovedilla 3-3 (Paño 6); sets with these values: 2
Pset_ProvisionForVoid - Shape: Undefined; Width: 0.58 m; Height: 0.25 m; Depth: 0.25 m

# IfcBuildingElementProxy: Bovedilla 3-4 (Paño 1)
In: Depósito_
Type - Description: Bovedilla de hormigón; PredefinedType: USERDEFINED
Pset_BuildingElementProxyCommon - Reference: Bovedilla 3-4 (Paño 1); sets with these values: 2
Pset_ProvisionForVoid - Shape: Undefined

# IfcBuildingElementProxy: Bovedilla 3-4 (Paño 2) (2)
Type - Description: Bovedilla de hormigón; PredefinedType: USERDEFINED
Pset_BuildingElementProxyCommon - Reference: Bovedilla 3-4 (Paño 2); sets with these values: 2
Pset_ProvisionForVoid - Shape: Undefined
Name | In
Bovedilla 3-4 (Paño 2) | Depósito_
Bovedilla 3-4 (Paño 2) | PB | Pset_ProvisionForVoid - Width: 0.58 m; Height: 0.25 m; Depth: 0.25 m

# IfcBuildingElementProxy: Bovedilla 3-4 (Paño 3)
In: F1
Type - Description: Bovedilla de hormigón; PredefinedType: USERDEFINED
Pset_BuildingElementProxyCommon - Reference: Bovedilla 3-4 (Paño 3); sets with these values: 2
Pset_ProvisionForVoid - Shape: Undefined; Width: 0.58 m; Height: 0.25 m; Depth: 0.25 m

# IfcBuildingElementProxy: Bovedilla 3-4 (Paño 4)
In: F1
Type - Description: Bovedilla de hormigón; PredefinedType: USERDEFINED
Pset_BuildingElementProxyCommon - Reference: Bovedilla 3-4 (Paño 4); sets with these values: 2
Pset_ProvisionForVoid - Shape: Undefined; Width: 0.58 m; Height: 0.25 m; Depth: 0.25 m

# IfcBuildingElementProxy: Bovedilla 3-4 (Paño 6)
In: PB
Type - Description: Bovedilla de hormigón; PredefinedType: USERDEFINED
Pset_BuildingElementProxyCommon - Reference: Bovedilla 3-4 (Paño 6); sets with these values: 2
Pset_ProvisionForVoid - Shape: Undefined; Width: 0.58 m; Height: 0.25 m; Depth: 0.25 m

# IfcBuildingElementProxy: Bovedilla 3-5 (Paño 1)
In: Depósito_
Type - Description: Bovedilla de hormigón; PredefinedType: USERDEFINED
Pset_BuildingElementProxyCommon - Reference: Bovedilla 3-5 (Paño 1); sets with these values: 2
Pset_ProvisionForVoid - Shape: Undefined

# IfcBuildingElementProxy: Bovedilla 3-5 (Paño 2) (2)
Type - Description: Bovedilla de hormigón; PredefinedType: USERDEFINED
Pset_BuildingElementProxyCommon - Reference: Bovedilla 3-5 (Paño 2); sets with these values: 2
Pset_ProvisionForVoid - Shape: Undefined
Name | In
Bovedilla 3-5 (Paño 2) | Depósito_
Bovedilla 3-5 (Paño 2) | PB | Pset_ProvisionForVoid - Width: 0.58 m; Height: 0.25 m; Depth: 0.25 m

# IfcBuildingElementProxy: Bovedilla 3-5 (Paño 3)
In: F1
Type - Description: Bovedilla de hormigón; PredefinedType: USERDEFINED
Pset_BuildingElementProxyCommon - Reference: Bovedilla 3-5 (Paño 3); sets with these values: 2
Pset_ProvisionForVoid - Shape: Undefined; Width: 0.58 m; Height: 0.25 m; Depth: 0.25 m

# IfcBuildingElementProxy: Bovedilla 3-5 (Paño 4)
In: F1
Type - Description: Bovedilla de hormigón; PredefinedType: USERDEFINED
Pset_BuildingElementProxyCommon - Reference: Bovedilla 3-5 (Paño 4); sets with these values: 2
Pset_ProvisionForVoid - Shape: Undefined; Width: 0.58 m; Height: 0.25 m; Depth: 0.25 m

# IfcBuildingElementProxy: Bovedilla 3-5 (Paño 6)
In: PB
Type - Description: Bovedilla de hormigón; PredefinedType: USERDEFINED
Pset_BuildingElementProxyCommon - Reference: Bovedilla 3-5 (Paño 6); sets with these values: 2
Pset_ProvisionForVoid - Shape: Undefined; Width: 0.58 m; Height: 0.25 m; Depth: 0.25 m

# IfcBuildingElementProxy: Bovedilla 3-6 (Paño 1)
In: Depósito_
Type - Description: Bovedilla de hormigón; PredefinedType: USERDEFINED
Pset_BuildingElementProxyCommon - Reference: Bovedilla 3-6 (Paño 1); sets with these values: 2
Pset_ProvisionForVoid - Shape: Undefined

# IfcBuildingElementProxy: Bovedilla 3-6 (Paño 2) (2)
Type - Description: Bovedilla de hormigón; PredefinedType: USERDEFINED
Pset_BuildingElementProxyCommon - Reference: Bovedilla 3-6 (Paño 2); sets with these values: 2
Pset_ProvisionForVoid - Shape: Undefined
Name | In
Bovedilla 3-6 (Paño 2) | Depósito_
Bovedilla 3-6 (Paño 2) | PB | Pset_ProvisionForVoid - Width: 0.58 m; Height: 0.25 m; Depth: 0.25 m

# IfcBuildingElementProxy: Bovedilla 3-6 (Paño 3)
In: F1
Type - Description: Bovedilla de hormigón; PredefinedType: USERDEFINED
Pset_BuildingElementProxyCommon - Reference: Bovedilla 3-6 (Paño 3); sets with these values: 2
Pset_ProvisionForVoid - Shape: Undefined; Width: 0.58 m; Height: 0.25 m; Depth: 0.25 m

# IfcBuildingElementProxy: Bovedilla 3-6 (Paño 4)
In: F1
Type - Description: Bovedilla de hormigón; PredefinedType: USERDEFINED
Pset_BuildingElementProxyCommon - Reference: Bovedilla 3-6 (Paño 4); sets with these values: 2
Pset_ProvisionForVoid - Shape: Undefined; Width: 0.58 m; Height: 0.25 m; Depth: 0.25 m

# IfcBuildingElementProxy: Bovedilla 3-6 (Paño 6)
In: PB
Type - Description: Bovedilla de hormigón; PredefinedType: USERDEFINED
Pset_BuildingElementProxyCommon - Reference: Bovedilla 3-6 (Paño 6); sets with these values: 2
Pset_ProvisionForVoid - Shape: Undefined; Width: 0.58 m; Height: 0.25 m; Depth: 0.25 m

# IfcBuildingElementProxy: Bovedilla 3-7 (Paño 1)
In: Depósito_
Type - Description: Bovedilla de hormigón; PredefinedType: USERDEFINED
Pset_BuildingElementProxyCommon - Reference: Bovedilla 3-7 (Paño 1); sets with these values: 2
Pset_ProvisionForVoid - Shape: Undefined

# IfcBuildingElementProxy: Bovedilla 3-7 (Paño 2) (2)
Type - Description: Bovedilla de hormigón; PredefinedType: USERDEFINED
Pset_BuildingElementProxyCommon - Reference: Bovedilla 3-7 (Paño 2); sets with these values: 2
Pset_ProvisionForVoid - Shape: Undefined
Name | In
Bovedilla 3-7 (Paño 2) | Depósito_
Bovedilla 3-7 (Paño 2) | PB | Pset_ProvisionForVoid - Width: 0.58 m; Height: 0.25 m; Depth: 0.25 m

# IfcBuildingElementProxy: Bovedilla 3-7 (Paño 3)
In: F1
Type - Description: Bovedilla de hormigón; PredefinedType: USERDEFINED
Pset_BuildingElementProxyCommon - Reference: Bovedilla 3-7 (Paño 3); sets with these values: 2
Pset_ProvisionForVoid - Shape: Undefined; Width: 0.58 m; Height: 0.25 m; Depth: 0.25 m

# IfcBuildingElementProxy: Bovedilla 3-7 (Paño 4)
In: F1
Type - Description: Bovedilla de hormigón; PredefinedType: USERDEFINED
Pset_BuildingElementProxyCommon - Reference: Bovedilla 3-7 (Paño 4); sets with these values: 2
Pset_ProvisionForVoid - Shape: Undefined; Width: 0.58 m; Height: 0.25 m; Depth: 0.25 m

# IfcBuildingElementProxy: Bovedilla 3-7 (Paño 6)
In: PB
Type - Description: Bovedilla de hormigón; PredefinedType: USERDEFINED
Pset_BuildingElementProxyCommon - Reference: Bovedilla 3-7 (Paño 6); sets with these values: 2
Pset_ProvisionForVoid - Shape: Undefined; Width: 0.58 m; Height: 0.25 m; Depth: 0.25 m

# IfcBuildingElementProxy: Bovedilla 3-8 (Paño 1)
In: Depósito_
Type - Description: Bovedilla de hormigón; PredefinedType: USERDEFINED
Pset_BuildingElementProxyCommon - Reference: Bovedilla 3-8 (Paño 1); sets with these values: 2
Pset_ProvisionForVoid - Shape: Undefined

# IfcBuildingElementProxy: Bovedilla 3-8 (Paño 2) (2)
Type - Description: Bovedilla de hormigón; PredefinedType: USERDEFINED
Pset_BuildingElementProxyCommon - Reference: Bovedilla 3-8 (Paño 2); sets with these values: 2
Pset_ProvisionForVoid - Shape: Undefined
Name | In
Bovedilla 3-8 (Paño 2) | Depósito_
Bovedilla 3-8 (Paño 2) | PB | Pset_ProvisionForVoid - Width: 0.58 m; Height: 0.25 m; Depth: 0.25 m

# IfcBuildingElementProxy: Bovedilla 3-8 (Paño 3)
In: F1
Type - Description: Bovedilla de hormigón; PredefinedType: USERDEFINED
Pset_BuildingElementProxyCommon - Reference: Bovedilla 3-8 (Paño 3); sets with these values: 2
Pset_ProvisionForVoid - Shape: Undefined; Width: 0.58 m; Height: 0.25 m; Depth: 0.25 m

# IfcBuildingElementProxy: Bovedilla 3-8 (Paño 4)
In: F1
Type - Description: Bovedilla de hormigón; PredefinedType: USERDEFINED
Pset_BuildingElementProxyCommon - Reference: Bovedilla 3-8 (Paño 4); sets with these values: 2
Pset_ProvisionForVoid - Shape: Undefined; Width: 0.58 m; Height: 0.25 m; Depth: 0.25 m

# IfcBuildingElementProxy: Bovedilla 3-8 (Paño 6)
In: PB
Type - Description: Bovedilla de hormigón; PredefinedType: USERDEFINED
Pset_BuildingElementProxyCommon - Reference: Bovedilla 3-8 (Paño 6); sets with these values: 2
Pset_ProvisionForVoid - Shape: Undefined; Width: 0.58 m; Height: 0.25 m; Depth: 0.25 m

# IfcBuildingElementProxy: Bovedilla 3-9 (Paño 1)
In: Depósito_
Type - Description: Bovedilla de hormigón; PredefinedType: USERDEFINED
Pset_BuildingElementProxyCommon - Reference: Bovedilla 3-9 (Paño 1); sets with these values: 2
Pset_ProvisionForVoid - Shape: Undefined

# IfcBuildingElementProxy: Bovedilla 3-9 (Paño 2) (2)
Type - Description: Bovedilla de hormigón; PredefinedType: USERDEFINED
Pset_BuildingElementProxyCommon - Reference: Bovedilla 3-9 (Paño 2); sets with these values: 2
Pset_ProvisionForVoid - Shape: Undefined
Name | In
Bovedilla 3-9 (Paño 2) | Depósito_
Bovedilla 3-9 (Paño 2) | PB | Pset_ProvisionForVoid - Width: 0.58 m; Height: 0.25 m; Depth: 0.25 m

# IfcBuildingElementProxy: Bovedilla 3-9 (Paño 3)
In: F1
Type - Description: Bovedilla de hormigón; PredefinedType: USERDEFINED
Pset_BuildingElementProxyCommon - Reference: Bovedilla 3-9 (Paño 3); sets with these values: 2
Pset_ProvisionForVoid - Shape: Undefined; Width: 0.58 m; Height: 0.25 m; Depth: 0.25 m

# IfcBuildingElementProxy: Bovedilla 3-9 (Paño 4)
In: F1
Type - Description: Bovedilla de hormigón; PredefinedType: USERDEFINED
Pset_BuildingElementProxyCommon - Reference: Bovedilla 3-9 (Paño 4); sets with these values: 2
Pset_ProvisionForVoid - Shape: Undefined; Width: 0.58 m; Height: 0.25 m; Depth: 0.25 m

# IfcBuildingElementProxy: Bovedilla 3-9 (Paño 6)
In: PB
Type - Description: Bovedilla de hormigón; PredefinedType: USERDEFINED
Pset_BuildingElementProxyCommon - Reference: Bovedilla 3-9 (Paño 6); sets with these values: 2
Pset_ProvisionForVoid - Shape: Undefined; Width: 0.58 m; Height: 0.25 m; Depth: 0.25 m

# IfcBuildingElementProxy: Bovedilla 4-1 (Paño 1)
In: Depósito_
Type - Description: Bovedilla de hormigón; PredefinedType: USERDEFINED
Pset_BuildingElementProxyCommon - Reference: Bovedilla 4-1 (Paño 1); sets with these values: 2
Pset_ProvisionForVoid - Shape: Undefined

# IfcBuildingElementProxy: Bovedilla 4-1 (Paño 2) (2)
Type - Description: Bovedilla de hormigón; PredefinedType: USERDEFINED
Pset_BuildingElementProxyCommon - Reference: Bovedilla 4-1 (Paño 2); sets with these values: 2
Pset_ProvisionForVoid - Shape: Undefined
Name | In
Bovedilla 4-1 (Paño 2) | Depósito_
Bovedilla 4-1 (Paño 2) | PB | Pset_ProvisionForVoid - Width: 0.58 m; Height: 0.25 m; Depth: 0.25 m

# IfcBuildingElementProxy: Bovedilla 4-1 (Paño 3)
In: F1
Type - Description: Bovedilla de hormigón; PredefinedType: USERDEFINED
Pset_BuildingElementProxyCommon - Reference: Bovedilla 4-1 (Paño 3); sets with these values: 2
Pset_ProvisionForVoid - Shape: Undefined; Width: 0.58 m; Height: 0.25 m; Depth: 0.25 m

# IfcBuildingElementProxy: Bovedilla 4-1 (Paño 4)
In: F1
Type - Description: Bovedilla de hormigón; PredefinedType: USERDEFINED
Pset_BuildingElementProxyCommon - Reference: Bovedilla 4-1 (Paño 4); sets with these values: 2
Pset_ProvisionForVoid - Shape: Undefined; Width: 0.58 m; Height: 0.25 m; Depth: 0.25 m

# IfcBuildingElementProxy: Bovedilla 4-10 (Paño 1)
In: Depósito_
Type - Description: Bovedilla de hormigón; PredefinedType: USERDEFINED
Pset_BuildingElementProxyCommon - Reference: Bovedilla 4-10 (Paño 1); sets with these values: 2
Pset_ProvisionForVoid - Shape: Undefined

# IfcBuildingElementProxy: Bovedilla 4-10 (Paño 2) (2)
Type - Description: Bovedilla de hormigón; PredefinedType: USERDEFINED
Pset_BuildingElementProxyCommon - Reference: Bovedilla 4-10 (Paño 2); sets with these values: 2
Pset_ProvisionForVoid - Shape: Undefined
Name | In
Bovedilla 4-10 (Paño 2) | Depósito_
Bovedilla 4-10 (Paño 2) | PB | Pset_ProvisionForVoid - Width: 0.58 m; Height: 0.25 m; Depth: 0.25 m

# IfcBuildingElementProxy: Bovedilla 4-10 (Paño 3)
In: F1
Type - Description: Bovedilla de hormigón; PredefinedType: USERDEFINED
Pset_BuildingElementProxyCommon - Reference: Bovedilla 4-10 (Paño 3); sets with these values: 2
Pset_ProvisionForVoid - Shape: Undefined; Width: 0.58 m; Height: 0.25 m; Depth: 0.25 m

# IfcBuildingElementProxy: Bovedilla 4-10 (Paño 4)
In: F1
Type - Description: Bovedilla de hormigón; PredefinedType: USERDEFINED
Pset_BuildingElementProxyCommon - Reference: Bovedilla 4-10 (Paño 4); sets with these values: 2
Pset_ProvisionForVoid - Shape: Undefined; Width: 0.58 m; Height: 0.25 m; Depth: 0.25 m

# IfcBuildingElementProxy: Bovedilla 4-11 (Paño 1)
In: Depósito_
Type - Description: Bovedilla de hormigón; PredefinedType: USERDEFINED
Pset_BuildingElementProxyCommon - Reference: Bovedilla 4-11 (Paño 1); sets with these values: 2
Pset_ProvisionForVoid - Shape: Undefined

# IfcBuildingElementProxy: Bovedilla 4-11 (Paño 2) (2)
Type - Description: Bovedilla de hormigón; PredefinedType: USERDEFINED
Pset_BuildingElementProxyCommon - Reference: Bovedilla 4-11 (Paño 2); sets with these values: 2
Pset_ProvisionForVoid - Shape: Undefined
Name | In
Bovedilla 4-11 (Paño 2) | Depósito_
Bovedilla 4-11 (Paño 2) | PB | Pset_ProvisionForVoid - Width: 0.58 m; Height: 0.25 m; Depth: 0.25 m

# IfcBuildingElementProxy: Bovedilla 4-11 (Paño 3)
In: F1
Type - Description: Bovedilla de hormigón; PredefinedType: USERDEFINED
Pset_BuildingElementProxyCommon - Reference: Bovedilla 4-11 (Paño 3); sets with these values: 2
Pset_ProvisionForVoid - Shape: Undefined; Width: 0.58 m; Height: 0.25 m; Depth: 0.25 m

# IfcBuildingElementProxy: Bovedilla 4-11 (Paño 4)
In: F1
Type - Description: Bovedilla de hormigón; PredefinedType: USERDEFINED
Pset_BuildingElementProxyCommon - Reference: Bovedilla 4-11 (Paño 4); sets with these values: 2
Pset_ProvisionForVoid - Shape: Undefined; Width: 0.58 m; Height: 0.25 m; Depth: 0.25 m

# IfcBuildingElementProxy: Bovedilla 4-12 (Paño 1)
In: Depósito_
Type - Description: Bovedilla de hormigón; PredefinedType: USERDEFINED
Pset_BuildingElementProxyCommon - Reference: Bovedilla 4-12 (Paño 1); sets with these values: 2
Pset_ProvisionForVoid - Shape: Undefined

# IfcBuildingElementProxy: Bovedilla 4-12 (Paño 2) (2)
Type - Description: Bovedilla de hormigón; PredefinedType: USERDEFINED
Pset_BuildingElementProxyCommon - Reference: Bovedilla 4-12 (Paño 2); sets with these values: 2
Pset_ProvisionForVoid - Shape: Undefined
Name | In
Bovedilla 4-12 (Paño 2) | Depósito_
Bovedilla 4-12 (Paño 2) | PB | Pset_ProvisionForVoid - Width: 0.58 m; Height: 0.25 m; Depth: 0.25 m

# IfcBuildingElementProxy: Bovedilla 4-12 (Paño 3)
In: F1
Type - Description: Bovedilla de hormigón; PredefinedType: USERDEFINED
Pset_BuildingElementProxyCommon - Reference: Bovedilla 4-12 (Paño 3); sets with these values: 2
Pset_ProvisionForVoid - Shape: Undefined; Width: 0.58 m; Height: 0.25 m; Depth: 0.25 m

# IfcBuildingElementProxy: Bovedilla 4-12 (Paño 4)
In: F1
Type - Description: Bovedilla de hormigón; PredefinedType: USERDEFINED
Pset_BuildingElementProxyCommon - Reference: Bovedilla 4-12 (Paño 4); sets with these values: 2
Pset_ProvisionForVoid - Shape: Undefined; Width: 0.58 m; Height: 0.25 m; Depth: 0.25 m

# IfcBuildingElementProxy: Bovedilla 4-13 (Paño 1)
In: Depósito_
Type - Description: Bovedilla de hormigón; PredefinedType: USERDEFINED
Pset_BuildingElementProxyCommon - Reference: Bovedilla 4-13 (Paño 1); sets with these values: 2
Pset_ProvisionForVoid - Shape: Undefined

# IfcBuildingElementProxy: Bovedilla 4-13 (Paño 2) (2)
Type - Description: Bovedilla de hormigón; PredefinedType: USERDEFINED
Pset_BuildingElementProxyCommon - Reference: Bovedilla 4-13 (Paño 2); sets with these values: 2
Pset_ProvisionForVoid - Shape: Undefined
Name | In
Bovedilla 4-13 (Paño 2) | Depósito_
Bovedilla 4-13 (Paño 2) | PB | Pset_ProvisionForVoid - Width: 0.58 m; Height: 0.25 m; Depth: 0.25 m

# IfcBuildingElementProxy: Bovedilla 4-13 (Paño 3)
In: F1
Type - Description: Bovedilla de hormigón; PredefinedType: USERDEFINED
Pset_BuildingElementProxyCommon - Reference: Bovedilla 4-13 (Paño 3); sets with these values: 2
Pset_ProvisionForVoid - Shape: Undefined; Width: 0.58 m; Height: 0.25 m; Depth: 0.25 m

# IfcBuildingElementProxy: Bovedilla 4-13 (Paño 4)
In: F1
Type - Description: Bovedilla de hormigón; PredefinedType: USERDEFINED
Pset_BuildingElementProxyCommon - Reference: Bovedilla 4-13 (Paño 4); sets with these values: 2
Pset_ProvisionForVoid - Shape: Undefined; Width: 0.58 m; Height: 0.25 m; Depth: 0.25 m

# IfcBuildingElementProxy: Bovedilla 4-14 (Paño 2)
In: PB
Type - Description: Bovedilla de hormigón; PredefinedType: USERDEFINED
Pset_BuildingElementProxyCommon - Reference: Bovedilla 4-14 (Paño 2); sets with these values: 2
Pset_ProvisionForVoid - Shape: Undefined; Width: 0.58 m; Height: 0.25 m; Depth: 0.25 m

# IfcBuildingElementProxy: Bovedilla 4-14 (Paño 3)
In: F1
Type - Description: Bovedilla de hormigón; PredefinedType: USERDEFINED
Pset_BuildingElementProxyCommon - Reference: Bovedilla 4-14 (Paño 3); sets with these values: 2
Pset_ProvisionForVoid - Shape: Undefined; Width: 0.58 m; Height: 0.25 m; Depth: 0.25 m

# IfcBuildingElementProxy: Bovedilla 4-14 (Paño 4)
In: F1
Type - Description: Bovedilla de hormigón; PredefinedType: USERDEFINED
Pset_BuildingElementProxyCommon - Reference: Bovedilla 4-14 (Paño 4); sets with these values: 2
Pset_ProvisionForVoid - Shape: Undefined; Width: 0.58 m; Height: 0.25 m; Depth: 0.25 m

# IfcBuildingElementProxy: Bovedilla 4-15 (Paño 3)
In: F1
Type - Description: Bovedilla de hormigón; PredefinedType: USERDEFINED
Pset_BuildingElementProxyCommon - Reference: Bovedilla 4-15 (Paño 3); sets with these values: 2
Pset_ProvisionForVoid - Shape: Undefined; Width: 0.58 m; Height: 0.25 m; Depth: 0.25 m

# IfcBuildingElementProxy: Bovedilla 4-15 (Paño 4)
In: F1
Type - Description: Bovedilla de hormigón; PredefinedType: USERDEFINED
Pset_BuildingElementProxyCommon - Reference: Bovedilla 4-15 (Paño 4); sets with these values: 2
Pset_ProvisionForVoid - Shape: Undefined; Width: 0.58 m; Height: 0.25 m; Depth: 0.25 m

# IfcBuildingElementProxy: Bovedilla 4-16 (Paño 3)
In: F1
Type - Description: Bovedilla de hormigón; PredefinedType: USERDEFINED
Pset_BuildingElementProxyCommon - Reference: Bovedilla 4-16 (Paño 3); sets with these values: 2
Pset_ProvisionForVoid - Shape: Undefined; Width: 0.58 m; Height: 0.25 m; Depth: 0.25 m

# IfcBuildingElementProxy: Bovedilla 4-16 (Paño 4)
In: F1
Type - Description: Bovedilla de hormigón; PredefinedType: USERDEFINED
Pset_BuildingElementProxyCommon - Reference: Bovedilla 4-16 (Paño 4); sets with these values: 2
Pset_ProvisionForVoid - Shape: Undefined; Width: 0.58 m; Height: 0.25 m; Depth: 0.25 m

# IfcBuildingElementProxy: Bovedilla 4-2 (Paño 1)
In: Depósito_
Type - Description: Bovedilla de hormigón; PredefinedType: USERDEFINED
Pset_BuildingElementProxyCommon - Reference: Bovedilla 4-2 (Paño 1); sets with these values: 2
Pset_ProvisionForVoid - Shape: Undefined

# IfcBuildingElementProxy: Bovedilla 4-2 (Paño 2) (2)
Type - Description: Bovedilla de hormigón; PredefinedType: USERDEFINED
Pset_BuildingElementProxyCommon - Reference: Bovedilla 4-2 (Paño 2); sets with these values: 2
Pset_ProvisionForVoid - Shape: Undefined
Name | In
Bovedilla 4-2 (Paño 2) | Depósito_
Bovedilla 4-2 (Paño 2) | PB | Pset_ProvisionForVoid - Width: 0.58 m; Height: 0.25 m; Depth: 0.25 m

# IfcBuildingElementProxy: Bovedilla 4-2 (Paño 3)
In: F1
Type - Description: Bovedilla de hormigón; PredefinedType: USERDEFINED
Pset_BuildingElementProxyCommon - Reference: Bovedilla 4-2 (Paño 3); sets with these values: 2
Pset_ProvisionForVoid - Shape: Undefined; Width: 0.58 m; Height: 0.25 m; Depth: 0.25 m

# IfcBuildingElementProxy: Bovedilla 4-2 (Paño 4)
In: F1
Type - Description: Bovedilla de hormigón; PredefinedType: USERDEFINED
Pset_BuildingElementProxyCommon - Reference: Bovedilla 4-2 (Paño 4); sets with these values: 2
Pset_ProvisionForVoid - Shape: Undefined; Width: 0.58 m; Height: 0.25 m; Depth: 0.25 m

# IfcBuildingElementProxy: Bovedilla 4-3 (Paño 1)
In: Depósito_
Type - Description: Bovedilla de hormigón; PredefinedType: USERDEFINED
Pset_BuildingElementProxyCommon - Reference: Bovedilla 4-3 (Paño 1); sets with these values: 2
Pset_ProvisionForVoid - Shape: Undefined

# IfcBuildingElementProxy: Bovedilla 4-3 (Paño 2) (2)
Type - Description: Bovedilla de hormigón; PredefinedType: USERDEFINED
Pset_BuildingElementProxyCommon - Reference: Bovedilla 4-3 (Paño 2); sets with these values: 2
Pset_ProvisionForVoid - Shape: Undefined
Name | In
Bovedilla 4-3 (Paño 2) | Depósito_
Bovedilla 4-3 (Paño 2) | PB | Pset_ProvisionForVoid - Width: 0.58 m; Height: 0.25 m; Depth: 0.25 m

# IfcBuildingElementProxy: Bovedilla 4-3 (Paño 3)
In: F1
Type - Description: Bovedilla de hormigón; PredefinedType: USERDEFINED
Pset_BuildingElementProxyCommon - Reference: Bovedilla 4-3 (Paño 3); sets with these values: 2
Pset_ProvisionForVoid - Shape: Undefined; Width: 0.58 m; Height: 0.25 m; Depth: 0.25 m

# IfcBuildingElementProxy: Bovedilla 4-3 (Paño 4)
In: F1
Type - Description: Bovedilla de hormigón; PredefinedType: USERDEFINED
Pset_BuildingElementProxyCommon - Reference: Bovedilla 4-3 (Paño 4); sets with these values: 2
Pset_ProvisionForVoid - Shape: Undefined; Width: 0.58 m; Height: 0.25 m; Depth: 0.25 m

# IfcBuildingElementProxy: Bovedilla 4-4 (Paño 1)
In: Depósito_
Type - Description: Bovedilla de hormigón; PredefinedType: USERDEFINED
Pset_BuildingElementProxyCommon - Reference: Bovedilla 4-4 (Paño 1); sets with these values: 2
Pset_ProvisionForVoid - Shape: Undefined

# IfcBuildingElementProxy: Bovedilla 4-4 (Paño 2) (2)
Type - Description: Bovedilla de hormigón; PredefinedType: USERDEFINED
Pset_BuildingElementProxyCommon - Reference: Bovedilla 4-4 (Paño 2); sets with these values: 2
Pset_ProvisionForVoid - Shape: Undefined
Name | In
Bovedilla 4-4 (Paño 2) | Depósito_
Bovedilla 4-4 (Paño 2) | PB | Pset_ProvisionForVoid - Width: 0.58 m; Height: 0.25 m; Depth: 0.25 m

# IfcBuildingElementProxy: Bovedilla 4-4 (Paño 3)
In: F1
Type - Description: Bovedilla de hormigón; PredefinedType: USERDEFINED
Pset_BuildingElementProxyCommon - Reference: Bovedilla 4-4 (Paño 3); sets with these values: 2
Pset_ProvisionForVoid - Shape: Undefined; Width: 0.58 m; Height: 0.25 m; Depth: 0.25 m

# IfcBuildingElementProxy: Bovedilla 4-4 (Paño 4)
In: F1
Type - Description: Bovedilla de hormigón; PredefinedType: USERDEFINED
Pset_BuildingElementProxyCommon - Reference: Bovedilla 4-4 (Paño 4); sets with these values: 2
Pset_ProvisionForVoid - Shape: Undefined; Width: 0.58 m; Height: 0.25 m; Depth: 0.25 m

# IfcBuildingElementProxy: Bovedilla 4-5 (Paño 1)
In: Depósito_
Type - Description: Bovedilla de hormigón; PredefinedType: USERDEFINED
Pset_BuildingElementProxyCommon - Reference: Bovedilla 4-5 (Paño 1); sets with these values: 2
Pset_ProvisionForVoid - Shape: Undefined

# IfcBuildingElementProxy: Bovedilla 4-5 (Paño 2) (2)
Type - Description: Bovedilla de hormigón; PredefinedType: USERDEFINED
Pset_BuildingElementProxyCommon - Reference: Bovedilla 4-5 (Paño 2); sets with these values: 2
Pset_ProvisionForVoid - Shape: Undefined
Name | In
Bovedilla 4-5 (Paño 2) | Depósito_
Bovedilla 4-5 (Paño 2) | PB | Pset_ProvisionForVoid - Width: 0.58 m; Height: 0.25 m; Depth: 0.25 m

# IfcBuildingElementProxy: Bovedilla 4-5 (Paño 3)
In: F1
Type - Description: Bovedilla de hormigón; PredefinedType: USERDEFINED
Pset_BuildingElementProxyCommon - Reference: Bovedilla 4-5 (Paño 3); sets with these values: 2
Pset_ProvisionForVoid - Shape: Undefined; Width: 0.58 m; Height: 0.25 m; Depth: 0.25 m

# IfcBuildingElementProxy: Bovedilla 4-5 (Paño 4)
In: F1
Type - Description: Bovedilla de hormigón; PredefinedType: USERDEFINED
Pset_BuildingElementProxyCommon - Reference: Bovedilla 4-5 (Paño 4); sets with these values: 2
Pset_ProvisionForVoid - Shape: Undefined; Width: 0.58 m; Height: 0.25 m; Depth: 0.25 m

# IfcBuildingElementProxy: Bovedilla 4-6 (Paño 1)
In: Depósito_
Type - Description: Bovedilla de hormigón; PredefinedType: USERDEFINED
Pset_BuildingElementProxyCommon - Reference: Bovedilla 4-6 (Paño 1); sets with these values: 2
Pset_ProvisionForVoid - Shape: Undefined

# IfcBuildingElementProxy: Bovedilla 4-6 (Paño 2) (2)
Type - Description: Bovedilla de hormigón; PredefinedType: USERDEFINED
Pset_BuildingElementProxyCommon - Reference: Bovedilla 4-6 (Paño 2); sets with these values: 2
Pset_ProvisionForVoid - Shape: Undefined
Name | In
Bovedilla 4-6 (Paño 2) | Depósito_
Bovedilla 4-6 (Paño 2) | PB | Pset_ProvisionForVoid - Width: 0.58 m; Height: 0.25 m; Depth: 0.25 m

# IfcBuildingElementProxy: Bovedilla 4-6 (Paño 3)
In: F1
Type - Description: Bovedilla de hormigón; PredefinedType: USERDEFINED
Pset_BuildingElementProxyCommon - Reference: Bovedilla 4-6 (Paño 3); sets with these values: 2
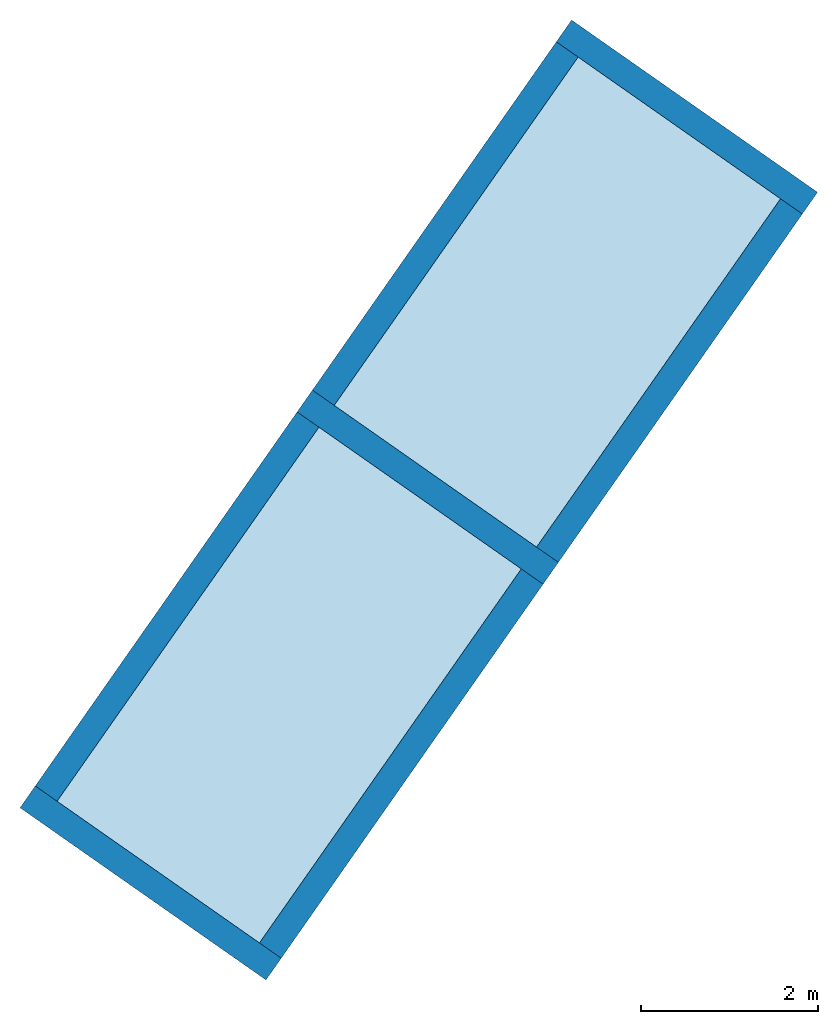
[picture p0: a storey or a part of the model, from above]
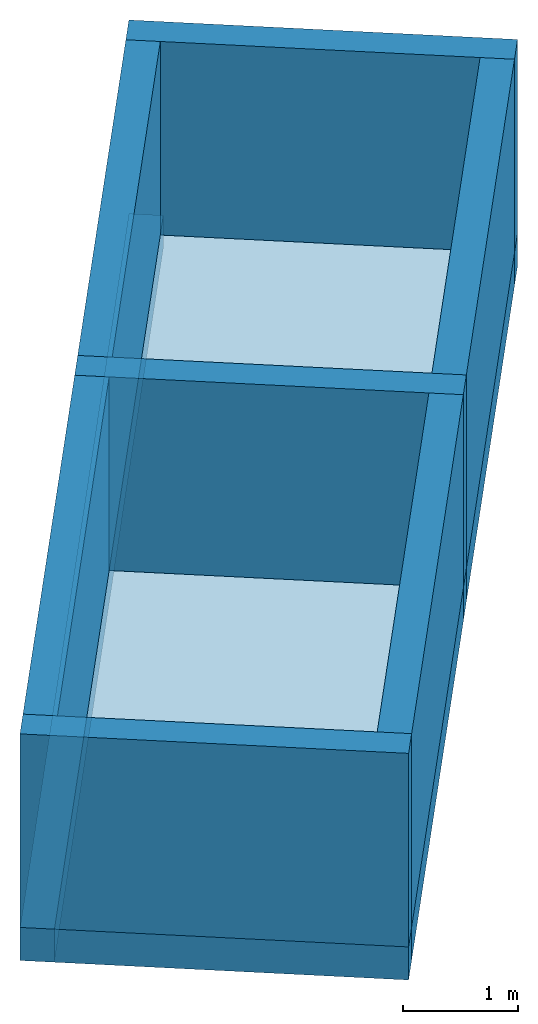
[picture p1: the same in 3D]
Properties of the parts of a building model (IFC2X3), part 4 of 5

# IfcBuildingElementProxy: Bovedilla 4-6 (Paño 3)
Pset_ProvisionForVoid - Shape: Undefined; Width: 0.58 m; Height: 0.25 m; Depth: 0.25 m

# IfcBuildingElementProxy: Bovedilla 4-6 (Paño 4)
In: F1
Type - Description: Bovedilla de hormigón; PredefinedType: USERDEFINED
Pset_BuildingElementProxyCommon - Reference: Bovedilla 4-6 (Paño 4); sets with these values: 2
Pset_ProvisionForVoid - Shape: Undefined; Width: 0.58 m; Height: 0.25 m; Depth: 0.25 m

# IfcBuildingElementProxy: Bovedilla 4-7 (Paño 1)
In: Depósito_
Type - Description: Bovedilla de hormigón; PredefinedType: USERDEFINED
Pset_BuildingElementProxyCommon - Reference: Bovedilla 4-7 (Paño 1); sets with these values: 2
Pset_ProvisionForVoid - Shape: Undefined

# IfcBuildingElementProxy: Bovedilla 4-7 (Paño 2) (2)
Type - Description: Bovedilla de hormigón; PredefinedType: USERDEFINED
Pset_BuildingElementProxyCommon - Reference: Bovedilla 4-7 (Paño 2); sets with these values: 2
Pset_ProvisionForVoid - Shape: Undefined
Name | In
Bovedilla 4-7 (Paño 2) | Depósito_
Bovedilla 4-7 (Paño 2) | PB | Pset_ProvisionForVoid - Width: 0.58 m; Height: 0.25 m; Depth: 0.25 m

# IfcBuildingElementProxy: Bovedilla 4-7 (Paño 3)
In: F1
Type - Description: Bovedilla de hormigón; PredefinedType: USERDEFINED
Pset_BuildingElementProxyCommon - Reference: Bovedilla 4-7 (Paño 3); sets with these values: 2
Pset_ProvisionForVoid - Shape: Undefined; Width: 0.58 m; Height: 0.25 m; Depth: 0.25 m

# IfcBuildingElementProxy: Bovedilla 4-7 (Paño 4)
In: F1
Type - Description: Bovedilla de hormigón; PredefinedType: USERDEFINED
Pset_BuildingElementProxyCommon - Reference: Bovedilla 4-7 (Paño 4); sets with these values: 2
Pset_ProvisionForVoid - Shape: Undefined; Width: 0.58 m; Height: 0.25 m; Depth: 0.25 m

# IfcBuildingElementProxy: Bovedilla 4-8 (Paño 1)
In: Depósito_
Type - Description: Bovedilla de hormigón; PredefinedType: USERDEFINED
Pset_BuildingElementProxyCommon - Reference: Bovedilla 4-8 (Paño 1); sets with these values: 2
Pset_ProvisionForVoid - Shape: Undefined

# IfcBuildingElementProxy: Bovedilla 4-8 (Paño 2) (2)
Type - Description: Bovedilla de hormigón; PredefinedType: USERDEFINED
Pset_BuildingElementProxyCommon - Reference: Bovedilla 4-8 (Paño 2); sets with these values: 2
Pset_ProvisionForVoid - Shape: Undefined
Name | In
Bovedilla 4-8 (Paño 2) | Depósito_
Bovedilla 4-8 (Paño 2) | PB | Pset_ProvisionForVoid - Width: 0.58 m; Height: 0.25 m; Depth: 0.25 m

# IfcBuildingElementProxy: Bovedilla 4-8 (Paño 3)
In: F1
Type - Description: Bovedilla de hormigón; PredefinedType: USERDEFINED
Pset_BuildingElementProxyCommon - Reference: Bovedilla 4-8 (Paño 3); sets with these values: 2
Pset_ProvisionForVoid - Shape: Undefined; Width: 0.58 m; Height: 0.25 m; Depth: 0.25 m

# IfcBuildingElementProxy: Bovedilla 4-8 (Paño 4)
In: F1
Type - Description: Bovedilla de hormigón; PredefinedType: USERDEFINED
Pset_BuildingElementProxyCommon - Reference: Bovedilla 4-8 (Paño 4); sets with these values: 2
Pset_ProvisionForVoid - Shape: Undefined; Width: 0.58 m; Height: 0.25 m; Depth: 0.25 m

# IfcBuildingElementProxy: Bovedilla 4-9 (Paño 1)
In: Depósito_
Type - Description: Bovedilla de hormigón; PredefinedType: USERDEFINED
Pset_BuildingElementProxyCommon - Reference: Bovedilla 4-9 (Paño 1); sets with these values: 2
Pset_ProvisionForVoid - Shape: Undefined

# IfcBuildingElementProxy: Bovedilla 4-9 (Paño 2) (2)
Type - Description: Bovedilla de hormigón; PredefinedType: USERDEFINED
Pset_BuildingElementProxyCommon - Reference: Bovedilla 4-9 (Paño 2); sets with these values: 2
Pset_ProvisionForVoid - Shape: Undefined
Name | In
Bovedilla 4-9 (Paño 2) | Depósito_
Bovedilla 4-9 (Paño 2) | PB | Pset_ProvisionForVoid - Width: 0.58 m; Height: 0.25 m; Depth: 0.25 m

# IfcBuildingElementProxy: Bovedilla 4-9 (Paño 3)
In: F1
Type - Description: Bovedilla de hormigón; PredefinedType: USERDEFINED
Pset_BuildingElementProxyCommon - Reference: Bovedilla 4-9 (Paño 3); sets with these values: 2
Pset_ProvisionForVoid - Shape: Undefined; Width: 0.58 m; Height: 0.25 m; Depth: 0.25 m

# IfcBuildingElementProxy: Bovedilla 4-9 (Paño 4)
In: F1
Type - Description: Bovedilla de hormigón; PredefinedType: USERDEFINED
Pset_BuildingElementProxyCommon - Reference: Bovedilla 4-9 (Paño 4); sets with these values: 2
Pset_ProvisionForVoid - Shape: Undefined; Width: 0.58 m; Height: 0.25 m; Depth: 0.25 m

# IfcBuildingElementProxy: Bovedilla 5-1 (Paño 1)
In: Depósito_
Type - Description: Bovedilla de hormigón; PredefinedType: USERDEFINED
Pset_BuildingElementProxyCommon - Reference: Bovedilla 5-1 (Paño 1); sets with these values: 2
Pset_ProvisionForVoid - Shape: Undefined

# IfcBuildingElementProxy: Bovedilla 5-1 (Paño 2) (2)
Type - Description: Bovedilla de hormigón; PredefinedType: USERDEFINED
Pset_BuildingElementProxyCommon - Reference: Bovedilla 5-1 (Paño 2); sets with these values: 2
Pset_ProvisionForVoid - Shape: Undefined
Name | In
Bovedilla 5-1 (Paño 2) | Depósito_
Bovedilla 5-1 (Paño 2) | PB | Pset_ProvisionForVoid - Width: 0.58 m; Height: 0.25 m; Depth: 0.25 m

# IfcBuildingElementProxy: Bovedilla 5-1 (Paño 4)
In: F1
Type - Description: Bovedilla de hormigón; PredefinedType: USERDEFINED
Pset_BuildingElementProxyCommon - Reference: Bovedilla 5-1 (Paño 4); sets with these values: 2
Pset_ProvisionForVoid - Shape: Undefined; Width: 0.58 m; Height: 0.25 m; Depth: 0.25 m

# IfcBuildingElementProxy: Bovedilla 5-10 (Paño 1)
In: Depósito_
Type - Description: Bovedilla de hormigón; PredefinedType: USERDEFINED
Pset_BuildingElementProxyCommon - Reference: Bovedilla 5-10 (Paño 1); sets with these values: 2
Pset_ProvisionForVoid - Shape: Undefined

# IfcBuildingElementProxy: Bovedilla 5-10 (Paño 2) (2)
Type - Description: Bovedilla de hormigón; PredefinedType: USERDEFINED
Pset_BuildingElementProxyCommon - Reference: Bovedilla 5-10 (Paño 2); sets with these values: 2
Pset_ProvisionForVoid - Shape: Undefined
Name | In
Bovedilla 5-10 (Paño 2) | Depósito_
Bovedilla 5-10 (Paño 2) | PB | Pset_ProvisionForVoid - Width: 0.58 m; Height: 0.25 m; Depth: 0.25 m

# IfcBuildingElementProxy: Bovedilla 5-10 (Paño 4)
In: F1
Type - Description: Bovedilla de hormigón; PredefinedType: USERDEFINED
Pset_BuildingElementProxyCommon - Reference: Bovedilla 5-10 (Paño 4); sets with these values: 2
Pset_ProvisionForVoid - Shape: Undefined; Width: 0.58 m; Height: 0.25 m; Depth: 0.25 m

# IfcBuildingElementProxy: Bovedilla 5-11 (Paño 1)
In: Depósito_
Type - Description: Bovedilla de hormigón; PredefinedType: USERDEFINED
Pset_BuildingElementProxyCommon - Reference: Bovedilla 5-11 (Paño 1); sets with these values: 2
Pset_ProvisionForVoid - Shape: Undefined

# IfcBuildingElementProxy: Bovedilla 5-11 (Paño 2) (2)
Type - Description: Bovedilla de hormigón; PredefinedType: USERDEFINED
Pset_BuildingElementProxyCommon - Reference: Bovedilla 5-11 (Paño 2); sets with these values: 2
Pset_ProvisionForVoid - Shape: Undefined
Name | In
Bovedilla 5-11 (Paño 2) | Depósito_
Bovedilla 5-11 (Paño 2) | PB | Pset_ProvisionForVoid - Width: 0.58 m; Height: 0.25 m; Depth: 0.25 m

# IfcBuildingElementProxy: Bovedilla 5-11 (Paño 4)
In: F1
Type - Description: Bovedilla de hormigón; PredefinedType: USERDEFINED
Pset_BuildingElementProxyCommon - Reference: Bovedilla 5-11 (Paño 4); sets with these values: 2
Pset_ProvisionForVoid - Shape: Undefined; Width: 0.58 m; Height: 0.25 m; Depth: 0.25 m

# IfcBuildingElementProxy: Bovedilla 5-12 (Paño 1)
In: Depósito_
Type - Description: Bovedilla de hormigón; PredefinedType: USERDEFINED
Pset_BuildingElementProxyCommon - Reference: Bovedilla 5-12 (Paño 1); sets with these values: 2
Pset_ProvisionForVoid - Shape: Undefined

# IfcBuildingElementProxy: Bovedilla 5-12 (Paño 2) (2)
Type - Description: Bovedilla de hormigón; PredefinedType: USERDEFINED
Pset_BuildingElementProxyCommon - Reference: Bovedilla 5-12 (Paño 2); sets with these values: 2
Pset_ProvisionForVoid - Shape: Undefined
Name | In
Bovedilla 5-12 (Paño 2) | Depósito_
Bovedilla 5-12 (Paño 2) | PB | Pset_ProvisionForVoid - Width: 0.58 m; Height: 0.25 m; Depth: 0.25 m

# IfcBuildingElementProxy: Bovedilla 5-12 (Paño 4)
In: F1
Type - Description: Bovedilla de hormigón; PredefinedType: USERDEFINED
Pset_BuildingElementProxyCommon - Reference: Bovedilla 5-12 (Paño 4); sets with these values: 2
Pset_ProvisionForVoid - Shape: Undefined; Width: 0.58 m; Height: 0.25 m; Depth: 0.25 m

# IfcBuildingElementProxy: Bovedilla 5-13 (Paño 1)
In: Depósito_
Type - Description: Bovedilla de hormigón; PredefinedType: USERDEFINED
Pset_BuildingElementProxyCommon - Reference: Bovedilla 5-13 (Paño 1); sets with these values: 2
Pset_ProvisionForVoid - Shape: Undefined

# IfcBuildingElementProxy: Bovedilla 5-13 (Paño 2) (2)
Type - Description: Bovedilla de hormigón; PredefinedType: USERDEFINED
Pset_BuildingElementProxyCommon - Reference: Bovedilla 5-13 (Paño 2); sets with these values: 2
Pset_ProvisionForVoid - Shape: Undefined
Name | In
Bovedilla 5-13 (Paño 2) | Depósito_
Bovedilla 5-13 (Paño 2) | PB | Pset_ProvisionForVoid - Width: 0.58 m; Height: 0.25 m; Depth: 0.25 m

# IfcBuildingElementProxy: Bovedilla 5-13 (Paño 4)
In: F1
Type - Description: Bovedilla de hormigón; PredefinedType: USERDEFINED
Pset_BuildingElementProxyCommon - Reference: Bovedilla 5-13 (Paño 4); sets with these values: 2
Pset_ProvisionForVoid - Shape: Undefined; Width: 0.58 m; Height: 0.25 m; Depth: 0.25 m

# IfcBuildingElementProxy: Bovedilla 5-14 (Paño 2)
In: PB
Type - Description: Bovedilla de hormigón; PredefinedType: USERDEFINED
Pset_BuildingElementProxyCommon - Reference: Bovedilla 5-14 (Paño 2); sets with these values: 2
Pset_ProvisionForVoid - Shape: Undefined; Width: 0.58 m; Height: 0.25 m; Depth: 0.25 m

# IfcBuildingElementProxy: Bovedilla 5-14 (Paño 4)
In: F1
Type - Description: Bovedilla de hormigón; PredefinedType: USERDEFINED
Pset_BuildingElementProxyCommon - Reference: Bovedilla 5-14 (Paño 4); sets with these values: 2
Pset_ProvisionForVoid - Shape: Undefined; Width: 0.58 m; Height: 0.25 m; Depth: 0.25 m

# IfcBuildingElementProxy: Bovedilla 5-15 (Paño 4)
In: F1
Type - Description: Bovedilla de hormigón; PredefinedType: USERDEFINED
Pset_BuildingElementProxyCommon - Reference: Bovedilla 5-15 (Paño 4); sets with these values: 2
Pset_ProvisionForVoid - Shape: Undefined; Width: 0.58 m; Height: 0.25 m; Depth: 0.25 m

# IfcBuildingElementProxy: Bovedilla 5-16 (Paño 4)
In: F1
Type - Description: Bovedilla de hormigón; PredefinedType: USERDEFINED
Pset_BuildingElementProxyCommon - Reference: Bovedilla 5-16 (Paño 4); sets with these values: 2
Pset_ProvisionForVoid - Shape: Undefined; Width: 0.58 m; Height: 0.25 m; Depth: 0.25 m

# IfcBuildingElementProxy: Bovedilla 5-2 (Paño 1)
In: Depósito_
Type - Description: Bovedilla de hormigón; PredefinedType: USERDEFINED
Pset_BuildingElementProxyCommon - Reference: Bovedilla 5-2 (Paño 1); sets with these values: 2
Pset_ProvisionForVoid - Shape: Undefined

# IfcBuildingElementProxy: Bovedilla 5-2 (Paño 2) (2)
Type - Description: Bovedilla de hormigón; PredefinedType: USERDEFINED
Pset_BuildingElementProxyCommon - Reference: Bovedilla 5-2 (Paño 2); sets with these values: 2
Pset_ProvisionForVoid - Shape: Undefined
Name | In
Bovedilla 5-2 (Paño 2) | Depósito_
Bovedilla 5-2 (Paño 2) | PB | Pset_ProvisionForVoid - Width: 0.58 m; Height: 0.25 m; Depth: 0.25 m

# IfcBuildingElementProxy: Bovedilla 5-2 (Paño 4)
In: F1
Type - Description: Bovedilla de hormigón; PredefinedType: USERDEFINED
Pset_BuildingElementProxyCommon - Reference: Bovedilla 5-2 (Paño 4); sets with these values: 2
Pset_ProvisionForVoid - Shape: Undefined; Width: 0.58 m; Height: 0.25 m; Depth: 0.25 m

# IfcBuildingElementProxy: Bovedilla 5-3 (Paño 1)
In: Depósito_
Type - Description: Bovedilla de hormigón; PredefinedType: USERDEFINED
Pset_BuildingElementProxyCommon - Reference: Bovedilla 5-3 (Paño 1); sets with these values: 2
Pset_ProvisionForVoid - Shape: Undefined

# IfcBuildingElementProxy: Bovedilla 5-3 (Paño 2) (2)
Type - Description: Bovedilla de hormigón; PredefinedType: USERDEFINED
Pset_BuildingElementProxyCommon - Reference: Bovedilla 5-3 (Paño 2); sets with these values: 2
Pset_ProvisionForVoid - Shape: Undefined
Name | In
Bovedilla 5-3 (Paño 2) | Depósito_
Bovedilla 5-3 (Paño 2) | PB | Pset_ProvisionForVoid - Width: 0.58 m; Height: 0.25 m; Depth: 0.25 m

# IfcBuildingElementProxy: Bovedilla 5-3 (Paño 4)
In: F1
Type - Description: Bovedilla de hormigón; PredefinedType: USERDEFINED
Pset_BuildingElementProxyCommon - Reference: Bovedilla 5-3 (Paño 4); sets with these values: 2
Pset_ProvisionForVoid - Shape: Undefined; Width: 0.58 m; Height: 0.25 m; Depth: 0.25 m

# IfcBuildingElementProxy: Bovedilla 5-4 (Paño 1)
In: Depósito_
Type - Description: Bovedilla de hormigón; PredefinedType: USERDEFINED
Pset_BuildingElementProxyCommon - Reference: Bovedilla 5-4 (Paño 1); sets with these values: 2
Pset_ProvisionForVoid - Shape: Undefined

# IfcBuildingElementProxy: Bovedilla 5-4 (Paño 2) (2)
Type - Description: Bovedilla de hormigón; PredefinedType: USERDEFINED
Pset_BuildingElementProxyCommon - Reference: Bovedilla 5-4 (Paño 2); sets with these values: 2
Pset_ProvisionForVoid - Shape: Undefined
Name | In
Bovedilla 5-4 (Paño 2) | Depósito_
Bovedilla 5-4 (Paño 2) | PB | Pset_ProvisionForVoid - Width: 0.58 m; Height: 0.25 m; Depth: 0.25 m

# IfcBuildingElementProxy: Bovedilla 5-4 (Paño 4)
In: F1
Type - Description: Bovedilla de hormigón; PredefinedType: USERDEFINED
Pset_BuildingElementProxyCommon - Reference: Bovedilla 5-4 (Paño 4); sets with these values: 2
Pset_ProvisionForVoid - Shape: Undefined; Width: 0.58 m; Height: 0.25 m; Depth: 0.25 m

# IfcBuildingElementProxy: Bovedilla 5-5 (Paño 1)
In: Depósito_
Type - Description: Bovedilla de hormigón; PredefinedType: USERDEFINED
Pset_BuildingElementProxyCommon - Reference: Bovedilla 5-5 (Paño 1); sets with these values: 2
Pset_ProvisionForVoid - Shape: Undefined

# IfcBuildingElementProxy: Bovedilla 5-5 (Paño 2) (2)
Type - Description: Bovedilla de hormigón; PredefinedType: USERDEFINED
Pset_BuildingElementProxyCommon - Reference: Bovedilla 5-5 (Paño 2); sets with these values: 2
Pset_ProvisionForVoid - Shape: Undefined
Name | In
Bovedilla 5-5 (Paño 2) | Depósito_
Bovedilla 5-5 (Paño 2) | PB | Pset_ProvisionForVoid - Width: 0.58 m; Height: 0.25 m; Depth: 0.25 m

# IfcBuildingElementProxy: Bovedilla 5-5 (Paño 4)
In: F1
Type - Description: Bovedilla de hormigón; PredefinedType: USERDEFINED
Pset_BuildingElementProxyCommon - Reference: Bovedilla 5-5 (Paño 4); sets with these values: 2
Pset_ProvisionForVoid - Shape: Undefined; Width: 0.58 m; Height: 0.25 m; Depth: 0.25 m

# IfcBuildingElementProxy: Bovedilla 5-6 (Paño 1)
In: Depósito_
Type - Description: Bovedilla de hormigón; PredefinedType: USERDEFINED
Pset_BuildingElementProxyCommon - Reference: Bovedilla 5-6 (Paño 1); sets with these values: 2
Pset_ProvisionForVoid - Shape: Undefined

# IfcBuildingElementProxy: Bovedilla 5-6 (Paño 2) (2)
Type - Description: Bovedilla de hormigón; PredefinedType: USERDEFINED
Pset_BuildingElementProxyCommon - Reference: Bovedilla 5-6 (Paño 2); sets with these values: 2
Pset_ProvisionForVoid - Shape: Undefined
Name | In
Bovedilla 5-6 (Paño 2) | Depósito_
Bovedilla 5-6 (Paño 2) | PB | Pset_ProvisionForVoid - Width: 0.58 m; Height: 0.25 m; Depth: 0.25 m

# IfcBuildingElementProxy: Bovedilla 5-6 (Paño 4)
In: F1
Type - Description: Bovedilla de hormigón; PredefinedType: USERDEFINED
Pset_BuildingElementProxyCommon - Reference: Bovedilla 5-6 (Paño 4); sets with these values: 2
Pset_ProvisionForVoid - Shape: Undefined; Width: 0.58 m; Height: 0.25 m; Depth: 0.25 m

# IfcBuildingElementProxy: Bovedilla 5-7 (Paño 1)
In: Depósito_
Type - Description: Bovedilla de hormigón; PredefinedType: USERDEFINED
Pset_BuildingElementProxyCommon - Reference: Bovedilla 5-7 (Paño 1); sets with these values: 2
Pset_ProvisionForVoid - Shape: Undefined

# IfcBuildingElementProxy: Bovedilla 5-7 (Paño 2) (2)
Type - Description: Bovedilla de hormigón; PredefinedType: USERDEFINED
Pset_BuildingElementProxyCommon - Reference: Bovedilla 5-7 (Paño 2); sets with these values: 2
Pset_ProvisionForVoid - Shape: Undefined
Name | In
Bovedilla 5-7 (Paño 2) | Depósito_
Bovedilla 5-7 (Paño 2) | PB | Pset_ProvisionForVoid - Width: 0.58 m; Height: 0.25 m; Depth: 0.25 m

# IfcBuildingElementProxy: Bovedilla 5-7 (Paño 4)
In: F1
Type - Description: Bovedilla de hormigón; PredefinedType: USERDEFINED
Pset_BuildingElementProxyCommon - Reference: Bovedilla 5-7 (Paño 4); sets with these values: 2
Pset_ProvisionForVoid - Shape: Undefined; Width: 0.58 m; Height: 0.25 m; Depth: 0.25 m

# IfcBuildingElementProxy: Bovedilla 5-8 (Paño 1)
In: Depósito_
Type - Description: Bovedilla de hormigón; PredefinedType: USERDEFINED
Pset_BuildingElementProxyCommon - Reference: Bovedilla 5-8 (Paño 1); sets with these values: 2
Pset_ProvisionForVoid - Shape: Undefined

# IfcBuildingElementProxy: Bovedilla 5-8 (Paño 2) (2)
Type - Description: Bovedilla de hormigón; PredefinedType: USERDEFINED
Pset_BuildingElementProxyCommon - Reference: Bovedilla 5-8 (Paño 2); sets with these values: 2
Pset_ProvisionForVoid - Shape: Undefined
Name | In
Bovedilla 5-8 (Paño 2) | Depósito_
Bovedilla 5-8 (Paño 2) | PB | Pset_ProvisionForVoid - Width: 0.58 m; Height: 0.25 m; Depth: 0.25 m

# IfcBuildingElementProxy: Bovedilla 5-8 (Paño 4)
In: F1
Type - Description: Bovedilla de hormigón; PredefinedType: USERDEFINED
Pset_BuildingElementProxyCommon - Reference: Bovedilla 5-8 (Paño 4); sets with these values: 2
Pset_ProvisionForVoid - Shape: Undefined; Width: 0.58 m; Height: 0.25 m; Depth: 0.25 m

# IfcBuildingElementProxy: Bovedilla 5-9 (Paño 1)
In: Depósito_
Type - Description: Bovedilla de hormigón; PredefinedType: USERDEFINED
Pset_BuildingElementProxyCommon - Reference: Bovedilla 5-9 (Paño 1); sets with these values: 2
Pset_ProvisionForVoid - Shape: Undefined

# IfcBuildingElementProxy: Bovedilla 5-9 (Paño 2) (2)
Type - Description: Bovedilla de hormigón; PredefinedType: USERDEFINED
Pset_BuildingElementProxyCommon - Reference: Bovedilla 5-9 (Paño 2); sets with these values: 2
Pset_ProvisionForVoid - Shape: Undefined
Name | In
Bovedilla 5-9 (Paño 2) | Depósito_
Bovedilla 5-9 (Paño 2) | PB | Pset_ProvisionForVoid - Width: 0.58 m; Height: 0.25 m; Depth: 0.25 m

# IfcBuildingElementProxy: Bovedilla 5-9 (Paño 4)
In: F1
Type - Description: Bovedilla de hormigón; PredefinedType: USERDEFINED
Pset_BuildingElementProxyCommon - Reference: Bovedilla 5-9 (Paño 4); sets with these values: 2
Pset_ProvisionForVoid - Shape: Undefined; Width: 0.58 m; Height: 0.25 m; Depth: 0.25 m

# IfcBuildingElementProxy: Bovedilla 6-1 (Paño 1)
In: Depósito_
Type - Description: Bovedilla de hormigón; PredefinedType: USERDEFINED
Pset_BuildingElementProxyCommon - Reference: Bovedilla 6-1 (Paño 1); sets with these values: 2
Pset_ProvisionForVoid - Shape: Undefined

# IfcBuildingElementProxy: Bovedilla 6-1 (Paño 2) (2)
Type - Description: Bovedilla de hormigón; PredefinedType: USERDEFINED
Pset_BuildingElementProxyCommon - Reference: Bovedilla 6-1 (Paño 2); sets with these values: 2
Pset_ProvisionForVoid - Shape: Undefined
Name | In
Bovedilla 6-1 (Paño 2) | Depósito_
Bovedilla 6-1 (Paño 2) | PB | Pset_ProvisionForVoid - Width: 0.58 m; Height: 0.25 m; Depth: 0.25 m

# IfcBuildingElementProxy: Bovedilla 6-1 (Paño 4)
In: F1
Type - Description: Bovedilla de hormigón; PredefinedType: USERDEFINED
Pset_BuildingElementProxyCommon - Reference: Bovedilla 6-1 (Paño 4); sets with these values: 2
Pset_ProvisionForVoid - Shape: Undefined; Width: 0.58 m; Height: 0.25 m; Depth: 0.25 m

# IfcBuildingElementProxy: Bovedilla 6-10 (Paño 1)
In: Depósito_
Type - Description: Bovedilla de hormigón; PredefinedType: USERDEFINED
Pset_BuildingElementProxyCommon - Reference: Bovedilla 6-10 (Paño 1); sets with these values: 2
Pset_ProvisionForVoid - Shape: Undefined

# IfcBuildingElementProxy: Bovedilla 6-10 (Paño 2) (2)
Type - Description: Bovedilla de hormigón; PredefinedType: USERDEFINED
Pset_BuildingElementProxyCommon - Reference: Bovedilla 6-10 (Paño 2); sets with these values: 2
Pset_ProvisionForVoid - Shape: Undefined
Name | In
Bovedilla 6-10 (Paño 2) | Depósito_
Bovedilla 6-10 (Paño 2) | PB | Pset_ProvisionForVoid - Width: 0.58 m; Height: 0.25 m; Depth: 0.25 m

# IfcBuildingElementProxy: Bovedilla 6-10 (Paño 4)
In: F1
Type - Description: Bovedilla de hormigón; PredefinedType: USERDEFINED
Pset_BuildingElementProxyCommon - Reference: Bovedilla 6-10 (Paño 4); sets with these values: 2
Pset_ProvisionForVoid - Shape: Undefined; Width: 0.58 m; Height: 0.25 m; Depth: 0.25 m

# IfcBuildingElementProxy: Bovedilla 6-11 (Paño 1)
In: Depósito_
Type - Description: Bovedilla de hormigón; PredefinedType: USERDEFINED
Pset_BuildingElementProxyCommon - Reference: Bovedilla 6-11 (Paño 1); sets with these values: 2
Pset_ProvisionForVoid - Shape: Undefined

# IfcBuildingElementProxy: Bovedilla 6-11 (Paño 2) (2)
Type - Description: Bovedilla de hormigón; PredefinedType: USERDEFINED
Pset_BuildingElementProxyCommon - Reference: Bovedilla 6-11 (Paño 2); sets with these values: 2
Pset_ProvisionForVoid - Shape: Undefined
Name | In
Bovedilla 6-11 (Paño 2) | Depósito_
Bovedilla 6-11 (Paño 2) | PB | Pset_ProvisionForVoid - Width: 0.58 m; Height: 0.25 m; Depth: 0.25 m

# IfcBuildingElementProxy: Bovedilla 6-11 (Paño 4)
In: F1
Type - Description: Bovedilla de hormigón; PredefinedType: USERDEFINED
Pset_BuildingElementProxyCommon - Reference: Bovedilla 6-11 (Paño 4); sets with these values: 2
Pset_ProvisionForVoid - Shape: Undefined; Width: 0.58 m; Height: 0.25 m; Depth: 0.25 m

# IfcBuildingElementProxy: Bovedilla 6-12 (Paño 1)
In: Depósito_
Type - Description: Bovedilla de hormigón; PredefinedType: USERDEFINED
Pset_BuildingElementProxyCommon - Reference: Bovedilla 6-12 (Paño 1); sets with these values: 2
Pset_ProvisionForVoid - Shape: Undefined

# IfcBuildingElementProxy: Bovedilla 6-12 (Paño 2) (2)
Type - Description: Bovedilla de hormigón; PredefinedType: USERDEFINED
Pset_BuildingElementProxyCommon - Reference: Bovedilla 6-12 (Paño 2); sets with these values: 2
Pset_ProvisionForVoid - Shape: Undefined
Name | In
Bovedilla 6-12 (Paño 2) | Depósito_
Bovedilla 6-12 (Paño 2) | PB | Pset_ProvisionForVoid - Width: 0.58 m; Height: 0.25 m; Depth: 0.25 m

# IfcBuildingElementProxy: Bovedilla 6-12 (Paño 4)
In: F1
Type - Description: Bovedilla de hormigón; PredefinedType: USERDEFINED
Pset_BuildingElementProxyCommon - Reference: Bovedilla 6-12 (Paño 4); sets with these values: 2
Pset_ProvisionForVoid - Shape: Undefined; Width: 0.58 m; Height: 0.25 m; Depth: 0.25 m

# IfcBuildingElementProxy: Bovedilla 6-13 (Paño 1)
In: Depósito_
Type - Description: Bovedilla de hormigón; PredefinedType: USERDEFINED
Pset_BuildingElementProxyCommon - Reference: Bovedilla 6-13 (Paño 1); sets with these values: 2
Pset_ProvisionForVoid - Shape: Undefined

# IfcBuildingElementProxy: Bovedilla 6-13 (Paño 2) (2)
Type - Description: Bovedilla de hormigón; PredefinedType: USERDEFINED
Pset_BuildingElementProxyCommon - Reference: Bovedilla 6-13 (Paño 2); sets with these values: 2
Pset_ProvisionForVoid - Shape: Undefined
Name | In
Bovedilla 6-13 (Paño 2) | Depósito_
Bovedilla 6-13 (Paño 2) | PB | Pset_ProvisionForVoid - Width: 0.58 m; Height: 0.25 m; Depth: 0.25 m

# IfcBuildingElementProxy: Bovedilla 6-13 (Paño 4)
In: F1
Type - Description: Bovedilla de hormigón; PredefinedType: USERDEFINED
Pset_BuildingElementProxyCommon - Reference: Bovedilla 6-13 (Paño 4); sets with these values: 2
Pset_ProvisionForVoid - Shape: Undefined; Width: 0.58 m; Height: 0.25 m; Depth: 0.25 m

# IfcBuildingElementProxy: Bovedilla 6-14 (Paño 2)
In: PB
Type - Description: Bovedilla de hormigón; PredefinedType: USERDEFINED
Pset_BuildingElementProxyCommon - Reference: Bovedilla 6-14 (Paño 2); sets with these values: 2
Pset_ProvisionForVoid - Shape: Undefined; Width: 0.58 m; Height: 0.25 m; Depth: 0.25 m

# IfcBuildingElementProxy: Bovedilla 6-14 (Paño 4)
In: F1
Type - Description: Bovedilla de hormigón; PredefinedType: USERDEFINED
Pset_BuildingElementProxyCommon - Reference: Bovedilla 6-14 (Paño 4); sets with these values: 2
Pset_ProvisionForVoid - Shape: Undefined; Width: 0.58 m; Height: 0.25 m; Depth: 0.25 m

# IfcBuildingElementProxy: Bovedilla 6-15 (Paño 4)
In: F1
Type - Description: Bovedilla de hormigón; PredefinedType: USERDEFINED
Pset_BuildingElementProxyCommon - Reference: Bovedilla 6-15 (Paño 4); sets with these values: 2
Pset_ProvisionForVoid - Shape: Undefined; Width: 0.58 m; Height: 0.25 m; Depth: 0.25 m

# IfcBuildingElementProxy: Bovedilla 6-16 (Paño 4)
In: F1
Type - Description: Bovedilla de hormigón; PredefinedType: USERDEFINED
Pset_BuildingElementProxyCommon - Reference: Bovedilla 6-16 (Paño 4); sets with these values: 2
Pset_ProvisionForVoid - Shape: Undefined; Width: 0.58 m; Height: 0.25 m; Depth: 0.25 m

# IfcBuildingElementProxy: Bovedilla 6-2 (Paño 1)
In: Depósito_
Type - Description: Bovedilla de hormigón; PredefinedType: USERDEFINED
Pset_BuildingElementProxyCommon - Reference: Bovedilla 6-2 (Paño 1); sets with these values: 2
Pset_ProvisionForVoid - Shape: Undefined

# IfcBuildingElementProxy: Bovedilla 6-2 (Paño 2) (2)
Type - Description: Bovedilla de hormigón; PredefinedType: USERDEFINED
Pset_BuildingElementProxyCommon - Reference: Bovedilla 6-2 (Paño 2); sets with these values: 2
Pset_ProvisionForVoid - Shape: Undefined
Name | In
Bovedilla 6-2 (Paño 2) | Depósito_
Bovedilla 6-2 (Paño 2) | PB | Pset_ProvisionForVoid - Width: 0.58 m; Height: 0.25 m; Depth: 0.25 m

# IfcBuildingElementProxy: Bovedilla 6-2 (Paño 4)
In: F1
Type - Description: Bovedilla de hormigón; PredefinedType: USERDEFINED
Pset_BuildingElementProxyCommon - Reference: Bovedilla 6-2 (Paño 4); sets with these values: 2
Pset_ProvisionForVoid - Shape: Undefined; Width: 0.58 m; Height: 0.25 m; Depth: 0.25 m

# IfcBuildingElementProxy: Bovedilla 6-3 (Paño 1)
In: Depósito_
Type - Description: Bovedilla de hormigón; PredefinedType: USERDEFINED
Pset_BuildingElementProxyCommon - Reference: Bovedilla 6-3 (Paño 1); sets with these values: 2
Pset_ProvisionForVoid - Shape: Undefined

# IfcBuildingElementProxy: Bovedilla 6-3 (Paño 2) (2)
Type - Description: Bovedilla de hormigón; PredefinedType: USERDEFINED
Pset_BuildingElementProxyCommon - Reference: Bovedilla 6-3 (Paño 2); sets with these values: 2
Pset_ProvisionForVoid - Shape: Undefined
Name | In
Bovedilla 6-3 (Paño 2) | Depósito_
Bovedilla 6-3 (Paño 2) | PB | Pset_ProvisionForVoid - Width: 0.58 m; Height: 0.25 m; Depth: 0.25 m

# IfcBuildingElementProxy: Bovedilla 6-3 (Paño 4)
In: F1
Type - Description: Bovedilla de hormigón; PredefinedType: USERDEFINED
Pset_BuildingElementProxyCommon - Reference: Bovedilla 6-3 (Paño 4); sets with these values: 2
Pset_ProvisionForVoid - Shape: Undefined; Width: 0.58 m; Height: 0.25 m; Depth: 0.25 m

# IfcBuildingElementProxy: Bovedilla 6-4 (Paño 1)
In: Depósito_
Type - Description: Bovedilla de hormigón; PredefinedType: USERDEFINED
Pset_BuildingElementProxyCommon - Reference: Bovedilla 6-4 (Paño 1); sets with these values: 2
Pset_ProvisionForVoid - Shape: Undefined

# IfcBuildingElementProxy: Bovedilla 6-4 (Paño 2) (2)
Type - Description: Bovedilla de hormigón; PredefinedType: USERDEFINED
Pset_BuildingElementProxyCommon - Reference: Bovedilla 6-4 (Paño 2); sets with these values: 2
Pset_ProvisionForVoid - Shape: Undefined
Name | In
Bovedilla 6-4 (Paño 2) | Depósito_
Bovedilla 6-4 (Paño 2) | PB | Pset_ProvisionForVoid - Width: 0.58 m; Height: 0.25 m; Depth: 0.25 m

# IfcBuildingElementProxy: Bovedilla 6-4 (Paño 4)
In: F1
Type - Description: Bovedilla de hormigón; PredefinedType: USERDEFINED
Pset_BuildingElementProxyCommon - Reference: Bovedilla 6-4 (Paño 4); sets with these values: 2
Pset_ProvisionForVoid - Shape: Undefined; Width: 0.58 m; Height: 0.25 m; Depth: 0.25 m

# IfcBuildingElementProxy: Bovedilla 6-5 (Paño 1)
In: Depósito_
Type - Description: Bovedilla de hormigón; PredefinedType: USERDEFINED
Pset_BuildingElementProxyCommon - Reference: Bovedilla 6-5 (Paño 1); sets with these values: 2
Pset_ProvisionForVoid - Shape: Undefined

# IfcBuildingElementProxy: Bovedilla 6-5 (Paño 2) (2)
Type - Description: Bovedilla de hormigón; PredefinedType: USERDEFINED
Pset_BuildingElementProxyCommon - Reference: Bovedilla 6-5 (Paño 2); sets with these values: 2
Pset_ProvisionForVoid - Shape: Undefined
Name | In
Bovedilla 6-5 (Paño 2) | Depósito_
Bovedilla 6-5 (Paño 2) | PB | Pset_ProvisionForVoid - Width: 0.58 m; Height: 0.25 m; Depth: 0.25 m

# IfcBuildingElementProxy: Bovedilla 6-5 (Paño 4)
In: F1
Type - Description: Bovedilla de hormigón; PredefinedType: USERDEFINED
Pset_BuildingElementProxyCommon - Reference: Bovedilla 6-5 (Paño 4); sets with these values: 2
Pset_ProvisionForVoid - Shape: Undefined; Width: 0.58 m; Height: 0.25 m; Depth: 0.25 m

# IfcBuildingElementProxy: Bovedilla 6-6 (Paño 1)
In: Depósito_
Type - Description: Bovedilla de hormigón; PredefinedType: USERDEFINED
Pset_BuildingElementProxyCommon - Reference: Bovedilla 6-6 (Paño 1); sets with these values: 2
Pset_ProvisionForVoid - Shape: Undefined

# IfcBuildingElementProxy: Bovedilla 6-6 (Paño 2) (2)
Type - Description: Bovedilla de hormigón; PredefinedType: USERDEFINED
Pset_BuildingElementProxyCommon - Reference: Bovedilla 6-6 (Paño 2); sets with these values: 2
Pset_ProvisionForVoid - Shape: Undefined
Name | In
Bovedilla 6-6 (Paño 2) | Depósito_
Bovedilla 6-6 (Paño 2) | PB | Pset_ProvisionForVoid - Width: 0.58 m; Height: 0.25 m; Depth: 0.25 m

# IfcBuildingElementProxy: Bovedilla 6-6 (Paño 4)
In: F1
Type - Description: Bovedilla de hormigón; PredefinedType: USERDEFINED
Pset_BuildingElementProxyCommon - Reference: Bovedilla 6-6 (Paño 4); sets with these values: 2
Pset_ProvisionForVoid - Shape: Undefined; Width: 0.58 m; Height: 0.25 m; Depth: 0.25 m

# IfcBuildingElementProxy: Bovedilla 6-7 (Paño 1)
In: Depósito_
Type - Description: Bovedilla de hormigón; PredefinedType: USERDEFINED
Pset_BuildingElementProxyCommon - Reference: Bovedilla 6-7 (Paño 1); sets with these values: 2
Pset_ProvisionForVoid - Shape: Undefined

# IfcBuildingElementProxy: Bovedilla 6-7 (Paño 2) (2)
Type - Description: Bovedilla de hormigón; PredefinedType: USERDEFINED
Pset_BuildingElementProxyCommon - Reference: Bovedilla 6-7 (Paño 2); sets with these values: 2
Pset_ProvisionForVoid - Shape: Undefined
Name | In
Bovedilla 6-7 (Paño 2) | Depósito_
Bovedilla 6-7 (Paño 2) | PB | Pset_ProvisionForVoid - Width: 0.58 m; Height: 0.25 m; Depth: 0.25 m

# IfcBuildingElementProxy: Bovedilla 6-7 (Paño 4)
In: F1
Type - Description: Bovedilla de hormigón; PredefinedType: USERDEFINED
Pset_BuildingElementProxyCommon - Reference: Bovedilla 6-7 (Paño 4); sets with these values: 2
Pset_ProvisionForVoid - Shape: Undefined; Width: 0.58 m; Height: 0.25 m; Depth: 0.25 m

# IfcBuildingElementProxy: Bovedilla 6-8 (Paño 1)
In: Depósito_
Type - Description: Bovedilla de hormigón; PredefinedType: USERDEFINED
Pset_BuildingElementProxyCommon - Reference: Bovedilla 6-8 (Paño 1); sets with these values: 2
Pset_ProvisionForVoid - Shape: Undefined

# IfcBuildingElementProxy: Bovedilla 6-8 (Paño 2) (2)
Type - Description: Bovedilla de hormigón; PredefinedType: USERDEFINED
Pset_BuildingElementProxyCommon - Reference: Bovedilla 6-8 (Paño 2); sets with these values: 2
Pset_ProvisionForVoid - Shape: Undefined
Name | In
Bovedilla 6-8 (Paño 2) | Depósito_
Bovedilla 6-8 (Paño 2) | PB | Pset_ProvisionForVoid - Width: 0.58 m; Height: 0.25 m; Depth: 0.25 m

# IfcBuildingElementProxy: Bovedilla 6-8 (Paño 4)
In: F1
Type - Description: Bovedilla de hormigón; PredefinedType: USERDEFINED
Pset_BuildingElementProxyCommon - Reference: Bovedilla 6-8 (Paño 4); sets with these values: 2
Pset_ProvisionForVoid - Shape: Undefined; Width: 0.58 m; Height: 0.25 m; Depth: 0.25 m

# IfcBuildingElementProxy: Bovedilla 6-9 (Paño 1)
In: Depósito_
Type - Description: Bovedilla de hormigón; PredefinedType: USERDEFINED
Pset_BuildingElementProxyCommon - Reference: Bovedilla 6-9 (Paño 1); sets with these values: 2
Pset_ProvisionForVoid - Shape: Undefined

# IfcBuildingElementProxy: Bovedilla 6-9 (Paño 2) (2)
Type - Description: Bovedilla de hormigón; PredefinedType: USERDEFINED
Pset_BuildingElementProxyCommon - Reference: Bovedilla 6-9 (Paño 2); sets with these values: 2
Pset_ProvisionForVoid - Shape: Undefined
Name | In
Bovedilla 6-9 (Paño 2) | Depósito_
Bovedilla 6-9 (Paño 2) | PB | Pset_ProvisionForVoid - Width: 0.58 m; Height: 0.25 m; Depth: 0.25 m

# IfcBuildingElementProxy: Bovedilla 6-9 (Paño 4)
In: F1
Type - Description: Bovedilla de hormigón; PredefinedType: USERDEFINED
Pset_BuildingElementProxyCommon - Reference: Bovedilla 6-9 (Paño 4); sets with these values: 2
Pset_ProvisionForVoid - Shape: Undefined; Width: 0.58 m; Height: 0.25 m; Depth: 0.25 m

# IfcBuildingElementProxy: Bovedilla 7-1 (Paño 2)
In: PB
Type - Description: Bovedilla de hormigón; PredefinedType: USERDEFINED
Pset_BuildingElementProxyCommon - Reference: Bovedilla 7-1 (Paño 2); sets with these values: 2
Pset_ProvisionForVoid - Shape: Undefined; Width: 0.58 m; Height: 0.25 m; Depth: 0.25 m

# IfcBuildingElementProxy: Bovedilla 7-1 (Paño 4)
In: F1
Type - Description: Bovedilla de hormigón; PredefinedType: USERDEFINED
Pset_BuildingElementProxyCommon - Reference: Bovedilla 7-1 (Paño 4); sets with these values: 2
Pset_ProvisionForVoid - Shape: Undefined; Width: 0.58 m; Height: 0.25 m; Depth: 0.25 m

# IfcBuildingElementProxy: Bovedilla 7-10 (Paño 2)
In: PB
Type - Description: Bovedilla de hormigón; PredefinedType: USERDEFINED
Pset_BuildingElementProxyCommon - Reference: Bovedilla 7-10 (Paño 2); sets with these values: 2
Pset_ProvisionForVoid - Shape: Undefined; Width: 0.58 m; Height: 0.25 m; Depth: 0.25 m

# IfcBuildingElementProxy: Bovedilla 7-10 (Paño 4)
In: F1
Type - Description: Bovedilla de hormigón; PredefinedType: USERDEFINED
Pset_BuildingElementProxyCommon - Reference: Bovedilla 7-10 (Paño 4); sets with these values: 2
Pset_ProvisionForVoid - Shape: Undefined; Width: 0.58 m; Height: 0.25 m; Depth: 0.25 m

# IfcBuildingElementProxy: Bovedilla 7-11 (Paño 2)
In: PB
Type - Description: Bovedilla de hormigón; PredefinedType: USERDEFINED
Pset_BuildingElementProxyCommon - Reference: Bovedilla 7-11 (Paño 2); sets with these values: 2
Pset_ProvisionForVoid - Shape: Undefined; Width: 0.58 m; Height: 0.25 m; Depth: 0.25 m

# IfcBuildingElementProxy: Bovedilla 7-11 (Paño 4)
In: F1
Type - Description: Bovedilla de hormigón; PredefinedType: USERDEFINED
Pset_BuildingElementProxyCommon - Reference: Bovedilla 7-11 (Paño 4); sets with these values: 2
Pset_ProvisionForVoid - Shape: Undefined; Width: 0.58 m; Height: 0.25 m; Depth: 0.25 m

# IfcBuildingElementProxy: Bovedilla 7-12 (Paño 2)
In: PB
Type - Description: Bovedilla de hormigón; PredefinedType: USERDEFINED
Pset_BuildingElementProxyCommon - Reference: Bovedilla 7-12 (Paño 2); sets with these values: 2
Pset_ProvisionForVoid - Shape: Undefined; Width: 0.58 m; Height: 0.25 m; Depth: 0.25 m

# IfcBuildingElementProxy: Bovedilla 7-12 (Paño 4)
In: F1
Type - Description: Bovedilla de hormigón; PredefinedType: USERDEFINED
Pset_BuildingElementProxyCommon - Reference: Bovedilla 7-12 (Paño 4); sets with these values: 2
Pset_ProvisionForVoid - Shape: Undefined; Width: 0.58 m; Height: 0.25 m; Depth: 0.25 m

# IfcBuildingElementProxy: Bovedilla 7-13 (Paño 2)
In: PB
Type - Description: Bovedilla de hormigón; PredefinedType: USERDEFINED
Pset_BuildingElementProxyCommon - Reference: Bovedilla 7-13 (Paño 2); sets with these values: 2
Pset_ProvisionForVoid - Shape: Undefined; Width: 0.58 m; Height: 0.25 m; Depth: 0.25 m

# IfcBuildingElementProxy: Bovedilla 7-13 (Paño 4)
In: F1
Type - Description: Bovedilla de hormigón; PredefinedType: USERDEFINED
Pset_BuildingElementProxyCommon - Reference: Bovedilla 7-13 (Paño 4); sets with these values: 2
Pset_ProvisionForVoid - Shape: Undefined; Width: 0.58 m; Height: 0.25 m; Depth: 0.25 m

# IfcBuildingElementProxy: Bovedilla 7-14 (Paño 2)
In: PB
Type - Description: Bovedilla de hormigón; PredefinedType: USERDEFINED
Pset_BuildingElementProxyCommon - Reference: Bovedilla 7-14 (Paño 2); sets with these values: 2
Pset_ProvisionForVoid - Shape: Undefined; Width: 0.58 m; Height: 0.25 m; Depth: 0.25 m

# IfcBuildingElementProxy: Bovedilla 7-14 (Paño 4)
In: F1
Type - Description: Bovedilla de hormigón; PredefinedType: USERDEFINED
Pset_BuildingElementProxyCommon - Reference: Bovedilla 7-14 (Paño 4); sets with these values: 2
Pset_ProvisionForVoid - Shape: Undefined; Width: 0.58 m; Height: 0.25 m; Depth: 0.25 m

# IfcBuildingElementProxy: Bovedilla 7-15 (Paño 4)
In: F1
Type - Description: Bovedilla de hormigón; PredefinedType: USERDEFINED
Pset_BuildingElementProxyCommon - Reference: Bovedilla 7-15 (Paño 4); sets with these values: 2
Pset_ProvisionForVoid - Shape: Undefined; Width: 0.58 m; Height: 0.25 m; Depth: 0.25 m

# IfcBuildingElementProxy: Bovedilla 7-16 (Paño 4)
In: F1
Type - Description: Bovedilla de hormigón; PredefinedType: USERDEFINED
Pset_BuildingElementProxyCommon - Reference: Bovedilla 7-16 (Paño 4); sets with these values: 2
Pset_ProvisionForVoid - Shape: Undefined; Width: 0.58 m; Height: 0.25 m; Depth: 0.25 m

# IfcBuildingElementProxy: Bovedilla 7-2 (Paño 2)
In: PB
Type - Description: Bovedilla de hormigón; PredefinedType: USERDEFINED
Pset_BuildingElementProxyCommon - Reference: Bovedilla 7-2 (Paño 2); sets with these values: 2
Pset_ProvisionForVoid - Shape: Undefined; Width: 0.58 m; Height: 0.25 m; Depth: 0.25 m

# IfcBuildingElementProxy: Bovedilla 7-2 (Paño 4)
In: F1
Type - Description: Bovedilla de hormigón; PredefinedType: USERDEFINED
Pset_BuildingElementProxyCommon - Reference: Bovedilla 7-2 (Paño 4); sets with these values: 2
Pset_ProvisionForVoid - Shape: Undefined; Width: 0.58 m; Height: 0.25 m; Depth: 0.25 m

# IfcBuildingElementProxy: Bovedilla 7-3 (Paño 2)
In: PB
Type - Description: Bovedilla de hormigón; PredefinedType: USERDEFINED
Pset_BuildingElementProxyCommon - Reference: Bovedilla 7-3 (Paño 2); sets with these values: 2
Pset_ProvisionForVoid - Shape: Undefined; Width: 0.58 m; Height: 0.25 m; Depth: 0.25 m

# IfcBuildingElementProxy: Bovedilla 7-3 (Paño 4)
In: F1
Type - Description: Bovedilla de hormigón; PredefinedType: USERDEFINED
Pset_BuildingElementProxyCommon - Reference: Bovedilla 7-3 (Paño 4); sets with these values: 2
Pset_ProvisionForVoid - Shape: Undefined; Width: 0.58 m; Height: 0.25 m; Depth: 0.25 m

# IfcBuildingElementProxy: Bovedilla 7-4 (Paño 2)
In: PB
Type - Description: Bovedilla de hormigón; PredefinedType: USERDEFINED
Pset_BuildingElementProxyCommon - Reference: Bovedilla 7-4 (Paño 2); sets with these values: 2
Pset_ProvisionForVoid - Shape: Undefined; Width: 0.58 m; Height: 0.25 m; Depth: 0.25 m

# IfcBuildingElementProxy: Bovedilla 7-4 (Paño 4)
In: F1
Type - Description: Bovedilla de hormigón; PredefinedType: USERDEFINED
Pset_BuildingElementProxyCommon - Reference: Bovedilla 7-4 (Paño 4); sets with these values: 2
Pset_ProvisionForVoid - Shape: Undefined; Width: 0.58 m; Height: 0.25 m; Depth: 0.25 m

# IfcBuildingElementProxy: Bovedilla 7-5 (Paño 2)
In: PB
Type - Description: Bovedilla de hormigón; PredefinedType: USERDEFINED
Pset_BuildingElementProxyCommon - Reference: Bovedilla 7-5 (Paño 2); sets with these values: 2
Pset_ProvisionForVoid - Shape: Undefined; Width: 0.58 m; Height: 0.25 m; Depth: 0.25 m

# IfcBuildingElementProxy: Bovedilla 7-5 (Paño 4)
In: F1
Type - Description: Bovedilla de hormigón; PredefinedType: USERDEFINED
Pset_BuildingElementProxyCommon - Reference: Bovedilla 7-5 (Paño 4); sets with these values: 2
Pset_ProvisionForVoid - Shape: Undefined; Width: 0.58 m; Height: 0.25 m; Depth: 0.25 m

# IfcBuildingElementProxy: Bovedilla 7-6 (Paño 2)
In: PB
Type - Description: Bovedilla de hormigón; PredefinedType: USERDEFINED
Pset_BuildingElementProxyCommon - Reference: Bovedilla 7-6 (Paño 2); sets with these values: 2
Pset_ProvisionForVoid - Shape: Undefined; Width: 0.58 m; Height: 0.25 m; Depth: 0.25 m

# IfcBuildingElementProxy: Bovedilla 7-6 (Paño 4)
In: F1
Type - Description: Bovedilla de hormigón; PredefinedType: USERDEFINED
Pset_BuildingElementProxyCommon - Reference: Bovedilla 7-6 (Paño 4); sets with these values: 2
Pset_ProvisionForVoid - Shape: Undefined; Width: 0.58 m; Height: 0.25 m; Depth: 0.25 m

# IfcBuildingElementProxy: Bovedilla 7-7 (Paño 2)
In: PB
Type - Description: Bovedilla de hormigón; PredefinedType: USERDEFINED
Pset_BuildingElementProxyCommon - Reference: Bovedilla 7-7 (Paño 2); sets with these values: 2
Pset_ProvisionForVoid - Shape: Undefined; Width: 0.58 m; Height: 0.25 m; Depth: 0.25 m

# IfcBuildingElementProxy: Bovedilla 7-7 (Paño 4)
In: F1
Type - Description: Bovedilla de hormigón; PredefinedType: USERDEFINED
Pset_BuildingElementProxyCommon - Reference: Bovedilla 7-7 (Paño 4); sets with these values: 2
Pset_ProvisionForVoid - Shape: Undefined; Width: 0.58 m; Height: 0.25 m; Depth: 0.25 m

# IfcBuildingElementProxy: Bovedilla 7-8 (Paño 2)
In: PB
Type - Description: Bovedilla de hormigón; PredefinedType: USERDEFINED
Pset_BuildingElementProxyCommon - Reference: Bovedilla 7-8 (Paño 2); sets with these values: 2
Pset_ProvisionForVoid - Shape: Undefined; Width: 0.58 m; Height: 0.25 m; Depth: 0.25 m

# IfcBuildingElementProxy: Bovedilla 7-8 (Paño 4)
In: F1
Type - Description: Bovedilla de hormigón; PredefinedType: USERDEFINED
Pset_BuildingElementProxyCommon - Reference: Bovedilla 7-8 (Paño 4); sets with these values: 2
Pset_ProvisionForVoid - Shape: Undefined; Width: 0.58 m; Height: 0.25 m; Depth: 0.25 m

# IfcBuildingElementProxy: Bovedilla 7-9 (Paño 2)
In: PB
Type - Description: Bovedilla de hormigón; PredefinedType: USERDEFINED
Pset_BuildingElementProxyCommon - Reference: Bovedilla 7-9 (Paño 2); sets with these values: 2
Pset_ProvisionForVoid - Shape: Undefined; Width: 0.58 m; Height: 0.25 m; Depth: 0.25 m

# IfcBuildingElementProxy: Bovedilla 7-9 (Paño 4)
In: F1
Type - Description: Bovedilla de hormigón; PredefinedType: USERDEFINED
Pset_BuildingElementProxyCommon - Reference: Bovedilla 7-9 (Paño 4); sets with these values: 2
Pset_ProvisionForVoid - Shape: Undefined; Width: 0.58 m; Height: 0.25 m; Depth: 0.25 m

# IfcBuildingElementProxy: Bovedilla 8-1 (Paño 2)
In: PB
Type - Description: Bovedilla de hormigón; PredefinedType: USERDEFINED
Pset_BuildingElementProxyCommon - Reference: Bovedilla 8-1 (Paño 2); sets with these values: 2
Pset_ProvisionForVoid - Shape: Undefined; Width: 0.58 m; Height: 0.25 m; Depth: 0.25 m

# IfcBuildingElementProxy: Bovedilla 8-1 (Paño 4)
In: F1
Type - Description: Bovedilla de hormigón; PredefinedType: USERDEFINED
Pset_BuildingElementProxyCommon - Reference: Bovedilla 8-1 (Paño 4); sets with these values: 2
Pset_ProvisionForVoid - Shape: Undefined; Width: 0.58 m; Height: 0.25 m; Depth: 0.25 m

# IfcBuildingElementProxy: Bovedilla 8-10 (Paño 2)
In: PB
Type - Description: Bovedilla de hormigón; PredefinedType: USERDEFINED
Pset_BuildingElementProxyCommon - Reference: Bovedilla 8-10 (Paño 2); sets with these values: 2
Pset_ProvisionForVoid - Shape: Undefined; Width: 0.58 m; Height: 0.25 m; Depth: 0.25 m

# IfcBuildingElementProxy: Bovedilla 8-10 (Paño 4)
In: F1
Type - Description: Bovedilla de hormigón; PredefinedType: USERDEFINED
Pset_BuildingElementProxyCommon - Reference: Bovedilla 8-10 (Paño 4); sets with these values: 2
Pset_ProvisionForVoid - Shape: Undefined; Width: 0.58 m; Height: 0.25 m; Depth: 0.25 m

# IfcBuildingElementProxy: Bovedilla 8-11 (Paño 2)
In: PB
Type - Description: Bovedilla de hormigón; PredefinedType: USERDEFINED
Pset_BuildingElementProxyCommon - Reference: Bovedilla 8-11 (Paño 2); sets with these values: 2
Pset_ProvisionForVoid - Shape: Undefined; Width: 0.58 m; Height: 0.25 m; Depth: 0.25 m

# IfcBuildingElementProxy: Bovedilla 8-11 (Paño 4)
In: F1
Type - Description: Bovedilla de hormigón; PredefinedType: USERDEFINED
Pset_BuildingElementProxyCommon - Reference: Bovedilla 8-11 (Paño 4); sets with these values: 2
Pset_ProvisionForVoid - Shape: Undefined; Width: 0.58 m; Height: 0.25 m; Depth: 0.25 m

# IfcBuildingElementProxy: Bovedilla 8-12 (Paño 2)
In: PB
Type - Description: Bovedilla de hormigón; PredefinedType: USERDEFINED
Pset_BuildingElementProxyCommon - Reference: Bovedilla 8-12 (Paño 2); sets with these values: 2
Pset_ProvisionForVoid - Shape: Undefined; Width: 0.58 m; Height: 0.25 m; Depth: 0.25 m

# IfcBuildingElementProxy: Bovedilla 8-12 (Paño 4)
In: F1
Type - Description: Bovedilla de hormigón; PredefinedType: USERDEFINED
Pset_BuildingElementProxyCommon - Reference: Bovedilla 8-12 (Paño 4); sets with these values: 2
Pset_ProvisionForVoid - Shape: Undefined; Width: 0.58 m; Height: 0.25 m; Depth: 0.25 m

# IfcBuildingElementProxy: Bovedilla 8-13 (Paño 2)
In: PB
Type - Description: Bovedilla de hormigón; PredefinedType: USERDEFINED
Pset_BuildingElementProxyCommon - Reference: Bovedilla 8-13 (Paño 2); sets with these values: 2
Pset_ProvisionForVoid - Shape: Undefined; Width: 0.58 m; Height: 0.25 m; Depth: 0.25 m

# IfcBuildingElementProxy: Bovedilla 8-13 (Paño 4)
In: F1
Type - Description: Bovedilla de hormigón; PredefinedType: USERDEFINED
Pset_BuildingElementProxyCommon - Reference: Bovedilla 8-13 (Paño 4); sets with these values: 2
Pset_ProvisionForVoid - Shape: Undefined; Width: 0.58 m; Height: 0.25 m; Depth: 0.25 m

# IfcBuildingElementProxy: Bovedilla 8-14 (Paño 2)
In: PB
Type - Description: Bovedilla de hormigón; PredefinedType: USERDEFINED
Pset_BuildingElementProxyCommon - Reference: Bovedilla 8-14 (Paño 2); sets with these values: 2
Pset_ProvisionForVoid - Shape: Undefined; Width: 0.58 m; Height: 0.25 m; Depth: 0.25 m

# IfcBuildingElementProxy: Bovedilla 8-14 (Paño 4)
In: F1
Type - Description: Bovedilla de hormigón; PredefinedType: USERDEFINED
Pset_BuildingElementProxyCommon - Reference: Bovedilla 8-14 (Paño 4); sets with these values: 2
Pset_ProvisionForVoid - Shape: Undefined; Width: 0.58 m; Height: 0.25 m; Depth: 0.25 m

# IfcBuildingElementProxy: Bovedilla 8-15 (Paño 4)
In: F1
Type - Description: Bovedilla de hormigón; PredefinedType: USERDEFINED
Pset_BuildingElementProxyCommon - Reference: Bovedilla 8-15 (Paño 4); sets with these values: 2
Pset_ProvisionForVoid - Shape: Undefined; Width: 0.58 m; Height: 0.25 m; Depth: 0.25 m

# IfcBuildingElementProxy: Bovedilla 8-16 (Paño 4)
In: F1
Type - Description: Bovedilla de hormigón; PredefinedType: USERDEFINED
Pset_BuildingElementProxyCommon - Reference: Bovedilla 8-16 (Paño 4); sets with these values: 2
Pset_ProvisionForVoid - Shape: Undefined; Width: 0.58 m; Height: 0.25 m; Depth: 0.25 m

# IfcBuildingElementProxy: Bovedilla 8-2 (Paño 2)
In: PB
Type - Description: Bovedilla de hormigón; PredefinedType: USERDEFINED
Pset_BuildingElementProxyCommon - Reference: Bovedilla 8-2 (Paño 2); sets with these values: 2
Pset_ProvisionForVoid - Shape: Undefined; Width: 0.58 m; Height: 0.25 m; Depth: 0.25 m

# IfcBuildingElementProxy: Bovedilla 8-2 (Paño 4)
In: F1
Type - Description: Bovedilla de hormigón; PredefinedType: USERDEFINED
Pset_BuildingElementProxyCommon - Reference: Bovedilla 8-2 (Paño 4); sets with these values: 2
Pset_ProvisionForVoid - Shape: Undefined; Width: 0.58 m; Height: 0.25 m; Depth: 0.25 m

# IfcBuildingElementProxy: Bovedilla 8-3 (Paño 2)
In: PB
Type - Description: Bovedilla de hormigón; PredefinedType: USERDEFINED
Pset_BuildingElementProxyCommon - Reference: Bovedilla 8-3 (Paño 2); sets with these values: 2
Pset_ProvisionForVoid - Shape: Undefined; Width: 0.58 m; Height: 0.25 m; Depth: 0.25 m

# IfcBuildingElementProxy: Bovedilla 8-3 (Paño 4)
In: F1
Type - Description: Bovedilla de hormigón; PredefinedType: USERDEFINED
Pset_BuildingElementProxyCommon - Reference: Bovedilla 8-3 (Paño 4); sets with these values: 2
Pset_ProvisionForVoid - Shape: Undefined; Width: 0.58 m; Height: 0.25 m; Depth: 0.25 m

# IfcBuildingElementProxy: Bovedilla 8-4 (Paño 2)
In: PB
Type - Description: Bovedilla de hormigón; PredefinedType: USERDEFINED
Pset_BuildingElementProxyCommon - Reference: Bovedilla 8-4 (Paño 2); sets with these values: 2
Pset_ProvisionForVoid - Shape: Undefined; Width: 0.58 m; Height: 0.25 m; Depth: 0.25 m

# IfcBuildingElementProxy: Bovedilla 8-4 (Paño 4)
In: F1
Type - Description: Bovedilla de hormigón; PredefinedType: USERDEFINED
Pset_BuildingElementProxyCommon - Reference: Bovedilla 8-4 (Paño 4); sets with these values: 2
Pset_ProvisionForVoid - Shape: Undefined; Width: 0.58 m; Height: 0.25 m; Depth: 0.25 m

# IfcBuildingElementProxy: Bovedilla 8-5 (Paño 2)
In: PB
Type - Description: Bovedilla de hormigón; PredefinedType: USERDEFINED
Pset_BuildingElementProxyCommon - Reference: Bovedilla 8-5 (Paño 2); sets with these values: 2
Pset_ProvisionForVoid - Shape: Undefined; Width: 0.58 m; Height: 0.25 m; Depth: 0.25 m

# IfcBuildingElementProxy: Bovedilla 8-5 (Paño 4)
In: F1
Type - Description: Bovedilla de hormigón; PredefinedType: USERDEFINED
Pset_BuildingElementProxyCommon - Reference: Bovedilla 8-5 (Paño 4); sets with these values: 2
Pset_ProvisionForVoid - Shape: Undefined; Width: 0.58 m; Height: 0.25 m; Depth: 0.25 m

# IfcBuildingElementProxy: Bovedilla 8-6 (Paño 2)
In: PB
Type - Description: Bovedilla de hormigón; PredefinedType: USERDEFINED
Pset_BuildingElementProxyCommon - Reference: Bovedilla 8-6 (Paño 2); sets with these values: 2
Pset_ProvisionForVoid - Shape: Undefined; Width: 0.58 m; Height: 0.25 m; Depth: 0.25 m

# IfcBuildingElementProxy: Bovedilla 8-6 (Paño 4)
In: F1
Type - Description: Bovedilla de hormigón; PredefinedType: USERDEFINED
Pset_BuildingElementProxyCommon - Reference: Bovedilla 8-6 (Paño 4); sets with these values: 2
Pset_ProvisionForVoid - Shape: Undefined; Width: 0.58 m; Height: 0.25 m; Depth: 0.25 m

# IfcBuildingElementProxy: Bovedilla 8-7 (Paño 2)
In: PB
Type - Description: Bovedilla de hormigón; PredefinedType: USERDEFINED
Pset_BuildingElementProxyCommon - Reference: Bovedilla 8-7 (Paño 2); sets with these values: 2
Pset_ProvisionForVoid - Shape: Undefined; Width: 0.58 m; Height: 0.25 m; Depth: 0.25 m

# IfcBuildingElementProxy: Bovedilla 8-7 (Paño 4)
In: F1
Type - Description: Bovedilla de hormigón; PredefinedType: USERDEFINED
Pset_BuildingElementProxyCommon - Reference: Bovedilla 8-7 (Paño 4); sets with these values: 2
Pset_ProvisionForVoid - Shape: Undefined; Width: 0.58 m; Height: 0.25 m; Depth: 0.25 m

# IfcBuildingElementProxy: Bovedilla 8-8 (Paño 2)
In: PB
Type - Description: Bovedilla de hormigón; PredefinedType: USERDEFINED
Pset_BuildingElementProxyCommon - Reference: Bovedilla 8-8 (Paño 2); sets with these values: 2
Pset_ProvisionForVoid - Shape: Undefined; Width: 0.58 m; Height: 0.25 m; Depth: 0.25 m

# IfcBuildingElementProxy: Bovedilla 8-8 (Paño 4)
In: F1
Type - Description: Bovedilla de hormigón; PredefinedType: USERDEFINED
Pset_BuildingElementProxyCommon - Reference: Bovedilla 8-8 (Paño 4); sets with these values: 2
Pset_ProvisionForVoid - Shape: Undefined; Width: 0.58 m; Height: 0.25 m; Depth: 0.25 m

# IfcBuildingElementProxy: Bovedilla 8-9 (Paño 2)
In: PB
Type - Description: Bovedilla de hormigón; PredefinedType: USERDEFINED
Pset_BuildingElementProxyCommon - Reference: Bovedilla 8-9 (Paño 2); sets with these values: 2
Pset_ProvisionForVoid - Shape: Undefined; Width: 0.58 m; Height: 0.25 m; Depth: 0.25 m

# IfcBuildingElementProxy: Bovedilla 8-9 (Paño 4)
In: F1
Type - Description: Bovedilla de hormigón; PredefinedType: USERDEFINED
Pset_BuildingElementProxyCommon - Reference: Bovedilla 8-9 (Paño 4); sets with these values: 2
Pset_ProvisionForVoid - Shape: Undefined; Width: 0.58 m; Height: 0.25 m; Depth: 0.25 m

# IfcBuildingElementProxy: Bovedilla 9-1 (Paño 2)
In: PB
Type - Description: Bovedilla de hormigón; PredefinedType: USERDEFINED
Pset_BuildingElementProxyCommon - Reference: Bovedilla 9-1 (Paño 2); sets with these values: 2
Pset_ProvisionForVoid - Shape: Undefined; Width: 0.58 m; Height: 0.25 m; Depth: 0.25 m

# IfcBuildingElementProxy: Bovedilla 9-10 (Paño 2)
In: PB
Type - Description: Bovedilla de hormigón; PredefinedType: USERDEFINED
Pset_BuildingElementProxyCommon - Reference: Bovedilla 9-10 (Paño 2); sets with these values: 2
Pset_ProvisionForVoid - Shape: Undefined; Width: 0.58 m; Height: 0.25 m; Depth: 0.25 m

# IfcBuildingElementProxy: Bovedilla 9-11 (Paño 2)
In: PB
Type - Description: Bovedilla de hormigón; PredefinedType: USERDEFINED
Pset_BuildingElementProxyCommon - Reference: Bovedilla 9-11 (Paño 2); sets with these values: 2
Pset_ProvisionForVoid - Shape: Undefined; Width: 0.58 m; Height: 0.25 m; Depth: 0.25 m

# IfcBuildingElementProxy: Bovedilla 9-12 (Paño 2)
In: PB
Type - Description: Bovedilla de hormigón; PredefinedType: USERDEFINED
Pset_BuildingElementProxyCommon - Reference: Bovedilla 9-12 (Paño 2); sets with these values: 2
Pset_ProvisionForVoid - Shape: Undefined; Width: 0.58 m; Height: 0.25 m; Depth: 0.25 m

# IfcBuildingElementProxy: Bovedilla 9-13 (Paño 2)
In: PB
Type - Description: Bovedilla de hormigón; PredefinedType: USERDEFINED
Pset_BuildingElementProxyCommon - Reference: Bovedilla 9-13 (Paño 2); sets with these values: 2
Pset_ProvisionForVoid - Shape: Undefined; Width: 0.58 m; Height: 0.25 m; Depth: 0.25 m

# IfcBuildingElementProxy: Bovedilla 9-14 (Paño 2)
In: PB
Type - Description: Bovedilla de hormigón; PredefinedType: USERDEFINED
Pset_BuildingElementProxyCommon - Reference: Bovedilla 9-14 (Paño 2); sets with these values: 2
Pset_ProvisionForVoid - Shape: Undefined; Width: 0.58 m; Height: 0.25 m; Depth: 0.25 m

# IfcBuildingElementProxy: Bovedilla 9-2 (Paño 2)
In: PB
Type - Description: Bovedilla de hormigón; PredefinedType: USERDEFINED
Pset_BuildingElementProxyCommon - Reference: Bovedilla 9-2 (Paño 2); sets with these values: 2
Pset_ProvisionForVoid - Shape: Undefined; Width: 0.58 m; Height: 0.25 m; Depth: 0.25 m

# IfcBuildingElementProxy: Bovedilla 9-3 (Paño 2)
In: PB
Type - Description: Bovedilla de hormigón; PredefinedType: USERDEFINED
Pset_BuildingElementProxyCommon - Reference: Bovedilla 9-3 (Paño 2); sets with these values: 2
Pset_ProvisionForVoid - Shape: Undefined; Width: 0.58 m; Height: 0.25 m; Depth: 0.25 m

# IfcBuildingElementProxy: Bovedilla 9-4 (Paño 2)
In: PB
Type - Description: Bovedilla de hormigón; PredefinedType: USERDEFINED
Pset_BuildingElementProxyCommon - Reference: Bovedilla 9-4 (Paño 2); sets with these values: 2
Pset_ProvisionForVoid - Shape: Undefined; Width: 0.58 m; Height: 0.25 m; Depth: 0.25 m

# IfcBuildingElementProxy: Bovedilla 9-5 (Paño 2)
In: PB
Type - Description: Bovedilla de hormigón; PredefinedType: USERDEFINED
Pset_BuildingElementProxyCommon - Reference: Bovedilla 9-5 (Paño 2); sets with these values: 2
Pset_ProvisionForVoid - Shape: Undefined; Width: 0.58 m; Height: 0.25 m; Depth: 0.25 m

# IfcBuildingElementProxy: Bovedilla 9-6 (Paño 2)
In: PB
Type - Description: Bovedilla de hormigón; PredefinedType: USERDEFINED
Pset_BuildingElementProxyCommon - Reference: Bovedilla 9-6 (Paño 2); sets with these values: 2
Pset_ProvisionForVoid - Shape: Undefined; Width: 0.58 m; Height: 0.25 m; Depth: 0.25 m

# IfcBuildingElementProxy: Bovedilla 9-7 (Paño 2)
In: PB
Type - Description: Bovedilla de hormigón; PredefinedType: USERDEFINED
Pset_BuildingElementProxyCommon - Reference: Bovedilla 9-7 (Paño 2); sets with these values: 2
Pset_ProvisionForVoid - Shape: Undefined; Width: 0.58 m; Height: 0.25 m; Depth: 0.25 m

# IfcBuildingElementProxy: Bovedilla 9-8 (Paño 2)
In: PB
Type - Description: Bovedilla de hormigón; PredefinedType: USERDEFINED
Pset_BuildingElementProxyCommon - Reference: Bovedilla 9-8 (Paño 2); sets with these values: 2
Pset_ProvisionForVoid - Shape: Undefined; Width: 0.58 m; Height: 0.25 m; Depth: 0.25 m

# IfcBuildingElementProxy: Bovedilla 9-9 (Paño 2)
In: PB
Type - Description: Bovedilla de hormigón; PredefinedType: USERDEFINED
Pset_BuildingElementProxyCommon - Reference: Bovedilla 9-9 (Paño 2); sets with these values: 2
Pset_ProvisionForVoid - Shape: Undefined; Width: 0.58 m; Height: 0.25 m; Depth: 0.25 m

# IfcColumn: Forma directa:DirectShapeType 3937 (18)
In: PB
Type - Pset_ColumnCommon - IsExternal: no; LoadBearing: yes
Description: Rectangular. Hormigón armado
Pset_QuantityTakeOff - Reference: DirectShapeType 3937; sets with these values: 2
Name | Reference
P1 (30x30) | P1
P2 (30x30) | P2
P5 (30x30) | P5
P6 (30x30) | P6
P9 (30x30) | P9
P10 (30x30) | P10
P12 (30x30) | P12
P13 (30x30) | P13
P17 (30x30) | P17
P18 (30x30) | P18
P15 (30x30) | P15
P14 (30x30) | P14
P16 (30x30) | P16
P11 (30x30) | P11
P8 (30x30) | P8
P7 (30x30) | P7
P3 (30x30) | P3
P4 (30x30) | P4

# IfcFooting: P1 (100 x 100 x 40)
In: PB
Type - Description: Zapata de hormigón armado
PredefinedType: PAD_FOOTING
Pset_QuantityTakeOff - Reference: P1 (100 x 100 x 40); sets with these values: 3

# IfcFooting: P10 (100 x 100 x 40)
In: PB
Type - Description: Zapata de hormigón armado
PredefinedType: PAD_FOOTING
Pset_QuantityTakeOff - Reference: P10 (100 x 100 x 40); sets with these values: 3

# IfcFooting: P12 (100 x 100 x 45)
In: PB
Type - Description: Zapata de hormigón armado
PredefinedType: PAD_FOOTING
Pset_QuantityTakeOff - Reference: P12 (100 x 100 x 45); sets with these values: 3

# IfcFooting: P13 (100 x 100 x 40)
In: PB
Type - Description: Zapata de hormigón armado
PredefinedType: PAD_FOOTING
Pset_QuantityTakeOff - Reference: P13 (100 x 100 x 40); sets with these values: 3

# IfcFooting: P17 (100 x 100 x 40)
In: PB
Type - Description: Zapata de hormigón armado
PredefinedType: PAD_FOOTING
Pset_QuantityTakeOff - Reference: P17 (100 x 100 x 40); sets with these values: 3

# IfcFooting: P18 (100 x 100 x 40)
In: PB
Type - Description: Zapata de hormigón armado
PredefinedType: PAD_FOOTING
Pset_QuantityTakeOff - Reference: P18 (100 x 100 x 40); sets with these values: 3

# IfcFooting: P2 (100 x 100 x 40)
In: PB
Type - Description: Zapata de hormigón armado
PredefinedType: PAD_FOOTING
Pset_QuantityTakeOff - Reference: P2 (100 x 100 x 40); sets with these values: 3

# IfcFooting: P5 (100 x 100 x 40)
In: PB
Type - Description: Zapata de hormigón armado
PredefinedType: PAD_FOOTING
Pset_QuantityTakeOff - Reference: P5 (100 x 100 x 40); sets with these values: 3

# IfcFooting: P6 (100 x 100 x 40)
In: PB
Type - Description: Zapata de hormigón armado
PredefinedType: PAD_FOOTING
Pset_QuantityTakeOff - Reference: P6 (100 x 100 x 40); sets with these values: 3

# IfcFooting: P9 (100 x 100 x 45)
In: PB
Type - Description: Zapata de hormigón armado
PredefinedType: PAD_FOOTING
Pset_QuantityTakeOff - Reference: P9 (100 x 100 x 45); sets with these values: 3

# IfcFooting: Viga 10 (40x40)
In: PB
Type - Description: Rectangular. Hormigón armado
PredefinedType: FOOTING_BEAM
Pset_QuantityTakeOff - Reference: Viga 10 (40x40); sets with these values: 3

# IfcFooting: Viga 11 (40x40)
In: PB
Type - Description: Rectangular. Hormigón armado
PredefinedType: FOOTING_BEAM
Pset_QuantityTakeOff - Reference: Viga 11 (40x40); sets with these values: 3

# IfcFooting: Viga 12 (40x40)
In: PB
Type - Description: Rectangular. Hormigón armado
PredefinedType: FOOTING_BEAM
Pset_QuantityTakeOff - Reference: Viga 12 (40x40); sets with these values: 3

# IfcFooting: Viga 13 (40x40)
In: PB
Type - Description: Rectangular. Hormigón armado
PredefinedType: FOOTING_BEAM
Pset_QuantityTakeOff - Reference: Viga 13 (40x40); sets with these values: 3

# IfcFooting: Viga 15 (40x40)
In: PB
Type - Description: Rectangular. Hormigón armado
PredefinedType: FOOTING_BEAM
Pset_QuantityTakeOff - Reference: Viga 15 (40x40); sets with these values: 3

# IfcFooting: Viga 16 (40x40)
In: PB
Type - Description: Rectangular. Hormigón armado
PredefinedType: FOOTING_BEAM
Pset_QuantityTakeOff - Reference: Viga 16 (40x40); sets with these values: 3

# IfcFooting: Viga 17 (40x40)
In: PB
Type - Description: Rectangular. Hormigón armado
PredefinedType: FOOTING_BEAM
Pset_QuantityTakeOff - Reference: Viga 17 (40x40); sets with these values: 3

# IfcFooting: Viga 18 (40x40)
In: PB
Type - Description: Rectangular. Hormigón armado
PredefinedType: FOOTING_BEAM
Pset_QuantityTakeOff - Reference: Viga 18 (40x40); sets with these values: 3

# IfcMember: Celosía (Vigueta 1 - Paño 10)
In: PB
Type - Description: No definido
Pset_MemberCommon - IsExternal: no; LoadBearing: yes; Reference: Celosía (Vigueta 1 - Paño 10); Slope: 7.71638 deg
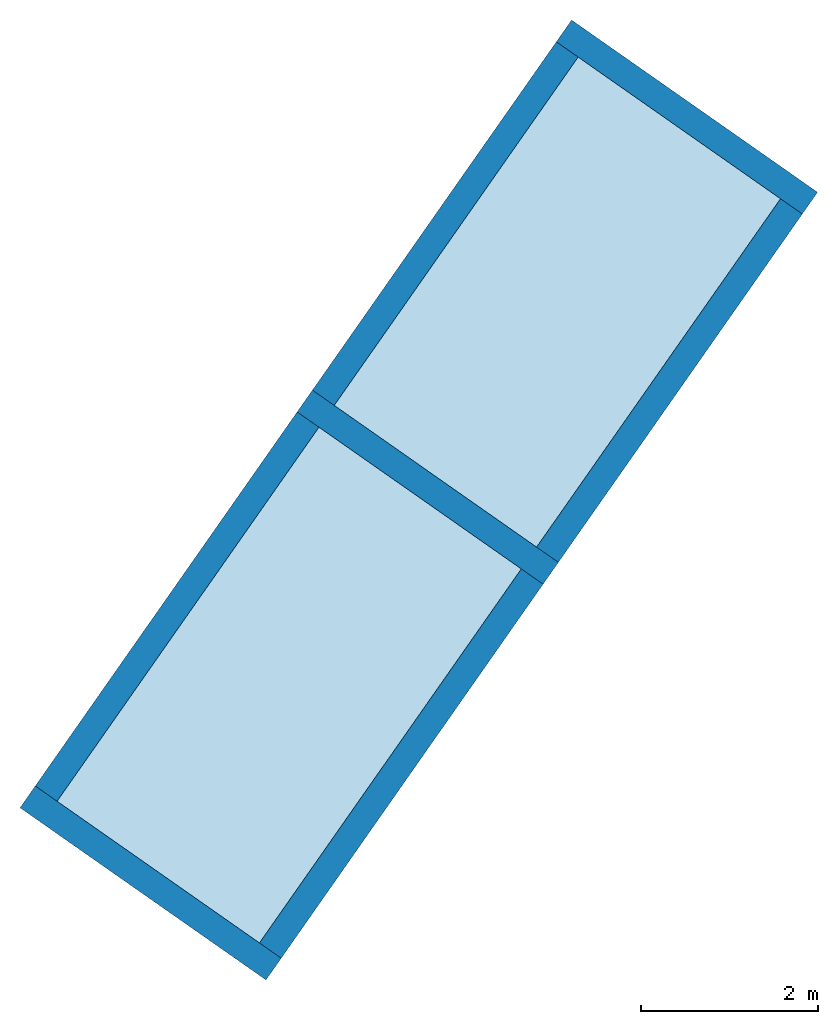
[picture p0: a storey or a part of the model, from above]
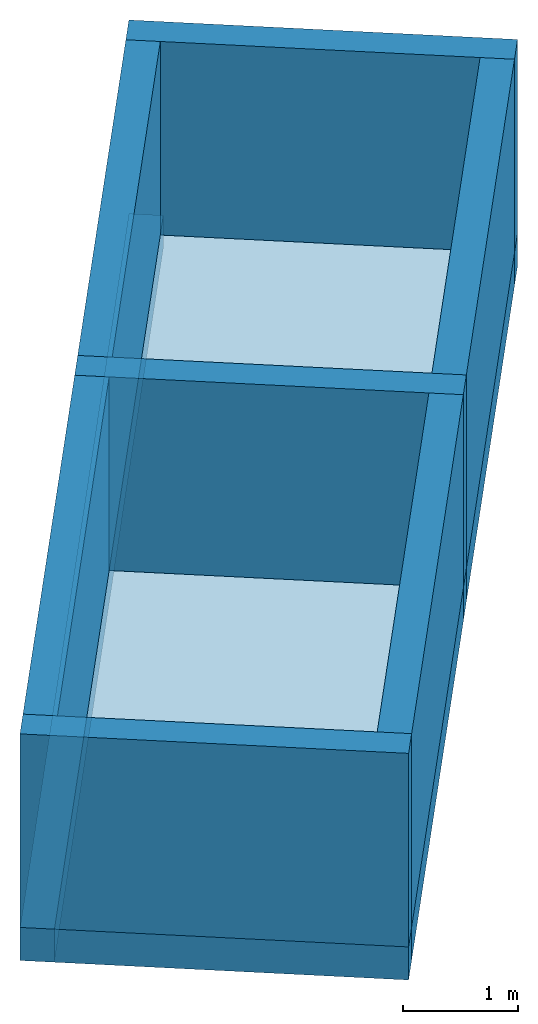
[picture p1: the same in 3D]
Properties of the parts of a building model (IFC2X3), part 5 of 5

# IfcMember: Celosía (Vigueta 1 - Paño 10)
Pset_QuantityTakeOff - Reference: Celosía (Vigueta 1 - Paño 10)

# IfcMember: Celosía (Vigueta 1 - Paño 11)
In: PB
Type - Description: No definido
Pset_MemberCommon - IsExternal: no; LoadBearing: yes; Reference: Celosía (Vigueta 1 - Paño 11); Slope: 7.71638 deg
Pset_QuantityTakeOff - Reference: Celosía (Vigueta 1 - Paño 11)

# IfcMember: Celosía (Vigueta 1 - Paño 13)
In: PB
Type - Description: No definido
Pset_MemberCommon - IsExternal: no; LoadBearing: yes; Reference: Celosía (Vigueta 1 - Paño 13); Slope: 7.71638 deg
Pset_QuantityTakeOff - Reference: Celosía (Vigueta 1 - Paño 13)

# IfcMember: Celosía (Vigueta 1 - Paño 15)
In: PB
Type - Description: No definido
Pset_MemberCommon - IsExternal: no; LoadBearing: yes; Reference: Celosía (Vigueta 1 - Paño 15); Slope: 7.71638 deg
Pset_QuantityTakeOff - Reference: Celosía (Vigueta 1 - Paño 15)

# IfcMember: Celosía (Vigueta 1 - Paño 2)
In: PB
Type - Description: No definido
Pset_MemberCommon - IsExternal: no; LoadBearing: yes; Reference: Celosía (Vigueta 1 - Paño 2); Slope: 7.71638 deg
Pset_QuantityTakeOff - Reference: Celosía (Vigueta 1 - Paño 2)

# IfcMember: Celosía (Vigueta 1 - Paño 3)
In: F1
Type - Description: No definido
Pset_MemberCommon - IsExternal: no; LoadBearing: yes; Reference: Celosía (Vigueta 1 - Paño 3); Slope: 7.71638 deg
Pset_QuantityTakeOff - Reference: Celosía (Vigueta 1 - Paño 3)

# IfcMember: Celosía (Vigueta 1 - Paño 4)
In: F1
Type - Description: No definido
Pset_MemberCommon - IsExternal: no; LoadBearing: yes; Reference: Celosía (Vigueta 1 - Paño 4); Slope: 7.71638 deg
Pset_QuantityTakeOff - Reference: Celosía (Vigueta 1 - Paño 4)

# IfcMember: Celosía (Vigueta 1 - Paño 6)
In: PB
Type - Description: No definido
Pset_MemberCommon - IsExternal: no; LoadBearing: yes; Reference: Celosía (Vigueta 1 - Paño 6); Slope: 7.71638 deg
Pset_QuantityTakeOff - Reference: Celosía (Vigueta 1 - Paño 6)

# IfcMember: Celosía (Vigueta 1 - Paño 8)
In: PB
Type - Description: No definido
Pset_MemberCommon - IsExternal: no; LoadBearing: yes; Reference: Celosía (Vigueta 1 - Paño 8); Slope: 7.71638 deg
Pset_QuantityTakeOff - Reference: Celosía (Vigueta 1 - Paño 8)

# IfcMember: Celosía (Vigueta 10 - Paño 2)
In: PB
Type - Description: No definido
Pset_MemberCommon - IsExternal: no; LoadBearing: yes; Reference: Celosía (Vigueta 10 - Paño 2); Slope: 7.71638 deg
Pset_QuantityTakeOff - Reference: Celosía (Vigueta 10 - Paño 2)

# IfcMember: Celosía (Vigueta 11 - Paño 2)
In: PB
Type - Description: No definido
Pset_MemberCommon - IsExternal: no; LoadBearing: yes; Reference: Celosía (Vigueta 11 - Paño 2); Slope: 7.71638 deg
Pset_QuantityTakeOff - Reference: Celosía (Vigueta 11 - Paño 2)

# IfcMember: Celosía (Vigueta 12 - Paño 2)
In: PB
Type - Description: No definido
Pset_MemberCommon - IsExternal: no; LoadBearing: yes; Reference: Celosía (Vigueta 12 - Paño 2); Slope: 7.71638 deg
Pset_QuantityTakeOff - Reference: Celosía (Vigueta 12 - Paño 2)

# IfcMember: Celosía (Vigueta 13 - Paño 2)
In: PB
Type - Description: No definido
Pset_MemberCommon - IsExternal: no; LoadBearing: yes; Reference: Celosía (Vigueta 13 - Paño 2); Slope: 7.71638 deg
Pset_QuantityTakeOff - Reference: Celosía (Vigueta 13 - Paño 2)

# IfcMember: Celosía (Vigueta 14 - Paño 2)
In: PB
Type - Description: No definido
Pset_MemberCommon - IsExternal: no; LoadBearing: yes; Reference: Celosía (Vigueta 14 - Paño 2); Slope: 7.71638 deg
Pset_QuantityTakeOff - Reference: Celosía (Vigueta 14 - Paño 2)

# IfcMember: Celosía (Vigueta 2 - Paño 10)
In: PB
Type - Description: No definido
Pset_MemberCommon - IsExternal: no; LoadBearing: yes; Reference: Celosía (Vigueta 2 - Paño 10); Slope: 7.71638 deg
Pset_QuantityTakeOff - Reference: Celosía (Vigueta 2 - Paño 10)

# IfcMember: Celosía (Vigueta 2 - Paño 11)
In: PB
Type - Description: No definido
Pset_MemberCommon - IsExternal: no; LoadBearing: yes; Reference: Celosía (Vigueta 2 - Paño 11); Slope: 7.71638 deg
Pset_QuantityTakeOff - Reference: Celosía (Vigueta 2 - Paño 11)

# IfcMember: Celosía (Vigueta 2 - Paño 13)
In: PB
Type - Description: No definido
Pset_MemberCommon - IsExternal: no; LoadBearing: yes; Reference: Celosía (Vigueta 2 - Paño 13); Slope: 7.71638 deg
Pset_QuantityTakeOff - Reference: Celosía (Vigueta 2 - Paño 13)

# IfcMember: Celosía (Vigueta 2 - Paño 15)
In: PB
Type - Description: No definido
Pset_MemberCommon - IsExternal: no; LoadBearing: yes; Reference: Celosía (Vigueta 2 - Paño 15); Slope: 7.71638 deg
Pset_QuantityTakeOff - Reference: Celosía (Vigueta 2 - Paño 15)

# IfcMember: Celosía (Vigueta 2 - Paño 2)
In: PB
Type - Description: No definido
Pset_MemberCommon - IsExternal: no; LoadBearing: yes; Reference: Celosía (Vigueta 2 - Paño 2); Slope: 7.71638 deg
Pset_QuantityTakeOff - Reference: Celosía (Vigueta 2 - Paño 2)

# IfcMember: Celosía (Vigueta 2 - Paño 3)
In: F1
Type - Description: No definido
Pset_MemberCommon - IsExternal: no; LoadBearing: yes; Reference: Celosía (Vigueta 2 - Paño 3); Slope: 7.71638 deg
Pset_QuantityTakeOff - Reference: Celosía (Vigueta 2 - Paño 3)

# IfcMember: Celosía (Vigueta 2 - Paño 4)
In: F1
Type - Description: No definido
Pset_MemberCommon - IsExternal: no; LoadBearing: yes; Reference: Celosía (Vigueta 2 - Paño 4); Slope: 7.71638 deg
Pset_QuantityTakeOff - Reference: Celosía (Vigueta 2 - Paño 4)

# IfcMember: Celosía (Vigueta 2 - Paño 6)
In: PB
Type - Description: No definido
Pset_MemberCommon - IsExternal: no; LoadBearing: yes; Reference: Celosía (Vigueta 2 - Paño 6); Slope: 7.71638 deg
Pset_QuantityTakeOff - Reference: Celosía (Vigueta 2 - Paño 6)

# IfcMember: Celosía (Vigueta 2 - Paño 8)
In: PB
Type - Description: No definido
Pset_MemberCommon - IsExternal: no; LoadBearing: yes; Reference: Celosía (Vigueta 2 - Paño 8); Slope: 7.71638 deg
Pset_QuantityTakeOff - Reference: Celosía (Vigueta 2 - Paño 8)

# IfcMember: Celosía (Vigueta 3 - Paño 11)
In: PB
Type - Description: No definido
Pset_MemberCommon - IsExternal: no; LoadBearing: yes; Reference: Celosía (Vigueta 3 - Paño 11); Slope: 7.71638 deg
Pset_QuantityTakeOff - Reference: Celosía (Vigueta 3 - Paño 11)

# IfcMember: Celosía (Vigueta 3 - Paño 13)
In: PB
Type - Description: No definido
Pset_MemberCommon - IsExternal: no; LoadBearing: yes; Reference: Celosía (Vigueta 3 - Paño 13); Slope: 7.71638 deg
Pset_QuantityTakeOff - Reference: Celosía (Vigueta 3 - Paño 13)

# IfcMember: Celosía (Vigueta 3 - Paño 2)
In: PB
Type - Description: No definido
Pset_MemberCommon - IsExternal: no; LoadBearing: yes; Reference: Celosía (Vigueta 3 - Paño 2); Slope: 7.71638 deg
Pset_QuantityTakeOff - Reference: Celosía (Vigueta 3 - Paño 2)

# IfcMember: Celosía (Vigueta 3 - Paño 3)
In: F1
Type - Description: No definido
Pset_MemberCommon - IsExternal: no; LoadBearing: yes; Reference: Celosía (Vigueta 3 - Paño 3); Slope: 7.71638 deg
Pset_QuantityTakeOff - Reference: Celosía (Vigueta 3 - Paño 3)

# IfcMember: Celosía (Vigueta 3 - Paño 4)
In: F1
Type - Description: No definido
Pset_MemberCommon - IsExternal: no; LoadBearing: yes; Reference: Celosía (Vigueta 3 - Paño 4); Slope: 7.71638 deg
Pset_QuantityTakeOff - Reference: Celosía (Vigueta 3 - Paño 4)

# IfcMember: Celosía (Vigueta 3 - Paño 6)
In: PB
Type - Description: No definido
Pset_MemberCommon - IsExternal: no; LoadBearing: yes; Reference: Celosía (Vigueta 3 - Paño 6); Slope: 7.71638 deg
Pset_QuantityTakeOff - Reference: Celosía (Vigueta 3 - Paño 6)

# IfcMember: Celosía (Vigueta 4 - Paño 2)
In: PB
Type - Description: No definido
Pset_MemberCommon - IsExternal: no; LoadBearing: yes; Reference: Celosía (Vigueta 4 - Paño 2); Slope: 7.71638 deg
Pset_QuantityTakeOff - Reference: Celosía (Vigueta 4 - Paño 2)

# IfcMember: Celosía (Vigueta 4 - Paño 3)
In: F1
Type - Description: No definido
Pset_MemberCommon - IsExternal: no; LoadBearing: yes; Reference: Celosía (Vigueta 4 - Paño 3); Slope: 7.71638 deg
Pset_QuantityTakeOff - Reference: Celosía (Vigueta 4 - Paño 3)

# IfcMember: Celosía (Vigueta 4 - Paño 4)
In: F1
Type - Description: No definido
Pset_MemberCommon - IsExternal: no; LoadBearing: yes; Reference: Celosía (Vigueta 4 - Paño 4); Slope: 7.71638 deg
Pset_QuantityTakeOff - Reference: Celosía (Vigueta 4 - Paño 4)

# IfcMember: Celosía (Vigueta 4 - Paño 6)
In: PB
Type - Description: No definido
Pset_MemberCommon - IsExternal: no; LoadBearing: yes; Reference: Celosía (Vigueta 4 - Paño 6); Slope: 7.71638 deg
Pset_QuantityTakeOff - Reference: Celosía (Vigueta 4 - Paño 6)

# IfcMember: Celosía (Vigueta 5 - Paño 2)
In: PB
Type - Description: No definido
Pset_MemberCommon - IsExternal: no; LoadBearing: yes; Reference: Celosía (Vigueta 5 - Paño 2); Slope: 7.71638 deg
Pset_QuantityTakeOff - Reference: Celosía (Vigueta 5 - Paño 2)

# IfcMember: Celosía (Vigueta 5 - Paño 3)
In: F1
Type - Description: No definido
Pset_MemberCommon - IsExternal: no; LoadBearing: yes; Reference: Celosía (Vigueta 5 - Paño 3); Slope: 7.71638 deg
Pset_QuantityTakeOff - Reference: Celosía (Vigueta 5 - Paño 3)

# IfcMember: Celosía (Vigueta 5 - Paño 4)
In: F1
Type - Description: No definido
Pset_MemberCommon - IsExternal: no; LoadBearing: yes; Reference: Celosía (Vigueta 5 - Paño 4); Slope: 7.71638 deg
Pset_QuantityTakeOff - Reference: Celosía (Vigueta 5 - Paño 4)

# IfcMember: Celosía (Vigueta 6 - Paño 2)
In: PB
Type - Description: No definido
Pset_MemberCommon - IsExternal: no; LoadBearing: yes; Reference: Celosía (Vigueta 6 - Paño 2); Slope: 7.71638 deg
Pset_QuantityTakeOff - Reference: Celosía (Vigueta 6 - Paño 2)

# IfcMember: Celosía (Vigueta 6 - Paño 4)
In: F1
Type - Description: No definido
Pset_MemberCommon - IsExternal: no; LoadBearing: yes; Reference: Celosía (Vigueta 6 - Paño 4); Slope: 7.71638 deg
Pset_QuantityTakeOff - Reference: Celosía (Vigueta 6 - Paño 4)

# IfcMember: Celosía (Vigueta 7 - Paño 2)
In: PB
Type - Description: No definido
Pset_MemberCommon - IsExternal: no; LoadBearing: yes; Reference: Celosía (Vigueta 7 - Paño 2); Slope: 7.71638 deg
Pset_QuantityTakeOff - Reference: Celosía (Vigueta 7 - Paño 2)

# IfcMember: Celosía (Vigueta 7 - Paño 4)
In: F1
Type - Description: No definido
Pset_MemberCommon - IsExternal: no; LoadBearing: yes; Reference: Celosía (Vigueta 7 - Paño 4); Slope: 7.71638 deg
Pset_QuantityTakeOff - Reference: Celosía (Vigueta 7 - Paño 4)

# IfcMember: Celosía (Vigueta 8 - Paño 2)
In: PB
Type - Description: No definido
Pset_MemberCommon - IsExternal: no; LoadBearing: yes; Reference: Celosía (Vigueta 8 - Paño 2); Slope: 7.71638 deg
Pset_QuantityTakeOff - Reference: Celosía (Vigueta 8 - Paño 2)

# IfcMember: Celosía (Vigueta 8 - Paño 4)
In: F1
Type - Description: No definido
Pset_MemberCommon - IsExternal: no; LoadBearing: yes; Reference: Celosía (Vigueta 8 - Paño 4); Slope: 7.71638 deg
Pset_QuantityTakeOff - Reference: Celosía (Vigueta 8 - Paño 4)

# IfcMember: Celosía (Vigueta 9 - Paño 2)
In: PB
Type - Description: No definido
Pset_MemberCommon - IsExternal: no; LoadBearing: yes; Reference: Celosía (Vigueta 9 - Paño 2); Slope: 7.71638 deg
Pset_QuantityTakeOff - Reference: Celosía (Vigueta 9 - Paño 2)

# IfcMember: Celosía (Vigueta 9 - Paño 4)
In: F1
Type - Description: No definido
Pset_MemberCommon - IsExternal: no; LoadBearing: yes; Reference: Celosía (Vigueta 9 - Paño 4); Slope: 7.71638 deg
Pset_QuantityTakeOff - Reference: Celosía (Vigueta 9 - Paño 4)

# IfcSlab: Forma directa:DirectShapeType 1092 (14)
Type - PredefinedType: FLOOR
Type - Pset_SlabCommon - IsExternal: no
Pset_QuantityTakeOff - Reference: DirectShapeType 1092; sets with these values: 2
Pset_SlabCommon - PitchAngle: 0 deg; Reference: DirectShapeType 1092
Name | In
Forma directa:DirectShapeType 1092:237742 | Depósito_
Forma directa:DirectShapeType 1092:237829 | Depósito_
Forma directa:DirectShapeType 1092:237956 | PB
Forma directa:DirectShapeType 1092:238195 | F1
Forma directa:DirectShapeType 1092:238276 | F1
Forma directa:DirectShapeType 1092:238433 | PB
Forma directa:DirectShapeType 1092:238546 | PB
Forma directa:DirectShapeType 1092:238563 | PB
Forma directa:DirectShapeType 1092:238581 | PB
Forma directa:DirectShapeType 1092:238598 | PB
Paño 14 (30 cm) | F1 | Description: Forjado de viguetas armadas; Pset_SlabCommon - LoadBearing: yes
Forma directa:DirectShapeType 1092:238640 | PB
Paño 1 (30 cm) | F1 | Description: Losas macizas; Pset_SlabCommon - LoadBearing: yes
Paño 7 (30 cm) | F1 | Description: Losas macizas; Pset_SlabCommon - LoadBearing: yes

# IfcSlab: Forma directa:DirectShapeType 359 (2)
In: Depósito
Type - PredefinedType: BASESLAB
Type - Pset_SlabCommon - IsExternal: no
Description: Losas apoyadas en el terreno
Pset_QuantityTakeOff - Reference: DirectShapeType 359; sets with these values: 2
Pset_SlabCommon - LoadBearing: yes; Reference: DirectShapeType 359; PitchAngle: 0 deg
Name
Paño 1 (35 cm)
Paño 2 (35 cm)

# IfcSlab: Paño 1 (25 cm)
In: PB
Type - Description: Sistema de forjados de viguetas prefabricadas de hormigón; PredefinedType: FLOOR
Pset_QuantityTakeOff - Reference: Paño 1 (25 cm); sets with these values: 2
Pset_SlabCommon - IsExternal: no; LoadBearing: yes; Reference: Paño 1 (25 cm)

# IfcSlab: Paño 10 (30 cm)
In: F1
Type - Description: Forjado de viguetas armadas; PredefinedType: FLOOR
Pset_QuantityTakeOff - Reference: Paño 10 (30 cm); sets with these values: 2
Pset_SlabCommon - IsExternal: no; LoadBearing: yes; Reference: Paño 10 (30 cm)

# IfcSlab: Paño 11 (30 cm)
In: F1
Type - Description: Forjado de viguetas armadas; PredefinedType: FLOOR
Pset_QuantityTakeOff - Reference: Paño 11 (30 cm); sets with these values: 2
Pset_SlabCommon - IsExternal: no; LoadBearing: yes; Reference: Paño 11 (30 cm)

# IfcSlab: Paño 13 (30 cm)
In: F1
Type - Description: Forjado de viguetas armadas; PredefinedType: FLOOR
Pset_QuantityTakeOff - Reference: Paño 13 (30 cm); sets with these values: 2
Pset_SlabCommon - IsExternal: no; LoadBearing: yes; Reference: Paño 13 (30 cm)

# IfcSlab: Paño 15 (30 cm)
In: F1
Type - Description: Forjado de viguetas armadas; PredefinedType: FLOOR
Pset_QuantityTakeOff - Reference: Paño 15 (30 cm); sets with these values: 2
Pset_SlabCommon - IsExternal: no; LoadBearing: yes; Reference: Paño 15 (30 cm)

# IfcSlab: Paño 2 (25 cm)
In: PB
Type - Description: Sistema de forjados de viguetas prefabricadas de hormigón; PredefinedType: FLOOR
Pset_QuantityTakeOff - Reference: Paño 2 (25 cm); sets with these values: 2
Pset_SlabCommon - IsExternal: no; LoadBearing: yes; Reference: Paño 2 (25 cm)

# IfcSlab: Paño 2 (30 cm)
In: F1
Type - Description: Forjado de viguetas armadas; PredefinedType: FLOOR
Pset_QuantityTakeOff - Reference: Paño 2 (30 cm); sets with these values: 2
Pset_SlabCommon - IsExternal: no; LoadBearing: yes; Reference: Paño 2 (30 cm)

# IfcSlab: Paño 3 (30 cm)
In: F1
Type - Description: Forjado de viguetas armadas; PredefinedType: FLOOR
Pset_QuantityTakeOff - Reference: Paño 3 (30 cm); sets with these values: 2
Pset_SlabCommon - IsExternal: no; LoadBearing: yes; Reference: Paño 3 (30 cm)

# IfcSlab: Paño 4 (30 cm)
In: F1
Type - Description: Forjado de viguetas armadas; PredefinedType: FLOOR
Pset_QuantityTakeOff - Reference: Paño 4 (30 cm); sets with these values: 2
Pset_SlabCommon - IsExternal: no; LoadBearing: yes; Reference: Paño 4 (30 cm)

# IfcSlab: Paño 6 (30 cm)
In: F1
Type - Description: Forjado de viguetas armadas; PredefinedType: FLOOR
Pset_QuantityTakeOff - Reference: Paño 6 (30 cm); sets with these values: 2
Pset_SlabCommon - IsExternal: no; LoadBearing: yes; Reference: Paño 6 (30 cm)

# IfcSlab: Paño 8 (30 cm)
In: F1
Type - Description: Forjado de viguetas armadas; PredefinedType: FLOOR
Pset_QuantityTakeOff - Reference: Paño 8 (30 cm); sets with these values: 2
Pset_SlabCommon - IsExternal: no; LoadBearing: yes; Reference: Paño 8 (30 cm)

# IfcWall: Forma directa:DirectShapeType 620 (5)
In: Depósito
Type - PredefinedType: STANDARD; Material: HA-25, Yc=1.5
Type - Pset_WallCommon - IsExternal: no
Description: Muro de hormigón armado
Pset_QuantityTakeOff - Reference: DirectShapeType 620; sets with these values: 2
Pset_WallCommon - LoadBearing: yes; Reference: DirectShapeType 620
Name
M1 (30)
M2 (30)
M3 (30)
M4 (30)
M5 (30)
